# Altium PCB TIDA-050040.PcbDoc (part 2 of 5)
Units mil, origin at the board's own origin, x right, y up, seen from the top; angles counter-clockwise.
Board outline 4045.79 x 2180 mil, 6 copper layers (Top Layer, Signal Layer 1, Signal Layer 2, Signal Layer 3, Signal Layer 4, Bottom Layer), stack 61.485 mil thick; 343 components, 188 nets, 986 pads, 710 vias.

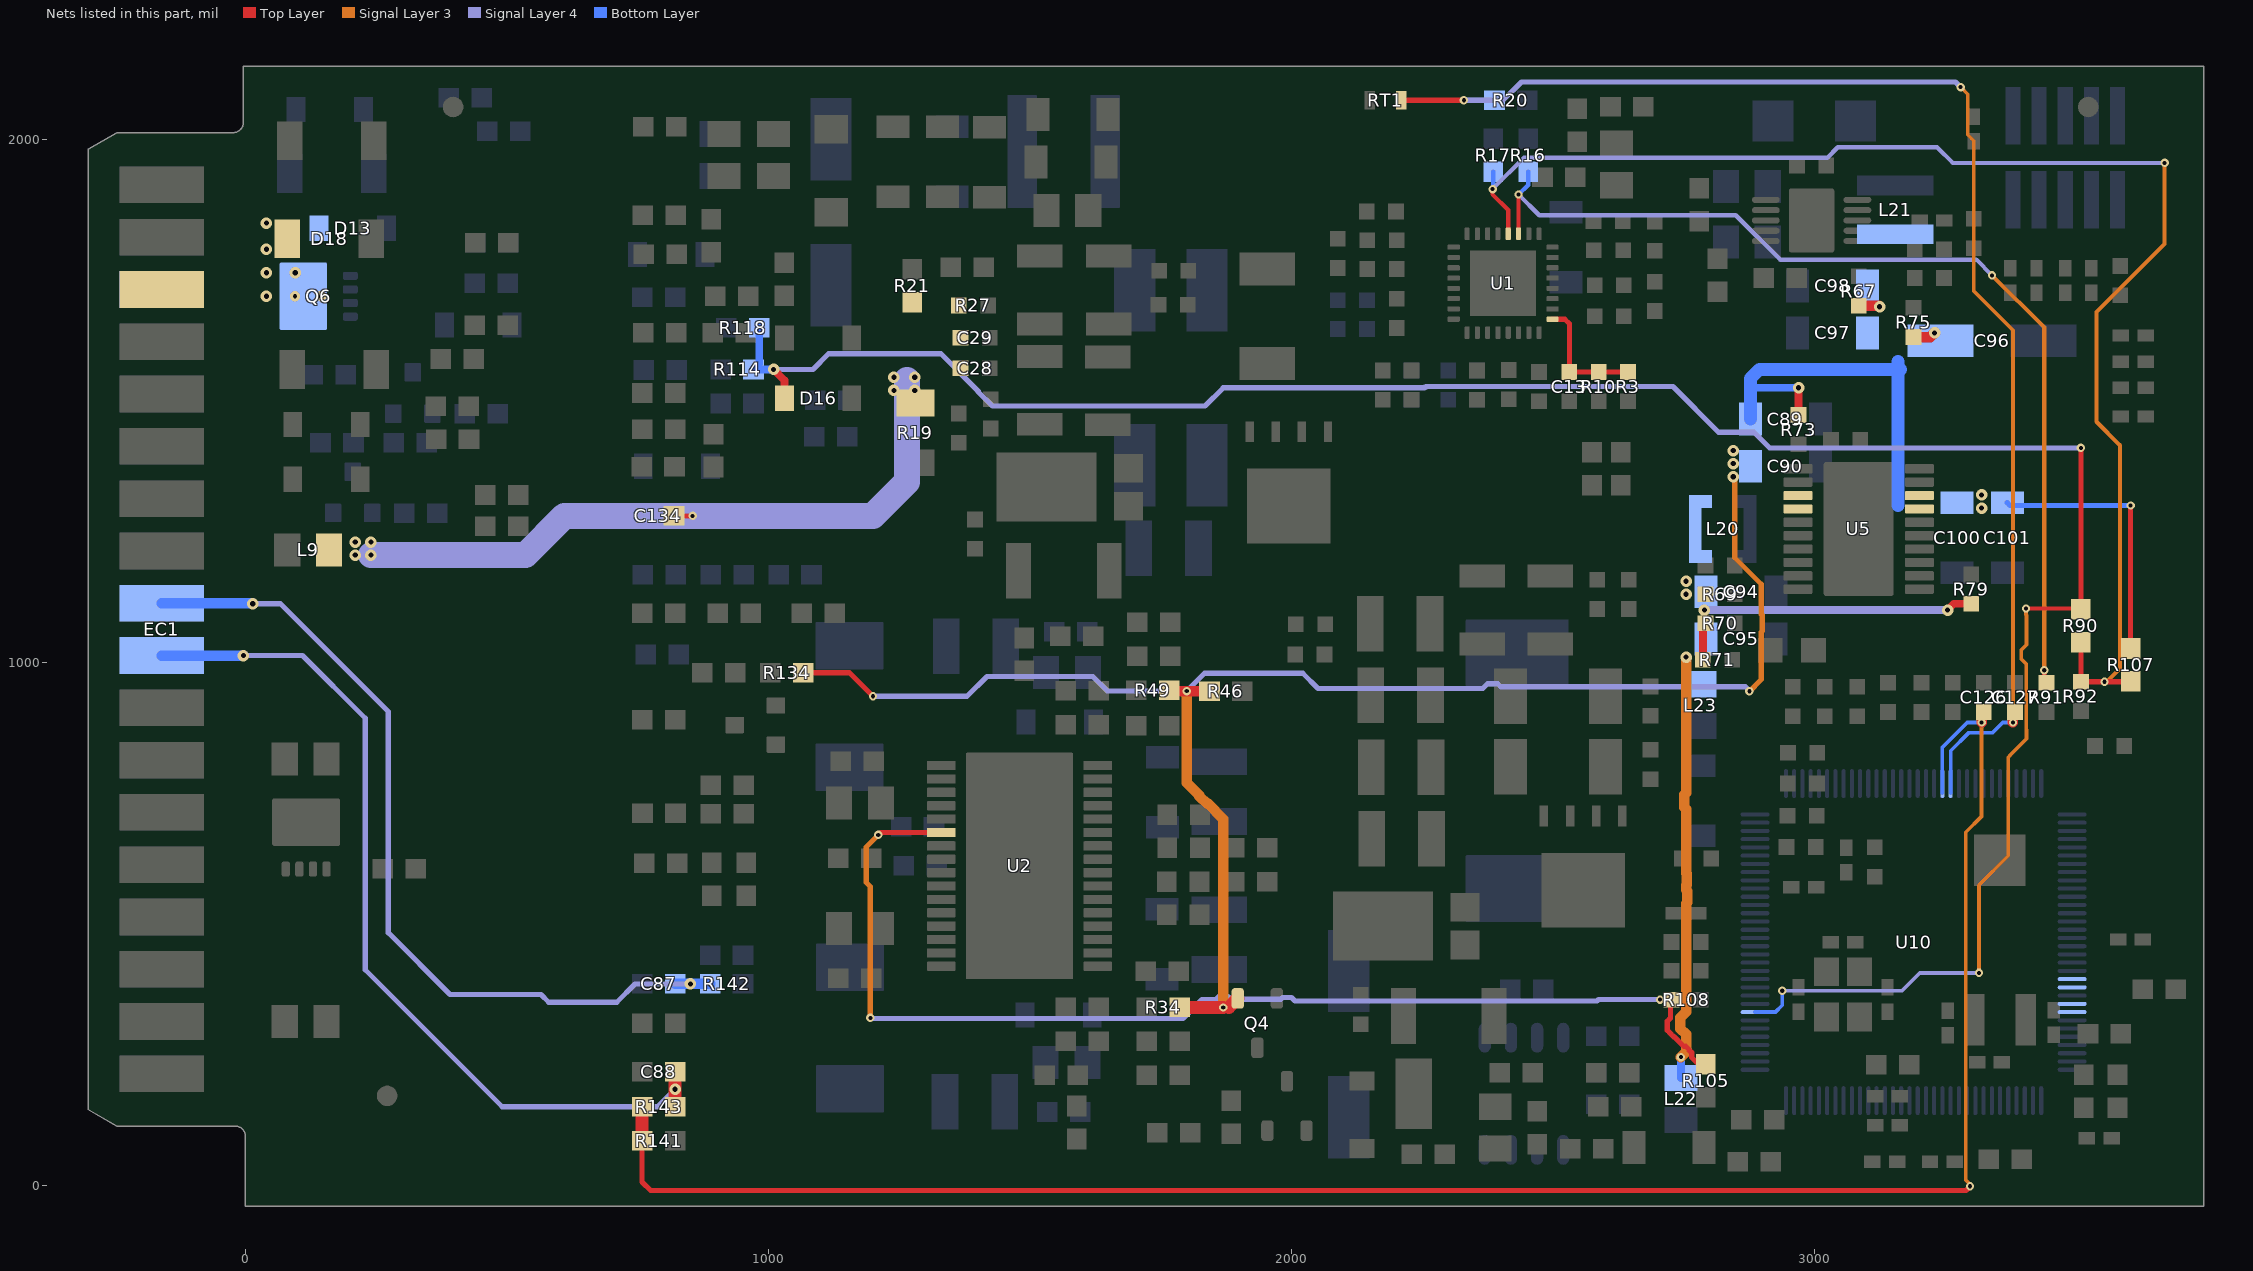
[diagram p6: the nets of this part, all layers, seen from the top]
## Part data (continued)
C5 C6 C7 C8 C30: library part CMP-0009134-2, "CAP, CERM, 4.7 uF, 100 V, +/- 10%, X7S, 1210", Cap_Case=1210_220, Manufacturer=TDK, PartNumber=C3225X7S2A475K200AB, Supplier Part Number 1=445-6042-1-ND, TempCo=X7S, Tolerance_%=10%, Value1="0.004236 ohm", ValueDisplayed=4.7uF
C11: library part CMP-0011198-2, "CAP, AL, 33 uF, 80 V, +/- 20%, 1.3 ohm, AEC-Q200 Grade 2, SMD", Cap_Case=F, Manufacturer=Panasonic, Supplier Part Number 1=PCE3829CT-ND, Tolerance_%=20%, Value1="1.3 ohm", Value2=80V, ValueDisplayed=33uF
C12 C13 C34 C37: library part CMP-0006844-4, "CAP, CERM, 1000 pF, 50 V, +/- 5%, X7R, AEC-Q200 Grade 1, 0603", Cap_Case=0603, Manufacturer=MuRata, PartNumber=GRM188R71H102KA01D, Supplier Part Number 1=490-1494-1-ND, TempCo=X7R, Tolerance_%=10%, Value1=Unknown, Value2=50V, ValueDisplayed=1000pF
C14: library part CMP-0085252-1, "CAP, CERM, 0.047 µF, 50 V,+/- 5%, X7R, 0603", Cap_Case=0603, Manufacturer=MuRata, Supplier Part Number 1=490-1522-1-ND, TempCo=X7R, Tolerance_%=10%, Value1=Unknown, Value2=25V, ValueDisplayed=0.047uF
C15 C40: library part CMP-0006822-4, "CAP, CERM, 100 pF, 50 V, +/- 5%, C0G/NP0, 0603", Cap_Case=0603, Manufacturer="Wurth Elektronik", TempCo=C0G/NP0, Tolerance_%=5%, Value1=Unknown, Value2=50V, ValueDisplayed=100pF
C16: library part CMP-0008801-2, "CAP, CERM, 1 uF, 100 V, +/- 10%, X7R, 1206", Cap_Case=1206, Manufacturer=Samsung, PartNumber=CL31B105KCHNNNE, Supplier Part Number 1=1276-1838-1-ND, TempCo=X7R, Tolerance_%=10%, Value1=Unknown, ValueDisplayed=1uF
C17 C24 C31 C32 C42 C45 C49 C57 C65 C66 C74 C85 C87 C88: library part CMP-0007148-4, "CAP, CERM, 3300 pF, 100 V, +/- 10%, X7R, AEC-Q200 Grade 1, 0603", Cap_Case=0603, Manufacturer=MuRata, Supplier Part Number 1=GCM188R72A332KA37D-ND, TempCo=X7R, Tolerance_%=10%, Value1=Unknown, Value2=100V, ValueDisplayed=3300pF
C38 C39: library part CMP-0007499-4, "CAP, CERM, 2.2 uF, 16 V, +/- 10%, X7R, 0603", Cap_Case=0603, Manufacturer=MuRata, PartNumber=GRM188Z71C225KE43, Supplier Part Number 1=81-GRM188Z71C225KE3D, TempCo=X7R, Tolerance_%=10%, Value1=Unknown, Value2=16V, ValueDisplayed=2.2uF
C41: library part CMP-0007099-4, "CAP, CERM, 0.1 uF, 100 V, +/- 10%, X7S, AEC-Q200 Grade 1, 0603", Cap_Case=0603, Manufacturer=TDK, Supplier Part Number 1=445-6938-1-ND, TempCo=X7S, Tolerance_%=10%, Value1="0.04959 ohm", ValueDisplayed=0.1uF
C43 C47: library part CMP-0008791-2, "CAP, CERM, 2.2 uF, 100 V, +/- 20%, X7S, AEC-Q200 Grade 1, 1206_190", Alternate Manufacturer="Taiyo Yuden", Alternate PartNumber=HMJ316BC7225MLHTE, Cap_Case=1206, Manufacturer=TDK, Supplier Part Number 1=445-12947-1-ND, TempCo=X7S, Tolerance_%=20%, Value1=Unknown, Value2=100V, ValueDisplayed=2.2uF
C44 C64: library part CMP-0007981-2, "CAP, CERM, 0.22 uF, 100 V, +/- 10%, X7S, AEC-Q200 Grade 1, 0805", Alternate Manufacturer="Taiyo Yuden", Alternate PartNumber=HMJ212BB7224KGHT, Cap_Case=0805, Manufacturer=TDK, Supplier Part Number 1=445-7959-1-ND, TempCo=X7S, Tolerance_%=10%, Value1="0.019477 ohm", Value2=100V, ValueDisplayed=0.22uF
C46 C63: library part CMP-0007099-4, "CAP, CERM, 0.1 uF, 100 V, +/- 10%, X7S, AEC-Q200 Grade 1, 0603", Cap_Case=0603, Manufacturer=TDK, Supplier Part Number 1=445-6938-1-ND, TempCo=X7S, Tolerance_%=10%, Value1="0.04959 ohm", Value2=100V, ValueDisplayed=0.1uF
C48 C62: library part CMP-0007085-4, "CAP, CERM, 2200 pF, 100 V, +/- 10%, X7R, AEC-Q200 Grade 1, 0603", Cap_Case=0603, Manufacturer=MuRata, Supplier Part Number 1=GRM188R71C222KA01D-ND, TempCo=X7R, Tolerance_%=10%, Value1=Unknown, Value2=16V, ValueDisplayed=2200pF
C50 C60: library part CMP-0007077-5, "CAP, CERM, 0.1 uF, 25 V, +/- 10%, X7R, AEC-Q200 Grade 1, 0603", Cap_Case=0603, Manufacturer=TDK, Supplier Part Number 1=445-5667-1-ND, TempCo=X7R, Tolerance_%=10%, Value1=Unknown, Value2=25V, ValueDisplayed=0.1uF
C51 C61: library part CMP-0007467-4, "CAP, CERM, 1000 pF, 100 V, +/- 10%, X7R, 0603", Cap_Case=0603, Manufacturer=MuRata, Supplier Part Number 1=490-1472-1-ND, TempCo=X7R, Tolerance_%=10%, Value1=Unknown, Value2=100V, ValueDisplayed=1000pF
C52 C59: library part CMP-0009148-2, "CAP, CERM, 1.5 uF, 100 V, +/- 10%, X7R, AEC-Q200 Grade 1, 1210", Cap_Case=1210_220, Manufacturer=TDK, Supplier Part Number 1=445-13014-1-ND, TempCo=X7R, Tolerance_%=10%, Value1="0.003867 ohm", Value2=100V, ValueDisplayed=1.5uF
C53 C55: library part CMP-0007136-5, "CAP, CERM, 1 uF, 16 V, +/- 10%, X7R, AEC-Q200 Grade 1, 0603", Cap_Case=0603, Manufacturer=MuRata, Supplier Part Number 1=490-5241-6-ND, TempCo=X7R, Tolerance_%=10%, Value1=Unknown, Value2=16V, ValueDisplayed=1uF
C54 C56 C58: library part CMP-0085536-1, "CAP, CERM, 0.1 µF, 16 V,+/- 10%, X7R, 0603", Cap_Case=0603, Manufacturer="Samsung Electro-Mechanics", TempCo=X7R, Tolerance_%=10%, Value2=16V, ValueDisplayed=0.1µF
C67 C71 C72 C75 C80: library part CMP-0007725-2, "CAP, CERM, 0.1 uF, 50 V, +/- 10%, X7R, AEC-Q200 Grade 0, 0805", Cap_Case=0805, Manufacturer=Kemet, Supplier Part Number 1=399-6928-1-ND, TempCo=X7R, Tolerance_%=10%, Value1=Unknown, Value2=50V, ValueDisplayed=0.1uF
C68: library part CMP-0007143-4, "CAP, CERM, 0.01 uF, 50 V, +/- 10%, X7R, AEC-Q200 Grade 1, 0603", Cap_Case=0603, Manufacturer=MuRata, Supplier Part Number 1=490-4778-1-ND, TempCo=X7R, Tolerance_%=10%, Value1=Unknown, Value2=50V, ValueDisplayed=0.01uF
C69 C70 C76 C77 C78 C79: library part CMP-0008702-2, "CAP, CERM, 4.7 uF, 50 V, +/- 10%, X7R, 1206", Cap_Case=1206_180, Manufacturer=TDK, Supplier Part Number 1=445-8032-1-ND, TempCo=X7R, Tolerance_%=10%, Value1="0.003158 ohm", Value2=50V, ValueDisplayed=4.7uF
C73: library part CMP-0011177-2, "CAP, AL, 100 uF, 50 V, +/- 20%, 0.34 ohm, AEC-Q200 Grade 2, SMD", Cap_Case=F, Manufacturer=Panasonic, Supplier Part Number 1=PCE3809CT-ND, Tolerance_%=20%, Value1="0.34 ohm", Value2=50V, ValueDisplayed=100uF
C81: library part CMP-0860912-1, "CAP, CERM, 220 pF, 100 V,+/- 5%, C0G/NP0, AEC-Q200 Grade 1, 0603", Cap_Case=0603, Manufacturer=MuRata, TempCo=C0G/NP0, Tolerance_%=5%, Value2=100V, ValueDisplayed=220pF
C82 C83: library part CMP-0080704-2, "CAP, CERM, 15 pF, 100 V,+/- 5%, C0G/NP0, AEC-Q200 Grade 1, 0603", Cap_Case=0603, Manufacturer=MuRata, Supplier Part Number 1=490-4941-1-ND, TempCo=C0G/NP0, Tolerance_%=5%, Value2=100V, ValueDisplayed=15pF
C86 C133 C134: library part CMP-0007468-5, "CAP, CERM, 0.01 uF, 100 V, +/- 10%, X7R, 0603", Cap_Case=0603, Manufacturer=MuRata, Supplier Part Number 1=GRM188R72A103KA01D-ND, TempCo=X7R, Tolerance_%=10%, Value1=Unknown, Value2=100V, ValueDisplayed=0.01uF
C89 C90 C94 C95 C97 C98 C100 C101 C110: library part CMP-0008965-2, "CAP, CERM, 10 uF, 25 V, +/- 10%, X7R, 1206", Cap_Case=2220, Manufacturer=MuRata, PartNumber=GRM31CR71E106KA12L, Supplier Part Number 1=81-GRM31CR71E106KA12, TempCo=X7R, Tolerance_%=10%, Value1=Unknown, Value2=25V, ValueDisplayed=10uF
C91: library part CMP-0007469-4, "CAP, CERM, 0.1 uF, 100 V, +/- 10%, X7R, 0603", Cap_Case=0603, Manufacturer=MuRata, PartNumber=GRM188R71C104KA01D, Supplier Part Number 1=490-1532-1-ND, TempCo=X7R, Tolerance_%=10%, Value1=Unknown, Value2=16V, ValueDisplayed=0.1uF
C92: library part CMP-0007980-2, "CAP, CERM, 1 uF, 100 V, +/- 10%, X7S, AEC-Q200 Grade 1, 0805", Cap_Case=0805, Manufacturer=TDK, Supplier Part Number 1=445-6974-1-ND, TempCo=X7S, Tolerance_%=10%, Value1="0.008255 ohm", Value2=100V, ValueDisplayed=1uF
C93: library part CMP-0007969-2, "CAP, CERM, 0.1 uF, 100 V, +/- 10%, X7R, AEC-Q200 Grade 1, 0805", Cap_Case=0805, Manufacturer=TDK, Supplier Part Number 1=445-5827-1-ND, TempCo=X7R, Tolerance_%=10%, Value1="0.020726 ohm", Value2=100V, ValueDisplayed=0.1uF
C96: library part CMP-0010733-1, "CAP, AL, 100 uF, 16 V, +/- 20%, 0.26 ohm, AEC-Q200 Grade 2, SMD", Cap_Case=D, Manufacturer=Panasonic, Supplier Part Number 1=PCE4533CT-ND, Tolerance_%=20%, Value1="0.26 ohm", Value2=16V, ValueDisplayed=100uF
C99: library part CMP-0080104-1, "CAP, CERM, 1 µF, 16 V,+/- 10%, X7R, AEC-Q200 Grade 1, 0603", Cap_Case=0603, Manufacturer=MuRata, PartNumber=GRM188R71E105KA12D, Supplier Part Number 1=490-5307-1-ND, TempCo=X7R, Tolerance_%=10%, Value1=Unknown, Value2=25V, ValueDisplayed=1uF
C102: library part CMP-0006503-2, "CAP, CERM, 5 pF, 100 V, +/- 5%, C0G/NP0, 0402", Cap_Case=0402, Manufacturer=MuRata, Supplier Part Number 1=490-7291-1-ND, TempCo=C0G/NP0, Tolerance_%=5%, Value1=Unknown, Value2=100V, ValueDisplayed=5pF
C103: library part CMP-0007086-4, "CAP, CERM, 0.022 uF, 100 V, +/- 10%, X7R, AEC-Q200 Grade 1, 0603", Cap_Case=0603, Manufacturer=TDK, Supplier Part Number 1=445-5814-1-ND, TempCo=X7R, Tolerance_%=10%, Value1="0.083542 ohm", Value2=100V, ValueDisplayed=0.022uF
C104: library part CMP-0860984-1, "CAP, CERM, 3900 pF, 100 V,+/- 5%, X7R, 0603", Cap_Case=0603, Manufacturer=MuRata, PartNumber=GRM188R71H392KA01D, Supplier Part Number 1=490-1504-1-ND, TempCo=X7R, Tolerance_%=10%, Value1=Unknown, Value2=50V, ValueDisplayed=3900pF
C105 C106 C107 C108 C109 C113 C115 C119: library part CMP-0006641-2, "CAP, CERM, 0.1 uF, 16 V, +/- 10%, X7R, 0402", Cap_Case=0402, Manufacturer=MuRata, Supplier Part Number 1=490-3261-1-ND, TempCo=X7R, Tolerance_%=10%, Value1=Unknown, Value2=16V, ValueDisplayed=0.1uF
C111: library part CMP-0007356-5, "CAP, CERM, 2.2 uF, 35 V, +/- 10%, X5R, 0603", Cap_Case=0603, Manufacturer=MuRata, Supplier Part Number 1=490-3296-1-ND, TempCo=X5R, Tolerance_%=10%, Value1=Unknown, Value2=16V, ValueDisplayed=2.2uF
C112: library part CMP-0086061-1, "CAP, CERM, 1 µF, 25 V,+/- 10%, X5R, 0402", Cap_Case=0402, Manufacturer=MuRata, Supplier Part Number 1=490-3890-1-ND, TempCo=X5R, Tolerance_%=10%, Value1=Unknown, Value2=10V, ValueDisplayed=1uF
C114: library part CMP-0008814-2, "CAP, CERM, 2.2 uF, 50 V, +/- 10%, X7R, AEC-Q200 Grade 1, 1206", Cap_Case=1206, Manufacturer=MuRata, PartNumber=GRM31CR71H225KA88L, Supplier Part Number 1=490-3367-1-ND, TempCo=X7R, Tolerance_%=10%, Value1=Unknown, Value2=50V, ValueDisplayed=2.2uF
C116 C117 C118 C124 C125 C126 C127 C128 C129 C130 C131 C132: library part CMP-0006921-4, "CAP, CERM, 330 pF, 50 V, +/- 10%, X7R, 0603", Cap_Case=0603, Manufacturer=Kemet, Supplier Part Number 1=399-1073-1-ND, TempCo=X7R, Tolerance_%=10%, Value1=Unknown, Value2=50V, ValueDisplayed=330pF
C120 C121 C122 C123: library part CMP-0006415-2, "CAP, CERM, 12 pF, 50 V, +/- 5%, C0G/NP0, 0402", Cap_Case=0402, Manufacturer=MuRata, Supplier Part Number 1=14T3292, TempCo=C0G/NP0, Tolerance_%=5%, Value1=Unknown, Value2=50V, ValueDisplayed=12pF
D1 D2: library part CMP-0028754-2, "Diode, Schottky, 100 V, 3 A, AEC-Q101, PowerDI5", Manufacturer="Diodes Inc.", Value1=3A, Value2=0.76V
D3 D4: library part CMP-0080761-2, "Diode, Switching, 100 V, 0.25 A, AEC-Q101, SOD-123", Manufacturer=Vishay-Semiconductor, Value1=0.25A, Value2=1.25V
D5: library part CMP-0085086-1, "Diode, TVS, Bi, 28 V, 45.4 Vc, 400 W, 8.8 A, AEC-Q101, SMA (non-polarized)", Manufacturer=Littelfuse, Value1=45.4V
D6 D7 D13 D14: library part CMP-0750148-1, "Diode, Switching, 100 V, 0.3 A, AEC-Q101, SOD-123", Manufacturer="Diodes Inc.", Value1=0.3A, Value2=1.25V
D8 D9 D15 D16: library part CMP-0077593-3, "Diode, Zener, 3 V, 500 mW, SOD-123", Manufacturer=Vishay-Semiconductor, Power_W=500mW, Value1=0.5W
D10: library part CMP-0002980-3, "LED, Green, SMD", Color=Green, Manufacturer=OSRAM, PartNumber="LG R971-KN-1", Value1=W, Value2=2.2V
D11: library part CMP-0028837-2, "Diode, Schottky, 60 V, 2 A, AEC-Q101, SMA", Manufacturer=Vishay-Semiconductor, PartNumber=SS26SHE3_A/H, Value1=2A, Value2=0.75V
D12 D18 D19 D20: library part CMP-0028823-2, "Diode, Schottky, 30 V, 5 A, AEC-Q101, SMAF", Manufacturer="Fairchild Semiconductor", Value1=5A, Value2=0.54V
D17: library part CMP-0077570-3, "Diode, Zener, 10 V, 500 mW, AEC-Q101, SOD-123", Manufacturer=Vishay-Semiconductor, Power_W=500mW, Value1=0.5W
D21: library part CMP-0029032-2, "Diode, Switching, 100 V, 0.2 A, SOD-123", Manufacturer="ON Semiconductor", Value1=0.2A, Value2=1V
EC1: library part CMP-0077097-2, "Card Edge Footprint, 2.54mm, 18x2", Manufacturer="Sullins Connector Solutions"
FID1 FID2 FID3: library part CMP-0077181-1, "Fiducial mark.  There is nothing to buy or mount.", Manufacturer=N/A
J3: library part CMP-0075629-2, "Header, 1.27mm, 5x2, Gold, Black, SMT", Color=Black, Current_A=3.3A, Manufacturer=Samtec, PartNumber=FTSH-105-01-F-DV, Supplier Part Number 1=SAM8795-ND
L1: library part CMP-0084138-1, "Inductor, Shielded, 22 µH, 6.9 A, 0.0341 ohm, AEC-Q200 Grade 0, SMD", Manufacturer=TDK, Value1="0.0341 ohm", Value2=6.9A, ValueDisplayed=22µH
L2 L5 L6 L8 L9: library part CMP-0003069-1, "Ferrite Bead, 33 ohm @ 100 MHz, 4 A, 0805", Manufacturer="Wurth Elektronik", Supplier Part Number 1=732-4636-1-ND, Value1="0.008 ohm", Value2=4A, ValueDisplayed="33 ohm"
L3: library part CMP-0012870-2, "Coupled inductor, 33 uH, 5.6 A, 0.15 ohm, TH", Manufacturer=Coilcraft, ValueDisplayed=33uH
L4 L7: library part CMP-0081480-2, "Inductor, Shielded, Metal Composite, 68 µH, 1.8 A, 0.316 ohm, SMD", Manufacturer=TDK, Value1="0.316 ohm", Value2=1.8A, ValueDisplayed=68µH
L10: library part CMP-0061017-2, "Inductor, Shielded, Composite, 3.3 µH, 8 A, 0.02081 ohm, AEC-Q200 Grade 1, SMD", Manufacturer=Coilcraft, Value1="0.02081 ohm", Value2=8A, ValueDisplayed=3.3µH
L20: library part CMP-0060436-1, "Inductor, Shielded Drum Core, Ferrite, 2.2 uH, 1.1 A, 0.22 ohm, SMD", Manufacturer=Coilcraft, Value1="0.22 ohm", Value2=1.1A, ValueDisplayed=2.2uH
L21: library part CMP-0061649-2, "Inductor, Shielded, Composite, 15 uH, 2.8 A, 0.109 ohm, SMD", Manufacturer=Coilcraft, PartNumber=XAL4040-153MEB, Supplier Part Number 1=994-XAL4040-153MEB, Value1="0.109 ohm", Value2=2.8A, ValueDisplayed=15uH
L22: library part CMP-0003363-1, "Ferrite Bead, 220 ohm @ 100 MHz, 2 A, 0805", Manufacturer=MuRata, PartNumber=BLM21PG221SN1D, Supplier Part Number 1=490-1054-1-ND, Value1="0.045 ohm", Value2=2A, ValueDisplayed="220 ohm"
L23: library part CMP-0003306-1, "Ferrite Bead, 60 ohm @ 100 MHz, 3 A, 0805", Manufacturer="Taiyo Yuden", PartNumber=BKP2125HS600-T, Supplier Part Number 1=587-1932-1-ND, Value1="0.025 ohm", Value2=3A, ValueDisplayed="60 ohm"
LOGO2: library part CMP-0074837-1, "IEC 61010-1 Hot Surface Warning"
Logo3: library part CMP-0074847-1, "FCC_disclaimer"
Logo4: library part CMP-0074769-1
Q1 Q3: library part CMP-0086155-1, "MOSFET, N-CH, 80 V, 60 A, AEC-Q101, PowerPAK_SO-8L", Alternate Manufacturer=None, Manufacturer=Vishay-Siliconix, Value1="? ohm", Value2="36 nC"
Q4: library part CMP-0077896-2, "MOSFET, P-CH, -20 V, -3.7 A, SOT-23", Alternate Manufacturer=None, Manufacturer=Vishay-Siliconix, Value1=0.03, Value2="12.5 nC"
Q5: library part CMP-0000419-2, "Transistor, NPN, 40 V, 0.2 A, SOT-23", Manufacturer="ON Semiconductor", Supplier Part Number 1=MMBT3904LT1GOSCT-ND, Value1="0.2 A", Value2=300
Q6: library part CMP-0000123-4, "MOSFET, P-CH, -30 V, -13.9 A, PowerPAK 1212", Alternate Manufacturer=None, Manufacturer=Vishay-Siliconix, Value1=0.022, Value2="20.5 nC"
Q7 Q8 Q10: library part CMP-0087176-1, "MOSFET N-CH 100V 170MA SOT23-3", Manufacturer="Diodes Incorporated"
Q9: library part CMP-0000752-2, "MOSFET, N-CH, 40 V, 12 A, AEC-Q101, PowerPAK 1212", Alternate Manufacturer=None, Manufacturer=Vishay-Siliconix, Supplier Part Number 1=SQS840EN-T1_GE3-ND, Value1=0, Value2="15 nC"
R1 R18: library part CMP-0016180-3, "RES, 7.5, 5%, 0.75 W, AEC-Q200 Grade 0, 2010", Manufacturer=Vishay-Dale, PartNumber=CRCW20107R50JNEF, Power_W=750mW, Supplier Part Number 1=541-7.5WCT-ND, TempCo="200 ppm/C", Tolerance_%=5%, Value2=0.75W, Value_Code=7R50, ValueDisplayed=7.5
R2 R14 R25: library part CMP-0025697-4, "RES, 0, 5%, 0.1 W, AEC-Q200 Grade 0, 0603", Manufacturer=Vishay-Dale, Power_W=100mW, Supplier Part Number 1=541-0.0GCT-ND, TempCo="200 ppm/C", Tolerance_%=5%, Value2=0.1W, Value_Code=0000, ValueDisplayed=0
R3 R58 R60 R116 R118 R121: library part CMP-0021990-4, "RES, 100 k, 1%, 0.1 W, AEC-Q200 Grade 0, 0603", Manufacturer=Vishay-Dale, Power_W=100mW, Supplier Part Number 1=541-100KHCT-ND, TempCo="100 ppm/C", Tolerance_%=1%, Value2=0.1W, Value_Code=100k
R4 R30: library part CMP-0021991-4, "RES, 100, 1%, 0.1 W, AEC-Q200 Grade 0, 0603", Manufacturer=Vishay-Dale, PartNumber=CRCW0603100RFKEA, Power_W=100mW, Supplier Part Number 1=541-100HCT-ND, TempCo="100 ppm/C", Tolerance_%=1%, Value2=0.1W, Value_Code=100R, ValueDisplayed=100
R5 R8 R21 R38 R40: library part CMP-0022200-4, "RES, 200 k, 1%, 0.1 W, AEC-Q200 Grade 0, 0603", Manufacturer=Vishay-Dale, Power_W=100mW, Supplier Part Number 1=541-200KHCT-ND, TempCo="100 ppm/C", Tolerance_%=1%, Value2=0.1W, Value_Code=200k
R6 R9 R32: library part CMP-0016519-2, "RES, 0.04, 1%, 1 W, 2010", Manufacturer="Stackpole Electronics Inc", Power_W=1W, Supplier Part Number 1=CSRN2010FK40L0CT-ND, TempCo="250 ppm/C", Tolerance_%=1%, Value_Code=R040, ValueDisplayed=0.04
R7 R13 R16 R17 R20 R46 R48 R50 R99 R102 R103 R105: library part CMP-0023341-3, "RES, 10.0 k, 1%, 0.1 W, AEC-Q200 Grade 0, 0603", Manufacturer="Stackpole Electronics Inc", Power_W=100mW, Supplier Part Number 1=RMCF0603FT10K0CT-ND, TempCo="100 ppm/C", Tolerance_%=1%, Value2=0.1W, Value_Code=10k0, ValueDisplayed=10.0k
R10: library part CMP-0022450-4, "RES, 4.12 k, 1%, 0.1 W, AEC-Q200 Grade 0, 0603", Manufacturer=Vishay-Dale, Power_W=100mW, Supplier Part Number 1=541-4.12KHCT-ND, TempCo="100 ppm/C", Tolerance_%=1%, Value2=0.1W, Value_Code=4k12, ValueDisplayed=4.12k
R11: library part CMP-0021009-3, "RES, 1.00, 1%, 0.125 W, AEC-Q200 Grade 0, 0805", Manufacturer=Vishay-Dale, PartNumber=CRCW08051R00FKEA, Power_W=125mW, Supplier Part Number 1=72M6849, TempCo="100 ppm/C", Tolerance_%=1%, Value2=0.125W, Value_Code=1R00, ValueDisplayed=1.00
R12: library part CMP-0022687-3, "RES, 14.7 k, 1%, 0.1 W, AEC-Q200 Grade 0, 0603", Manufacturer=Panasonic, Power_W=100mW, Supplier Part Number 1=P14.7KHCT-ND, TempCo="100 ppm/C", Tolerance_%=1%, Value2=0.1W, Value_Code=14k7, ValueDisplayed=14.7k
R15 R28 R90 R107: library part CMP-0022002-4, "RES, 10.0 M, 1%, 0.1 W, AEC-Q200 Grade 0, 0603", Manufacturer=Vishay-Dale, Power_W=100mW, Supplier Part Number 1=541-10.0MHCT-ND, TempCo="100 ppm/C", Tolerance_%=1%, Value2=0.1W, Value_Code=10M0, ValueDisplayed=10.0M
R19: library part CMP-0017835-2, "RES, 0.165, 1%, 0.25 W, 1206", Manufacturer="Yageo America", Power_W=250mW, Supplier Part Number 1=311-0.165ANCT-ND, TempCo="75 ppm/C", Tolerance_%=1%, Value2=0.25W, Value_Code=R165, ValueDisplayed=0.165
R22: library part CMP-0022408-4, "RES, 402 k, 1%, 0.1 W, AEC-Q200 Grade 0, 0603", Manufacturer=Vishay-Dale, Power_W=100mW, Supplier Part Number 1=541-402KHCT-ND, TempCo="100 ppm/C", Tolerance_%=1%, Value2=0.1W, Value_Code=402k
R23 R39 R41 R44 R54 R55 R56 R57 R59 R61 R62 R66 R111 R112 R113 R114 R115 R117 R120 R123 R124 R125 R126 R128 R129 R130 R131 R135 R136 R140 R141: library part CMP-0021998-4, "RES, 10.0 k, 1%, 0.1 W, AEC-Q200 Grade 0, 0603", Manufacturer=Vishay-Dale, Power_W=100mW, Supplier Part Number 1=541-10.0KHCT-ND, TempCo="100 ppm/C", Tolerance_%=1%, Value2=0.1W, Value_Code=10k0, ValueDisplayed=10.0k
R24: library part CMP-0021990-4, "RES, 100 k, 1%, 0.1 W, AEC-Q200 Grade 0, 0603", Manufacturer=Vishay-Dale, PartNumber=CRCW0603100KFKEA, Power_W=100mW, Supplier Part Number 1=541-100KHCT-ND, TempCo="100 ppm/C", Tolerance_%=1%, Value2=0.1W, Value_Code=100k
R26 R27: library part CMP-0022003-4, "RES, 10.0, 1%, 0.1 W, AEC-Q200 Grade 0, 0603", Manufacturer=Vishay-Dale, PartNumber=CRCW060310R0FKEA, Power_W=100mW, Supplier Part Number 1=541-10.0HCT-ND, TempCo="100 ppm/C", Tolerance_%=1%, Value2=0.1W, Value_Code=10R0, ValueDisplayed=10.0
R29: library part CMP-0022665-4, "RES, 9.09 k, 1%, 0.1 W, AEC-Q200 Grade 0, 0603", Manufacturer=Vishay-Dale, Power_W=100mW, Supplier Part Number 1=541-9.09KHCT-ND, TempCo="100 ppm/C", Tolerance_%=1%, Value2=0.1W, Value_Code=9k09, ValueDisplayed=9.09k
R31: library part CMP-0022036-4, "RES, 130 k, 1%, 0.1 W, AEC-Q200 Grade 0, 0603", Manufacturer=Vishay-Dale, Power_W=100mW, Supplier Part Number 1=541-130KHCT-ND, TempCo="100 ppm/C", Tolerance_%=1%, Value2=0.1W, Value_Code=130k
R33: library part CMP-0022440-4, "RES, 47.5, 1%, 0.1 W, AEC-Q200 Grade 0, 0603", Manufacturer=Vishay-Dale, Power_W=100mW, Supplier Part Number 1=541-47.5HCT-ND, TempCo="100 ppm/C", Tolerance_%=1%, Value2=0.1W, Value_Code=47R5, ValueDisplayed=47.5
R34 R49: library part CMP-0022068-4, "RES, 15.8 k, 1%, 0.1 W, AEC-Q200 Grade 0, 0603", Manufacturer=Vishay-Dale, Power_W=100mW, Supplier Part Number 1=541-15.8KHCT-ND, TempCo="100 ppm/C", Tolerance_%=1%, Value2=0.1W, Value_Code=15k8, ValueDisplayed=15.8k
R35 R52: library part CMP-0015068-3, "RES, 0.1, 1%, 0.33 W, AEC-Q200 Grade 1, 1210", Alternate Manufacturer=Yageo, Alternate PartNumber=RL1210FR-070R1L, Manufacturer=Panasonic, Power_W=330mW, Supplier Part Number 1=P100NACT-ND, TempCo="100 ppm/C", Tolerance_%=1%, Value2=0.33W, Value_Code=R100, ValueDisplayed=0.1
R36 R43 R51 R108 R109 R110 R122 R127 R132 R133 R134 R137 R138 R139 R142 R143: library part CMP-0022109-5, "RES, 1.00 k, 1%, 0.1 W, AEC-Q200 Grade 0, 0603", Manufacturer=Vishay-Dale, Power_W=100mW, Supplier Part Number 1=541-1.00KHCT-ND, TempCo="100 ppm/C", Tolerance_%=1%, Value2=0.1W, Value_Code=1k00, ValueDisplayed=1.00k
R37 R53: library part CMP-0022324-4, "RES, 30.1 k, 1%, 0.1 W, AEC-Q200 Grade 0, 0603", Manufacturer=Vishay-Dale, Power_W=100mW, Supplier Part Number 1=541-30.1KHCT-ND, TempCo="100 ppm/C", Tolerance_%=1%, Value2=0.1W, Value_Code=30k1, ValueDisplayed=30.1k
R42 R45: library part CMP-0025874-4, "RES, 0, 5%, 0.1 W, AEC-Q200 Grade 0, 0603", Manufacturer=Panasonic, Power_W=100mW, Supplier Part Number 1=P0.0GCT-ND, TempCo="600 ppm/C", Tolerance_%=5%, Value2=0.1W, Value_Code=0000, ValueDisplayed=0
R47: library part CMP-0022237-4, "RES, 24.9 k, 1%, 0.1 W, AEC-Q200 Grade 0, 0603", Manufacturer=Vishay-Dale, Power_W=100mW, Supplier Part Number 1=541-24.9KHCT-ND, TempCo="100 ppm/C", Tolerance_%=1%, Value2=0.1W, Value_Code=24k9, ValueDisplayed=24.9k
R63 R64 R65 R100 R144: library part CMP-0022003-4, "RES, 10.0, 1%, 0.1 W, AEC-Q200 Grade 0, 0603", Manufacturer=Vishay-Dale, Power_W=100mW, Supplier Part Number 1=541-10.0HCT-ND, TempCo="100 ppm/C", Tolerance_%=1%, Value2=0.1W, Value_Code=10R0, ValueDisplayed=10.0
R67 R70 R79: library part CMP-0023133-5, "RES, 47.0 k, 1%, 0.1 W, 0603", Manufacturer=Yageo, PartNumber=RC0603FR-0747KL, Power_W=100mW, Supplier Part Number 1=311-47.0KHRCT-ND, TempCo="100 ppm/C", Tolerance_%=1%, Value2=0.1W, Value_Code=47k0, ValueDisplayed=47.0k
R68: library part CMP-0022701-2, "RES, 402 k, 1%, 0.1 W, AEC-Q200 Grade 0, 0603", Manufacturer=Panasonic, Power_W=100mW, Supplier Part Number 1=P402KHCT-ND, TempCo="100 ppm/C", Tolerance_%=1%, Value2=0.1W, Value_Code=402k
R69: library part CMP-0023026-5, "RES, 31.6 k, 1%, 0.1 W, 0603", Manufacturer=Yageo, PartNumber=RC0603FR-0731K6L, Power_W=100mW, Supplier Part Number 1=311-31.6KHRCT-ND, TempCo="100 ppm/C", Tolerance_%=1%, Value2=0.1W, Value_Code=31k6, ValueDisplayed=31.6k
R71: library part CMP-0023235-5, "RES, 680, 1%, 0.1 W, 0603", Manufacturer=Yageo, PartNumber=RC0603FR-07680RL, Power_W=100mW, Supplier Part Number 1=311-680HRCT-ND, TempCo="100 ppm/C", Tolerance_%=1%, Value2=0.1W, Value_Code=680R, ValueDisplayed=680
R72 R77: library part CMP-0021998-4, "RES, 10.0 k, 1%, 0.1 W, AEC-Q200 Grade 0, 0603", Manufacturer=Vishay-Dale, PartNumber=CRCW060310K0FKEA, Power_W=100mW, Supplier Part Number 1=541-10.0KHCT-ND, TempCo="100 ppm/C", Tolerance_%=1%, Value2=0.1W, Value_Code=10k0, ValueDisplayed=10.0k
R73: library part CMP-0025821-4, "RES, 4.7, 5%, 0.1 W, AEC-Q200 Grade 0, 0603", Manufacturer=Vishay-Dale, PartNumber=CRCW06034R70JNEA, Power_W=100mW, Supplier Part Number 1=541-4.7GCT-ND, TempCo="200 ppm/C", Tolerance_%=5%, Value2=0.1W, Value_Code=4R70, ValueDisplayed=4.7
R74: library part CMP-0022038-4, "RES, 133 k, 1%, 0.1 W, AEC-Q200 Grade 0, 0603", Manufacturer=Vishay-Dale, PartNumber=CRCW0603133KFKEA, Power_W=100mW, Supplier Part Number 1=541-133KHCT-ND, TempCo="100 ppm/C", Tolerance_%=1%, Value2=0.1W, Value_Code=133k
R75: library part CMP-0022486-4, "RES, 52.3 k, 1%, 0.1 W, AEC-Q200 Grade 0, 0603", Manufacturer=Vishay-Dale, PartNumber=CRCW060352K3FKEA, Power_W=100mW, Supplier Part Number 1=541-52.3KHCT-ND, TempCo="100 ppm/C", Tolerance_%=1%, Value2=0.1W, Value_Code=52k3, ValueDisplayed=52.3k
R76: library part CMP-0022659-4, "RES, 95.3 k, 1%, 0.1 W, AEC-Q200 Grade 0, 0603", Manufacturer=Vishay-Dale, PartNumber=CRCW060395K3FKEA, Power_W=100mW, Supplier Part Number 1=541-95.3KHCT-ND, TempCo="100 ppm/C", Tolerance_%=1%, Value2=0.1W, Value_Code=95k3, ValueDisplayed=95.3k
R78: library part CMP-0022581-4, "RES, 71.5 k, 1%, 0.1 W, AEC-Q200 Grade 0, 0603", Manufacturer=Vishay-Dale, Power_W=100mW, Supplier Part Number 1=541-71.5KHCT-ND, TempCo="100 ppm/C", Tolerance_%=1%, Value2=0.1W, Value_Code=71k5, ValueDisplayed=71.5k
R80: library part CMP-0026763-1, "RES, 100, 1%, 0.063 W, AEC-Q200 Grade 0, 0402", Manufacturer="Stackpole Electronics Inc", Power_W=63mW, Supplier Part Number 1=RMCF0402JT100RCT-ND, TempCo="100 ppm/C", Tolerance_%=1%, Value2=0.063W, Value_Code=100R, ValueDisplayed=100
R81 R82 R83 R84: library part CMP-0026754-1, "RES, 10.0 k, 1%, 0.063 W, AEC-Q200 Grade 0, 0402", Manufacturer="Stackpole Electronics Inc", Power_W=63mW, Supplier Part Number 1=RMCF0402FT10K0CT-ND, TempCo="100 ppm/C", Tolerance_%=1%, Value2=0.063W, Value_Code=10k0, ValueDisplayed=10.0k
R85 R86 R87 R88: library part CMP-0026759-1, "RES, 33.0, 1%, 0.063 W, AEC-Q200 Grade 0, 0402", Manufacturer="Stackpole Electronics Inc", Power_W=63mW, Supplier Part Number 1=RMCF0402FT33R0CT-ND, TempCo="100 ppm/C", Tolerance_%=1%, Value2=0.063W, Value_Code=33R0, ValueDisplayed=33.0
R89 R91 R92 R94 R96: library part CMP-0025697-4, "RES, 0, 5%, 0.1 W, AEC-Q200 Grade 0, 0603", Manufacturer=Vishay-Dale, PartNumber=CRCW06030000Z0EA, Power_W=100mW, Supplier Part Number 1=541-0.0GCT-ND, TempCo="200 ppm/C", Tolerance_%=5%, Value2=0.1W, Value_Code=0000, ValueDisplayed=0
R93: library part CMP-0022986-5, "RES, 2.20 k, 1%, 0.1 W, 0603", Manufacturer=Yageo, PartNumber=RC0603FR-072K2L, Power_W=100mW, Supplier Part Number 1=311-2.20KHRCT-ND, TempCo="100 ppm/C", Tolerance_%=1%, Value2=0.1W, Value_Code=2k20, ValueDisplayed=2.20k
R95: library part CMP-0023169-5, "RES, 51.0, 1%, 0.1 W, 0603", Manufacturer=Yageo, Power_W=100mW, Supplier Part Number 1=311-51.0HRCT-ND, TempCo="100 ppm/C", Tolerance_%=1%, Value2=0.1W, Value_Code=51R0, ValueDisplayed=51.0
R97: library part CMP-0022138-4, "RES, 1.00 M, 1%, 0.1 W, AEC-Q200 Grade 0, 0603", Manufacturer=Vishay-Dale, Power_W=100mW, Supplier Part Number 1=541-1.00MHCT-ND, TempCo="100 ppm/C", Tolerance_%=1%, Value2=0.1W, Value_Code=1M00, ValueDisplayed=1.00M
R98 R119: library part CMP-0022747-4, "RES, 10.0 M, 1%, 0.1 W, 0603", Manufacturer=Yageo, Power_W=100mW, Supplier Part Number 1=311-10.0MHRCT-ND, TempCo="100 ppm/C", Tolerance_%=1%, Value2=0.1W, Value_Code=10M0, ValueDisplayed=10.0M
R101: library part CMP-0022457-4, "RES, 4.87 k, 1%, 0.1 W, AEC-Q200 Grade 0, 0603", Manufacturer=Vishay-Dale, Power_W=100mW, Supplier Part Number 1=541-4.87KHCT-ND, TempCo="100 ppm/C", Tolerance_%=1%, Value2=0.1W, Value_Code=4k87, ValueDisplayed=4.87k
R104: library part CMP-0027004-2, "RES, 0, 5%, 0.063 W, 0402", Manufacturer="Yageo America", Power_W=63mW, Supplier Part Number 1=311-0.0JRCT-ND, TempCo="200 ppm/C", Tolerance_%=5%, Value2=0.063W, Value_Code=0000, ValueDisplayed=0
R106: library part CMP-0026889-5, "RES, 2.0 k, 5%, 0.063 W, AEC-Q200 Grade 0, 0402", Manufacturer=Vishay-Dale, Power_W=63mW, Supplier Part Number 1=541-2.0KJCT-ND, TempCo="200 ppm/C", Tolerance_%=5%, Value2=0.063W, Value_Code=2k00, ValueDisplayed=2.0k
RT1: library part CMP-0002534-3, "Thermistor NTC, 100k ohm, 5%, 0603", Manufacturer=MuRata, Power_W=100mW, Supplier Part Number 1=490-2430-1-ND, Tolerance_%=5%
TP1: library part CMP-0055152-1, "Test Point, Miniature, SMT", Manufacturer=Keystone, Supplier Part Number 1=36-5015TR-ND
U1: library part CMP-0084188-3, "Dual Channel Constant Voltage and Constant Current Controller with SPI Interface, RHM0032C (VQFNP-32)", Alternate Manufacturer="Texas Instruments", Operating Temperature Range="-40 to 125 C", Rating=Automotive
U2: library part CMP-0085387-1, "4.5 to 65-V Input Dual 1.6-A Synchronous Buck LED Driver with SPI Control, DAP0032A (HTSSOP-32)", Alternate Manufacturer="Texas Instruments", Alternate PartNumber=TPS92520QDAPQ1
U3: library part CMP-0079113-2, "Local Interconnect Network (LIN) Transceiver with Dominant State Timeout, D0008A (SOIC-8)", Alternate Manufacturer="Texas Instruments", Alternate PartNumber=TLIN1029DQ1
U4: library part CMP-0074018-2, "Automotive 3.5V to 60V, 1.5A Step Down SWIFT(TM) Converter with Eco-Mode(TM), DGQ0010D (VSSOP-10)", Alternate Manufacturer="Texas Instruments", PartNumber=TPS57160QDGQRQ1
U5: library part CMP-0066062-3, "Dual 2.0A, High Frequency Synchronous Step-Down DC-DC  Regulator, PWP0020A (HTSSOP-20)", Alternate Manufacturer="Texas Instruments", Alternate PartNumber=LM26420Q0XMH/NOPB, Operating Temperature Range="-40 to 125 C", PartNumber=LM26420Q0XMHX/NOPB, Rating=Automotive
U10: library part CMP-0077953-1, "MSP432E401YTPDT, PDT0128A (TQFP-128)", Alternate Manufacturer="Texas Instruments", Alternate PartNumber=MSP432E401YTPDTR
Y1: library part CMP-0004653-5, "Crystal, 32.768 kHz,  SMD", Frequency_Fixed=32.768kHz, Frequency Stability=+/-20ppm, Manufacturer="Citizen FineDevice", Supplier Part Number 1=695-CMR200T32.7KY-U
Y2: library part CMP-0004652-3, "Crystal, 25 MHz, 8pF, SMD", Frequency_Fixed=25MHz, Frequency Stability=+/-30ppm, Manufacturer=NDK, Supplier Part Number 1=644-1259-1-ND
ZZ1: library part CMP-0003616-3
ZZ2: library part CMP-0077236-1
ZZ3: library part CMP-0077237-1
ZZ4: library part CMP-0077238-1

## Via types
v1: diameter 16, hole 8, Top Layer to Bottom Layer, tented both sides, 318 vias
v2: diameter 22, hole 10, Top Layer to Bottom Layer, tented both sides, 299 vias
v3: diameter 19.68, hole 7.87, Top Layer to Bottom Layer, 47 vias
v4: diameter 19.68, hole 7.87, Top Layer to Bottom Layer, tented both sides, 28 vias
v5: diameter 50, hole 28, Top Layer to Bottom Layer, 18 vias

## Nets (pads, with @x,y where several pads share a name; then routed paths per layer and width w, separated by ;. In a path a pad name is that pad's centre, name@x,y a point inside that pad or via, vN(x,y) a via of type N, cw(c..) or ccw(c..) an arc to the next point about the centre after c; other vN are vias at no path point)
3V3: C94.1 C95.1 L20.2 L22.1 L23.1 R69.1 R70.2 R71.2 R79.2 | length 1389.1
  Top Layer w15: 2787,1020 R70.2@2787,1070 ; v2(3255,1100) 3267,1112 R79.2@3300,1112
  Signal Layer 3 w20: v1(2745,245) 2755,255 2755,288.41 2744.13,299.28 2744.13,320.72 2755,331.59 2755,538.41 2757.49,540.9 2757.49,562.33 2755,564.82 2755,573.41 2755.87,574.28 2755.87,595.72 2755,596.59 2755,719.17 2751.13,723.04 2751.13,746.96 2755,750.83 v2(2755,1010)
  Signal Layer 4 w15: v2(2790,1100) v2(3255,1100)
  Bottom Layer w15: L22.1@2745,205 v1(2745,245)
  other v2: 2755,1130 2755,1155
5V: C89.1 C90.1 C96.1 C97.1 C98.1 C100.1 C101.1 L21.2 Q4.2 R34.2 R46.2 R49.2 R67.2 R73.1 R75.2 R107.1 R134.2 U5.3 U5.4 U5.17 U5.18 | length 4539.3
  Top Layer w10: R134.2@1066.5,980 1155,980 v1(1200,935) ; R49.2@1766.5,945.99 1777.21,945.99 R49.2@1778.2,945 ; R107.1@3605,1026.5 v1(3605,1300)
  Top Layer w15: R73.1@2970,1473 v2(2970,1525)
  Top Layer w20: R49.2@1778.2,945 v1(1800,945) R46.2@1843.5,945 ; R67.2@3085,1682 v2@3123,1682 ; R75.2@3190,1622 3222,1622 v2(3230,1630)
  Top Layer w25: R34.2@1786.5,340 v1(1870,340) ; 1880.35,340 Q4.2@1897.6,357.24
  Signal Layer 3 w10: v2@2848,1355 2848,1200 2898.75,1149.25 2898.75,1091.81 2900.75,1089.81 2900.75,1060.19 2898.75,1058.19 2898.75,967.25 v1(2876,944.5)
  Signal Layer 3 w20: v1(1800,945) 1800,770 1824.13,745.87 1824.13,744.28 1839.28,729.13 1840.87,729.13 1870,700 v1(1870,340)
  Signal Layer 4 w10: v1(1200,935) 1380,935 1417.87,972.87 1620.33,972.87 1648.2,945 v1(1800,945) 1834,979 2022,979 2051,950 2366.24,950 2375.11,958.87 2394.89,958.87 2400.52,953.24 2868.76,953.24 2876,946 v1(2876,944.5)
  Bottom Layer w10: C101.1@3369.21,1305.25 3374.46,1300 v1(3605,1300)
  Bottom Layer w15: 2878.07,1523.07 2880,1525 v2(2970,1525)
  Bottom Layer w25: C89.1@2878.07,1465 2878.07,1523.07 2878.07,1543.07 2895,1560 3165,1560 ; 3160,1300 3160,1575
  other v2: 3320,1295 3320,1320 2845,1355 2845,1380 2845,1405 3125,1680
A_NTC1: C127.1 R20.1 RT1.2 U10.21 | length 2646
  Top Layer w10: RT1.2@2210,2075 v1(2330,2075)
  Top Layer w20: v1(3380,885) C127.1@3380,905
  Signal Layer 3 w7: v1(3280,2100) 3293.7,2086.3 3293.7,2008.7 3299.37,2003.03 3299.37,2002.87 3305,1997.24 3305,1710 3380,1635 v1(3380,885)
  Signal Layer 4 w10: v1(2330,2075) 2405,2075 2440,2110 3270,2110 v1(3280,2100)
  Bottom Layer w7: U10.21@3260.87,750 3260.87,830.87 3295,865 3340.54,865 3360.54,885 v1(3380,885)
  Bottom Layer w10: v1(2330,2075) R20.1@2388.5,2075
BPWM1: R16.1 R91.2 U1.3 | length 1916.6
  Top Layer w8: U1.3@2434.53,1819.49 v1(2434.53,1894.53) ; R91.2@3440,961 v1(3440,985)
  Signal Layer 3 w8: v1(3340,1740) 3440,1640 v1(3440,985)
  Signal Layer 4 w8: v1(2434.53,1894.53) 2474.06,1855 2850,1855 2935,1770 3310,1770 v1(3340,1740)
  Bottom Layer w8: v1(2434.53,1894.53) 2453,1913 R16.1@2453,1938.5
BUCK_nFLT_1-2: R105.1 R108.2 U2.22 | length 2224
  Top Layer w10: v1(1210,670) 1214.57,674.57 U2.22@1330.59,674.57 ; v1(2705,355) R108.2@2727,355 2725,353 2725,319.52 2719.13,313.65 2719.13,296.35 2725,290.48 2725,290 2730,285 2730.48,285 2731.35,284.13 2731.75,284.13 2750,265.87 2753.65,265.87 2764.52,255 2765,255 2765,254.52 2765.87,253.65 2765.87,244.13 2780,230 2803.5,230 R105.1@2805,231.5
  Signal Layer 3 w10: v1(1195,320) 1194.74,320.26 1194.74,570.74 1194.13,571.35 1194.13,571.87 1187,579 1187,647 v1(1210,670)
  Signal Layer 4 w10: v1@1195,319 1793,319 1829,355 1855.48,355 1861.35,360.87 1878.65,360.87 1883.77,355.75 1979.98,355.75 1983.05,358.82 2000.34,358.82 2007.04,352.13 2584.48,352.13 2587.35,355 v1(2705,355)
DRL_NTC: C126.1 R141.1 R143.2 U10.20 | length 3798.1
  Top Layer w10: R141.1@758.5,85 758.5,6.5 775,-10 3290,-10 v1(3298,-2)
  Top Layer w20: v1(3320,885) C126.1@3320,905
  Top Layer w25: R141.1@758.5,85 R143.2@758.5,150
  Signal Layer 3 w7: v1(3298,-2) 3298,2 3290,10 3290,675 3320,705 v1(3320,885)
  Bottom Layer w7: U10.20@3245.12,750 3245.12,837.72 3292.4,885 v1(3320,885)
DRLPOS: D13.2 D18.2 EC1.5 EC1.6 Q6.5 Q6.6 Q6.7 Q6.8 Q6.9@110.67,1700
  other v2: 40,1700 40,1745 95,1745 40,1790 40,1840
  other v3: 94.72,1700 144.92,1700
DRLPOS+: C28.1 C29.1 C134.1 L9.1 R19.2 R21.2 R27.2 | length 3136.5
  Top Layer w10: C134.1@816.5,1280 v1(855,1280)
  Signal Layer 4 w50: v2(240,1205) 535,1205 ; v2(240,1205) 535,1205 ; v2(240,1205) 535,1205 ; v2(240,1205) 535,1205 ; 535,1205 610,1280 1200,1280 1265,1345 ; 1265,1345 1265,1520 1265,1345 ; 1265,1345 1265,1540 ; 1265,1345 1265,1540 ; 1265,1345 1265,1540 ; 1265,1345 1265,1540
  other v2: 210,1205 210,1230 240,1230 1240,1520 1280,1520 1240,1545 1280,1545
DRLPOS_MICRO: D16.1 R90.1 R114.2 R118.2 U10.104 | length 4438.8
  Top Layer w7: v1(3405,1103) 3508.5,1103 R90.1@3510,1101.5
  Top Layer w10: R90.1@3510,1101.5 v1(3510,1410)
  Top Layer w15: v2(1010,1560) 1030.53,1539.47 D16.1@1030.53,1505
  Signal Layer 3 w7: v1(3315,406) 3315,574 3371.1,630.1 3371.1,818.7 3374.37,821.98 3374.37,822.37 3406,854 3406,870.57 3405.75,870.81 3405.75,878.21 3405.13,878.84 3405.13,997.47 3395.63,1006.98 3395.63,1023.02 3406,1033.4 3406,1090 3405,1091 v1(3405,1103)
  Signal Layer 4 w7: v1(2939,372) 3168,372 3202,406 v1(3315,406)
  Signal Layer 4 w10: v2(1010,1560) 1085,1560 1115,1590 1330,1590 1401.13,1518.87 1401.13,1517.28 1428.4,1490 1835,1490 1870,1525 2254.24,1525 2255.11,1525.87 2256.76,1525.87 2258.21,1527.33 2729.67,1527.33 2817,1440 2885,1440 2915,1410 v1(3510,1410)
  Bottom Layer w7: U10.104@2886.85,331.14 2926.14,331.14 2939,344 v1(2939,372)
  Bottom Layer w15: R118.2@982.5,1640 982.5,1571 R114.2@971.5,1560 v2(1010,1560)
DRLPOS_NTC: C88.1 EC1.20 R143.1 | length 1701.7
  Top Layer w25: R143.1@821.5,150 v2(821.5,183.43) C88.1@821.5,216.85
  Signal Layer 4 w10: v2(-3.99,1012.99) 109.01,1012.99 229,893 229,412 491,150 788.07,150 v2(821.5,183.43)
  Bottom Layer w20: EC1.20@-160.24,1012.99 v2(-3.99,1012.99)
DRLPOS_RBIN: C87.1 EC1.18 R142.1 | length 1656.6
  Signal Layer 4 w10: v2(14,1112) 67,1112 273,906 273,483 391,365 565,365 580,350 710,350 745,385 v2(851.02,385)
  Bottom Layer w20: EC1.18@-160.24,1112.99 13.01,1112.99 v2(14,1112) ; C87.1@821.5,385 v2(851.02,385) R142.1@888.5,385
DRLPOSPWM: R17.1 R90.2 R92.2 R107.2 U1.4 | length 2711.2
  Top Layer w8: v1(2385,1905) 2385,1895 2414.84,1865.16 U1.4@2414.84,1819.49
  Top Layer w10: R90.2@3510,1038.5 R92.2@3510,963 3604.5,963 R107.2@3605,963.5
  Signal Layer 3 w8: v1(3555,963) 3559.5,963 3585,988.5 3585,1415 3540,1460 3540,1670 3670,1800 v1(3670,1955)
  Signal Layer 4 w8: v1(2385,1905) 2445,1965 3025,1965 3045,1985 3235,1985 3265,1955 v1(3670,1955)
  Bottom Layer w8: v1@2386,1906 R17.1@2386,1938.5
EN0RXI_N: U10.53
EN0RXI_P: U10.54
EN0TXO_N: U10.56
EN0TXO_P: U10.57
FB1: C13.2 R3.1 R10.2 U1.25 | length 240
  Top Layer w10: U1.25@2499.49,1656.1 2522.99,1656.1 2531.76,1647.34 C13.2@2531.76,1555.24 R10.2@2587.76,1555.24 R3.1@2643.76,1555.24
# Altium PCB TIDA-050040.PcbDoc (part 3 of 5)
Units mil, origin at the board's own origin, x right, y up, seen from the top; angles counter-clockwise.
Board outline 4045.79 x 2180 mil, 6 copper layers (Top Layer, Signal Layer 1, Signal Layer 2, Signal Layer 3, Signal Layer 4, Bottom Layer), stack 61.485 mil thick; 343 components, 188 nets, 986 pads, 710 vias.

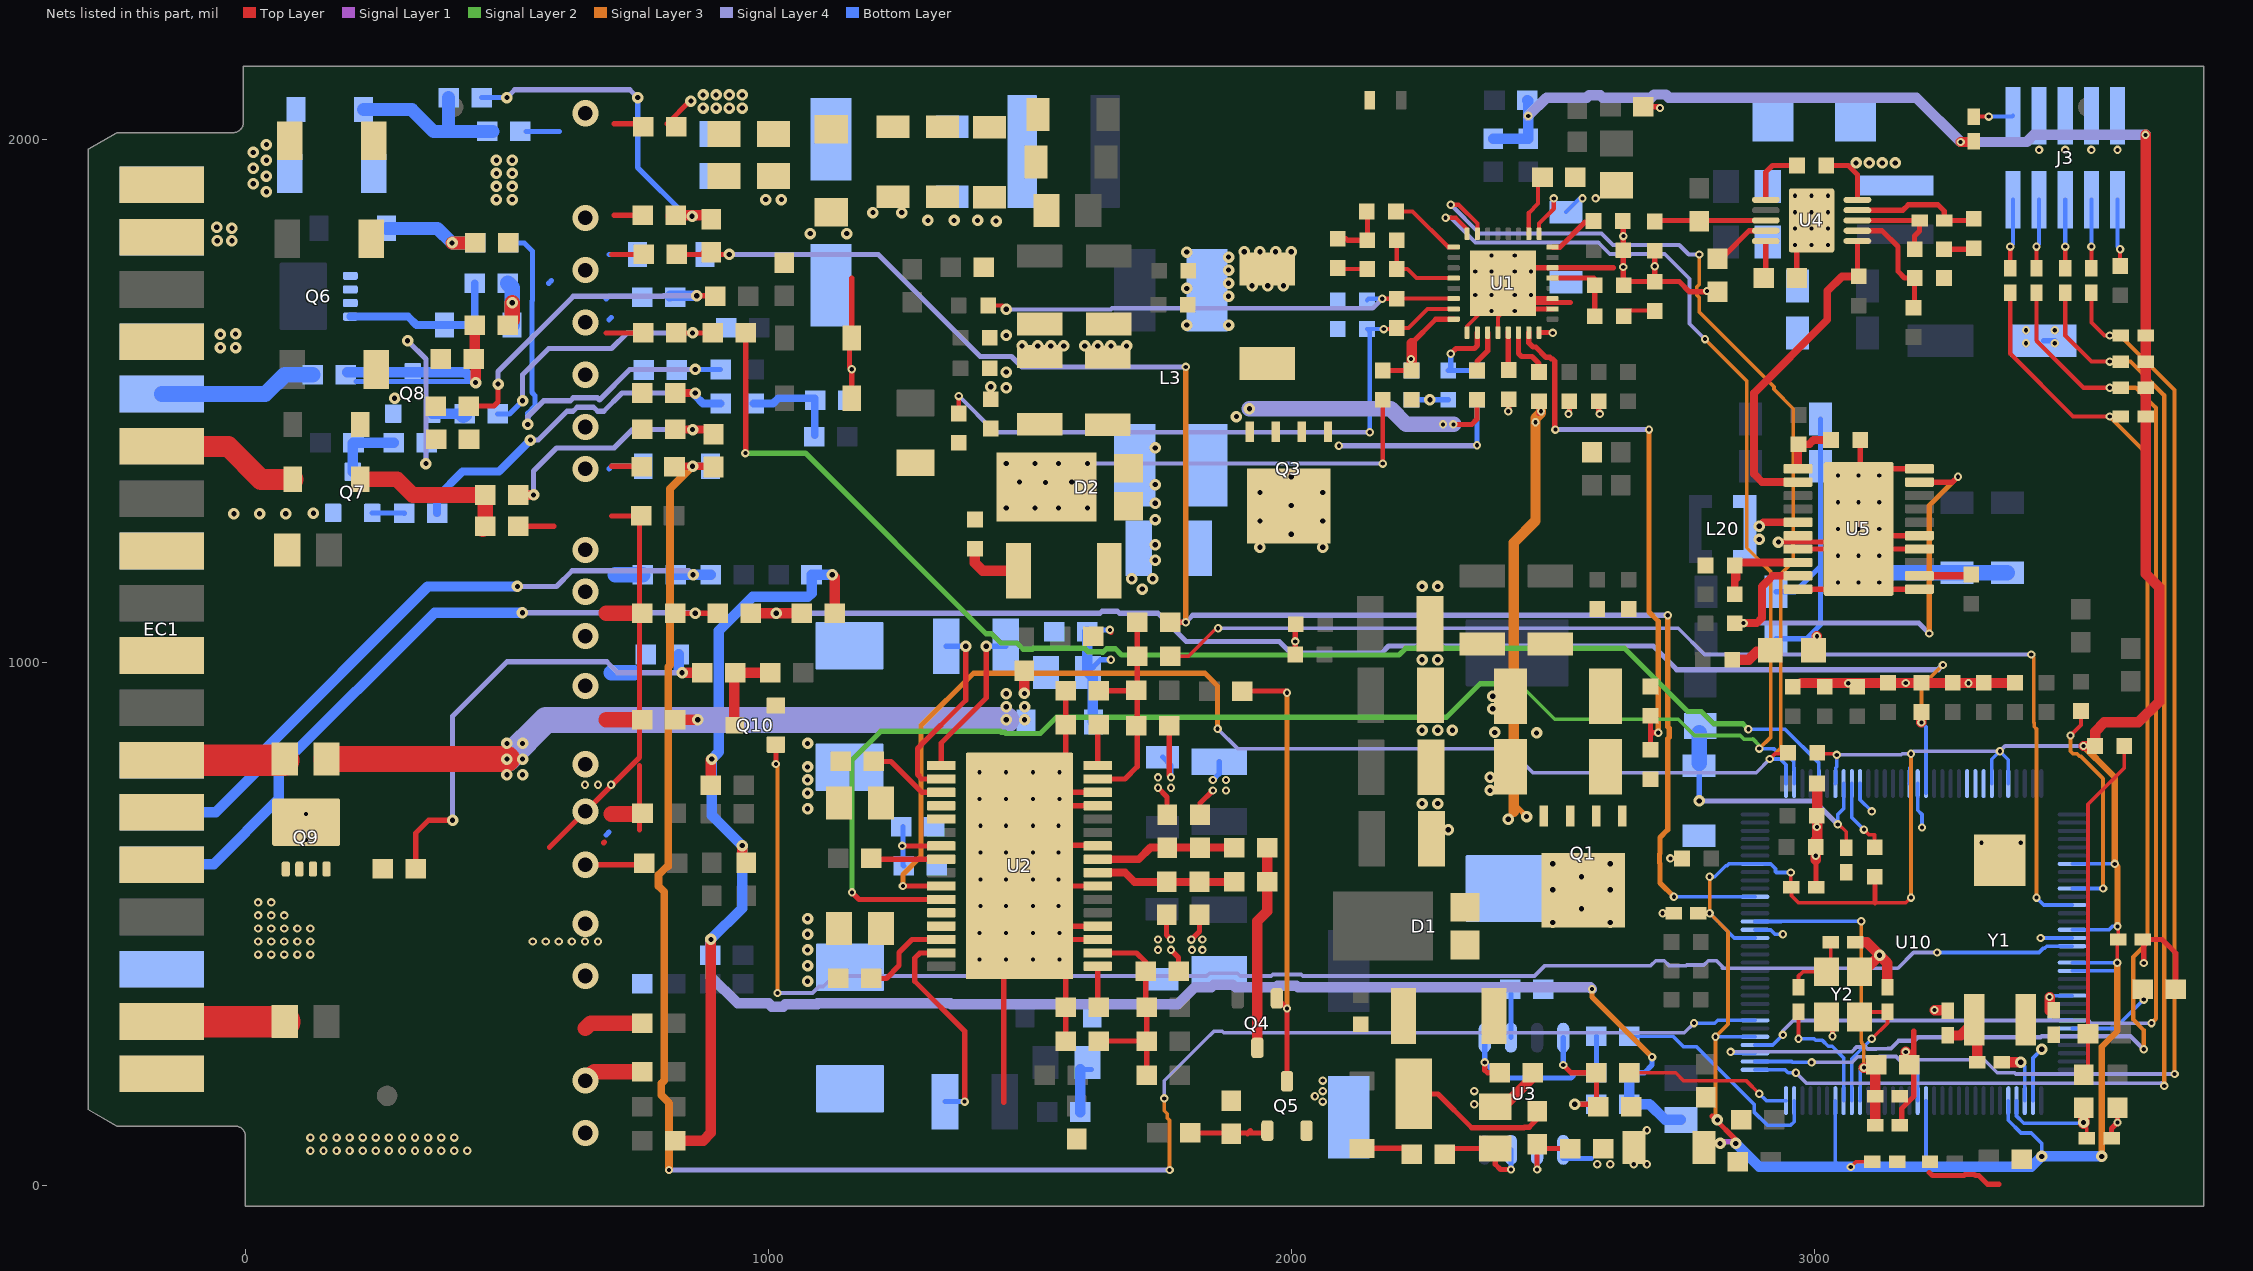
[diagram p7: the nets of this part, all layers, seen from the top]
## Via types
v1: diameter 16, hole 8, Top Layer to Bottom Layer, tented both sides, 318 vias
v2: diameter 22, hole 10, Top Layer to Bottom Layer, tented both sides, 299 vias
v3: diameter 19.68, hole 7.87, Top Layer to Bottom Layer, 47 vias
v4: diameter 19.68, hole 7.87, Top Layer to Bottom Layer, tented both sides, 28 vias
v5: diameter 50, hole 28, Top Layer to Bottom Layer, 18 vias

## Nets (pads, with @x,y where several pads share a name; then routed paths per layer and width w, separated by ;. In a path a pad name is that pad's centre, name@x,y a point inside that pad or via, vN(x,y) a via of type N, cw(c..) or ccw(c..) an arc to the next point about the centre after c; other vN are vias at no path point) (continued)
GND: C2.1 C3.1 C4.2 C5.2 C6.2 C7.2 C8.2 C9.2 C10.1 C11.2 C12.1 C13.1 C14.2 C15.1 C16.2 C17.2 C19.1 C20.2 C21.2 C22.2 C23.2 C24.2 C25.2 C26.2 C27.2 C28.2 C29.2 C31.2 C32.2 C34.1 C35.2 C36.2 C37.1 C38.1 C39.1 C40.2 C41.2 C42.2 C43.1 C44.2 C45.2 C46.2 C47.2 C48.2 C49.2 C51.2 C52.1 C53.1 C54.1 C55.2 C56.2 C57.2 C58.2 C59.2 C61.1 C62.2 C63.1 C64.2 C65.2 C66.2 C67.1 C68.2 C69.2 C70.2 C71.2 C72.2 C73.2 C74.2 C75.2 C76.2 C77.2 C78.2 C79.2 C80.2 C81.1 C82.2 C83.2 C85.2 C86.2 C87.2 C88.2 C89.2 C90.2 C92.2 C93.2 C94.2 C95.2 C96.2 C97.2 C98.2 C99.2 C100.2 C101.2 C102.2 C103.2 C104.2 C105.2 C106.2 C107.2 C108.2 C109.2 C110.2 C111.2 C112.2 C113.2 C114.2 C115.2 C116.2 C117.2 C118.2 C119.2 C120.2 C121.2 C122.2 C123.2 C124.2 C125.2 C126.2 C127.2 C128.2 C129.2 C130.2 C131.2 C132.2 C133.2 C134.2 D3.2 D4.2 D5.1 D8.2 D9.2 D10.2 D11.2 D15.2 D16.2 EC1.3 EC1.4 EC1.7 EC1.8 EC1.16 EC1.19 EC1.24 EC1.27 EC1.32 EC1.35 J3.3 J3.5 J3.7 J3.9 L3.2 Q5.2 Q7.2 Q8.2 Q9.1 Q9.2 Q9.3 Q10.2 R6.1 R7.1 R9.1 R10.1 R13.1 R23.1 R24.1 R29.1 R31.1 R32.1 R37.1 R39.1 R41.1 R47.1 R50.1 R53.1 R57.1 R58.1 R59.1 R60.1 R72.1 R76.1 R77.1 R78.1 R98.2 R101.2 R115.1 R116.1 R117.1 R118.1 RT1.1 U1.17 U1.20 U1.24 U1.26 U1.27 U1.30 U1.33 U2.3 U2.4 U2.7 U2.10 U2.13 U2.14 U2.33@1480.2,610.59 U3.5 U4.9 U4.11@2995,1845 U5.6 U5.7 U5.10 U5.11 U5.14 U5.15 U5.20 U5.21@3085,1255 U10.10 U10.17 U10.48 U10.55 U10.58 U10.80 U10.114 Y1.3 Y2.2 Y2.4 | length 11348.9
  Top Layer w7: U1.17@2336.1,1630.51 2336.1,1642.49 U1.33@2405,1711.39 ; U1.20@2395.16,1630.51 2395.16,1660.16 2405,1670 U1.33@2405,1711.39 ; U1.33@2405,1725 U1.33@2405,1711.39
  Top Layer w10: EC1.19@-160.79,998.99 EC1.19@-160.79,1012.99 ; R59.1@521.5,1260 590,1260 ; 581.5,646.28 753.5,818.28 753.5,1280 700,1280 ; v5(650,612.99) C65.2@753.5,612.99 ; 685,655 686.61,656.61 ; 690,1630 C49.2@753.5,1630 ; 700,1375 R60.1@753.5,1375 ; 700,1780 R58.1@748.5,1780 ; 705,2030 C68.2@743.5,2030 ; 705.34,1855 C17.2@748.5,1855 ; 753.5,679.58 753.5,801.99 ; D16.2@1159.47,1505 v1(1159.47,1560.53) 1155,1565 1155,1615.53 D15.2@1159.47,1620 1159.47,1734.47 1160,1735 ; 1450.21,157.99 U2.33@1450.21,591.36 ; v3(1505.79,585) 1568.7,522.09 U2.33@1568.7,501.3 ; U2.33@1505.98,534.02 1480.2,559.8 U2.33@1480.2,589.8 ; U2.33@1509.07,684.07 U2.33@1560.26,735.26 ; U2.33@1557.16,482.83 U2.33@1568.7,471.3 ; U2.33@1560,590 U2.33@1539.41,610.59 ; C51.2@1568.7,275.59 C48.2@1568.7,340.59 U2.33@1568.7,471.3 ; U2.33@1568.7,482.64 U2.33@1568.7,501.3 ; C61.1@1568.7,945.59 C62.2@1568.7,880.59 U2.33@1568.7,743.7 ; U2.3@1629.8,469.84 1570.16,469.84 U2.33@1568.7,471.3 ; U2.4@1629.8,495.43 1574.57,495.43 U2.33@1568.7,501.3 ; U2.7@1629.8,572.2 1577.79,572.2 U2.33@1539.41,610.59 ; U2.10@1629.8,648.98 1628.78,650 U2.33@1519.61,650 ; U2.13@1629.8,725.75 1580.75,725.75 U2.33@1568.7,713.7 ; U2.14@1629.8,751.34 1576.34,751.34 U2.33@1568.7,743.7 ; v1(1653,1062) 1653,1058.99 v1@1654.99,1057 ; v1(1745,760) 1762.37,742.63 C55.2@1762.37,708.27 ; C53.1@1761.56,517.09 1761.56,478.44 v1(1770,470) ; R53.1@1766.5,878.77 1766.5,783.5 v1(1770,780) ; v1(1770,450) 1784.5,435.5 R37.1@1784.5,409.61 ; v1(1808.87,469.77) 1824.37,485.27 C54.1@1824.37,517.28 ; C56.2@1825.37,708.27 1825.37,730.37 v1(1850,755) ; C9.2@2007.61,1014.91 2007.61,1071.91 C10.1@2008.61,1072.91 ; C41.2@2088.5,1810.24 2104.2,1810.24 2107.2,1807.24 C40.2@2145.5,1807.24 2145.5,1860.82 R24.1@2144.08,1862.24 ; U1.33@2394.9,1715.99 2405,1715.99 U1.33@2427.36,1715.79 ; v1@2416,1481 C39.1@2416,1503 ; v3(2427.24,1702.76) 2442.01,1687.99 2533.21,1687.99 ; v3(2427.24,1747.24) 2434.53,1754.53 U1.30@2499.49,1754.53 ; U1.33@2434.53,1695.47 U1.27@2499.49,1695.47 ; U1.33@2454.21,1675.79 U1.26@2499.49,1675.79 ; U1.24@2473.9,1630.51 2499.49,1630.51 v1(2500,1630) ; 2480,1754.53 U1.30@2499.49,1754.53 ; v1(2530,1475) 2531.76,1476.76 C13.1@2531.76,1499.24 ; v1@2587.76,1477.24 R10.1@2587.76,1499.24 ; 2615.47,1754.53 U1.30@2499.49,1754.53 ; R31.1@2634.85,1842.24 2634.85,1734.29 2636.2,1732.94 2641.14,1728 C14.2@2695,1728 ; R7.1@2673.35,2062.24 v1@2702.76,2062.24 ; R76.1@2695,1787 C14.2@2695,1728 ; v1(2710,520) C105.2@2731.38,520 ; v1(2725,625) C132.2@2747,625 ; C103.2@2815,1708.5 2761.5,1708.5 2742,1728 C14.2@2695,1728 ; v2(2931.46,1230) U5.21@3060,1230 ; R78.1@2966.5,1735 2966.5,1816.5 U4.11@2995,1845 ; U5.10@2968.86,1139.84 3039.84,1139.84 3085,1185 U5.21@3085,1192.01 ; U5.7@2968.86,1216.61 3046.61,1216.61 U5.21@3060,1230 ; 3003,622 3003.62,621.38 C106.2@3003.62,570 ; Y2.2@3023.5,321.69 3035,310.2 v1(3035,285) ; U4.9@3082.6,1864.69 3169.68,1864.69 3180,1875 3236.65,1875 3248.62,1863.03 C102.2@3248.62,1845 3302,1845 C104.2@3305,1848 ; U5.21@3088,1306.18 3088,1258 v3(3085,1255) ; C99.2@3088,1425 3088,1313 3145.16,1370.16 U5.20@3201.14,1370.16 ; C113.2@3167.21,115 3167.21,146.99 3190.21,169.99 3190.21,295.21 ; U5.11@3201.14,1139.84 3137.17,1139.84 v4(3124.37,1152.64) U5.21@3085,1192.01 ; U5.14@3201.14,1216.61 3123.39,1216.61 U5.21@3097.8,1242.2 ; U5.15@3201.14,1242.2 U5.21@3097.8,1242.2 ; 3220,24.5 3226.08,18.42 3286.17,18.42 3288.06,20.32 3289.7,20.32 ; 3289.73,20.34 3306.57,20.34 3308.49,18.43 3314.74,18.43 3331.16,2 3353,2 ; v1(3320,655) Y1.3@3355,655 ; C115.2@3568.62,90 3568.62,108.62 v1(3580,120) R98.2@3580,148.5 ; C107.2@3628.62,470 3665,470 3691.5,443.5 R101.2@3691.5,375 ; v1(3630,425) C107.2@3630,468.62 ; U2.33@1480.2,589.8 U2.33@1480.2,610.59 ; U2.33@1480.2,589.8 U2.33@1568.7,501.3 ; U2.33@1480.2,610.59 U2.33@1539.41,610.59 ; U2.33@1480.2,610.59 U2.33@1519.61,650 ; U2.33@1519.61,650 1568.7,699.09 U2.33@1568.7,713.7 ; U2.33@1568.7,713.7 U2.33@1568.7,743.7 ; U5.21@3060,1230 v3(3085,1255) ; U5.21@3085,1192.01 v3(3085,1203.82) v3(3085,1255) ; v3(3085,1255) U5.21@3097.8,1242.2
  Top Layer w20: C67.1@2390,150 2405,150 2461.5,206.5 C83.2@2461.5,215 ; 2975,960.45 3035,960.45 ; 3003,622 v1(3003,630) C130.2@3003,660 ; D10.2@3005,1023.66 v1(3005,1050) ; 3005.4,662.4 C128.2@3005.4,768.15 ; C122.2@3078.62,465 3100,465 v2(3125,440) ; Y2.4@3086.5,408.31 3093.31,408.31 v2(3125,440) ; C123.2@3140,378.62 3140,425 v2(3125,440) ; v1(3175,255) 3175,236.5 C111.2@3180,231.5 ; v1(3175,960.45) 3035,960.45 ; v1(3230,335) C120.2@3253.62,335 ; C127.2@3379.45,960.45 3035,960.45 ; C121.2@3450,333.62 v1(3450,360)
  Top Layer w30: v5(650,200) 666.85,216.85 C88.2@758.5,216.85 ; 650,300 660,310 C133.2@758.5,310 ; 690,890 C86.2@758.5,890 ; 690.46,1093.7 C85.2@758.5,1093.7 ; 700,710 C57.2@755,710
  Bottom Layer w7: U10.114@2886.85,488.62 2887.29,488.19 2916.81,488.19 2925,480 v1(2940,480) ; U10.10@3087.64,768.15 3087.64,737.36 v1(3110,715) ; v1(3175,255) 3185,255 3197.87,242.13 U10.80@3197.87,161.85 ; U10.17@3197.87,768.15 3197.87,717.13 3206,709 v1(3206,684) ; v1(3432.87,472.87) U10.48@3493.15,472.87 ; U10.58@3493.15,315.39 3454.61,315.39 3450,320 v1(3450,360) 3452.64,362.64 U10.55@3493.15,362.64
  Bottom Layer w10: R57.1@536.5,2015 600,2015 ; 580,1725 585,1730 ; 690,670 695.31,675.31 ; 690,1695 695,1700 C31.2@748.5,1700 ; 695,1370 700,1375 D9.2@760.53,1375 ; 695,1655 699.43,1659.43 ; 695,1780 D8.2@749.96,1780 ; C44.2@1596.5,221.5 C44.2@1617.49,221.5 ; C64.2@1611,980.77 1635.23,1005 v1(1655,1005) ; C63.1@1613.27,1055 1620.27,1062 v1(1653,1062) ; C43.1@1754,818.7 1770,802.7 v1(1770,780) ; v1(1850,775) 1862,787 C59.2@1862,809.86 ; C34.1@2230,1502 C37.1@2300,1502 ; U3.5@2520,50.99 2574.01,50.99 ; C95.2@2926.93,1045 2985,1045 ; C94.2@2926.93,1135 2963.13,1135 3011.93,1183.8 ; v1(3005,1050) 3000,1045 2985,1045 ; C89.2@3011.93,1465 C90.2@3011.93,1375 3011.93,1183.8 ; C96.2@3438.42,1615 3460,1615 v1(3460,1610) ; 2985,1045 3011.93,1071.93 3011.93,1183.8
  Bottom Layer w20: C46.2@1596.5,140 C44.2@1596.5,221.5 ; C63.1@1609.5,1058.77 1609.5,982.28 C64.2@1611,980.77 1620,971.77 1620,887.24 D4.2@1621.47,885.77
  Bottom Layer w30: 700,980 743.5,980 ; 707.27,1167.27 C74.2@759.5,1167.27 ; v4(3124.37,1152.64) 3143.13,1171.39 C100.2@3273.21,1171.39 C101.2@3369.21,1171.39
  other v1: 2585,40 2610,40 2655,40 2680,40 124.21,65.99 149.21,65.99 174.21,65.99 199.21,65.99 224.21,65.99 249.21,65.99 274.21,65.99 299.21,65.99 324.21,65.99 349.21,65.99 374.21,65.99 399.21,65.99 424.21,65.99 124.21,90.99 149.21,90.99 174.21,90.99 199.21,90.99 224.21,90.99 249.21,90.99 274.21,90.99 299.21,90.99 324.21,90.99 349.21,90.99 374.21,90.99 399.21,90.99 2680,105 2350,155 2060,160 2045,170 2060,180 2350,180 2060,200 24.21,440.99 49.21,440.99 74.21,440.99 99.21,440.99 124.21,440.99 1745,450 1810,450 1830,450 24.21,465.99 49.21,465.99 74.21,465.99 99.21,465.99 124.21,465.99 549.21,465.99 574.21,465.99 599.21,465.99 624.21,465.99 649.21,465.99 674.21,465.99 1745,470 1830,470 24.21,490.99 49.21,490.99 74.21,490.99 99.21,490.99 124.21,490.99 24.21,515.99 49.21,515.99 74.21,515.99 24.21,540.99 49.21,540.99 3395,655 3005,685 1875,755 1770,760 649.21,765.99 674.21,765.99 699.21,765.99 1875,775 1745,780 3065,960 3295,960 2007.61,1040 2590,1475 2415,1480 3405,1610 3405,1635 3460,1635 2795,1710 2634.85,1756 2695,1757.5 2635,1815 3430,1980 3480,1980 3530,1980 3580,1980 2705,2060
  other v2: 2300,680 2250,730 2280,730 2380,755 2380,780 2469,865 2389,866 2250,870 2280,870 2308,870 2385,911 2385,935 2250,1005 2280,1005 2250,1145 2280,1145 -22,1284 27,1284 77,1284 130,1285 2265,1502 285,1505 1455,1525 1425,1527.17 1455,1555 -48,1602 -19,1602 1485,1605 1515,1605 1540,1605 1565,1605 1605,1605 1630,1605 1655,1605 1685,1605 1455,1625 -48,1627 -19,1628 1800,1645 1880,1645 1880,1700 1800,1715 1925,1720 1955,1720 1985,1720 1880,1725 1880,1750 1880,1775 1800,1784.53 1910,1785 1940,1785 1970,1785 2000,1785 -54,1806 -26,1806 1080,1820 1150,1820 -26,1830 -55,1832 1435.46,1843.92 1305,1845 1355,1845 1400,1845 1200,1860 1255,1860 995,1885 1025,1885
  other v3: 1405.39,533.82 1454.61,533.82 1505.79,533.82 1555,533.82 1405.39,585 1454.61,585 1555,585 1405.39,636.18 1454.61,636.18 1505.79,636.18 1555,636.18 1405.39,687.36 1454.61,687.36 1505.79,687.36 1555,687.36 3045.63,1203.82 3124.37,1203.82 3045.63,1255 3124.37,1255 3045.63,1306.18 3085,1306.18 3124.37,1306.18 2382.76,1671.85 2427.24,1671.85 2351.85,1702.76 2382.76,1702.76 2458.15,1702.76 2351.85,1747.24 2382.76,1747.24 2458.15,1747.24 2382.76,1778.15 2427.24,1778.15 2963.5,1829.25 2995,1829.25 3026.5,1829.25 2963.5,1860.75 2995,1860.75 3026.5,1860.75
  other v4: 1403.42,431.46 1454.61,431.46 1505.79,431.46 1556.97,431.46 1403.42,482.64 1454.61,482.64 1505.79,482.64 1556.97,482.64 1403.42,738.54 1454.61,738.54 1505.79,738.54 1556.97,738.54 1403.42,789.72 1454.61,789.72 1505.79,789.72 1556.97,789.72 3045.63,1152.64 3085,1152.64 3045.63,1357.36 3085,1357.36 3124.37,1357.36 2963.5,1797.76 2995,1797.76 3026.5,1797.76 2963.5,1892.24 2995,1892.24 3026.5,1892.24
  other v5: 650,100 650,400 650,500 650,715 650,805 650,955 650,1050 650,1135 650,1215 650,1370 650,1450 650,1550 650,1650 650,1750 650,1850 650,2050
HB: D7.2 EC1.11 | length 276.9
  Top Layer w40: EC1.11@-160.24,1412.99 -32.99,1412.99 30,1350 D7.2@90.53,1350
HB_DRIVE_MICRO: Q10.1 U10.49 | length 3018
  Top Layer w10: Q10.1@1014.37,842.6 v1(1014.37,805.63) v1@1015,805
  Signal Layer 3 w7: v1(1014.37,805.63) 1017.37,802.63 v1(1017.37,367.63)
  Signal Layer 4 w7: v1(1017.37,367.63) 1084.27,367.63 1096.64,380 1105,380 1125,400 1806.77,400 1837.9,400 1843.03,405.12 1856.66,405.12 1896.97,405.12 1901.21,400.88 1902.1,400 1961.66,400 1964.72,403.07 2018.67,403.07 2021.74,400 2465,400 2485,420 2687.6,420 2696.98,429.37 2713.03,429.37 2722.4,420 2755,420 2756.2,421.2 2789.04,421.2 2797.09,429.26 2813.14,429.26 2824.49,417.91 2824.49,415 3160,415 3190,445 v1(3235,445)
  Bottom Layer w7: v1(3235,445) 3430,445 3438.5,453.5 3440.9,453.5 3444.53,457.13 U10.49@3493.15,457.13
HB_LED: EC1.25 Q9.5 Q9.6 Q9.7 Q9.8 Q9.9@116,694.33
  other v3: 116,660.08 116,710.28
HB_MICRO: D9.1 R56.2 R60.2 U10.103 | length 3813.5
  Top Layer w15: R60.2@816.5,1375 v2(855,1375) 893.5,1375 R56.2@895,1373.5
  Signal Layer 3 w7: v1(1757,166) 1757,142.41 1762.88,136.53 1762.88,128.5 1767.19,124.19 v1(1767.19,29.19)
  Signal Layer 3 w15: v1(809.81,29.19) 809.81,157.81 795.12,172.5 795.12,194.35 800.98,200.2 800.98,560.98 790.12,571.83 790.12,593.68 805.57,609.13 808.63,609.13 808.63,990.92 812,994.3 812,1332 v2(855,1375)
  Signal Layer 4 w7: v1(1757,166) 1757,199.78 1844.22,287 1844.6,287 1851.97,294.37 1868.02,294.37 1871.02,291.37 2751.37,291.37 v1(2770,310)
  Signal Layer 4 w10: v1(809.81,29.19) v1(1767.19,29.19)
  Bottom Layer w7: v1(2770,310) 2810,310 2815.39,315.39 U10.103@2886.85,315.39
  Bottom Layer w15: v2(855,1375) D9.1@889.47,1375
JTAG_TCK: R82.1 R86.2 U10.100 | length 2358.4
  Top Layer w8: R86.2@3425,1706.38 3425,1615 3515,1525 R82.1@3586.38,1525
  Signal Layer 3 w8: v1(3565,1525) 3615,1525 3653.34,1486.66 3653.34,318.34 v1(3645,310)
  Signal Layer 4 w7: v1(2940,287.5) 2940,295 2960,315 3525,315 3530,310 v1(3645,310)
  Bottom Layer w7: U10.100@2886.85,268.15 2920.65,268.15 v1(2940,287.5)
JTAG_TDI: R84.1 R88.2 U10.98 | length 2421.5
  Top Layer w8: R88.2@3530,1706.38 3530,1650 3555,1625 R84.1@3586.38,1625
  Signal Layer 3 w8: v1(3565,1625) 3585,1625 3689.21,1520.79 v1@3689.21,215
  Signal Layer 4 w7: v1(2995,235) 3072.6,235 3083.35,245.75 3124.19,245.75 3124.63,246.2 3156.4,246.2 3166.98,235.63 3183.02,235.63 3187.4,240 3325,240 3350,215 3383.36,215 3385.73,212.63 v1(3689.21,212.63)
  Bottom Layer w7: U10.98@2886.85,236.65 2956.65,236.65 2958.31,235 v1(2995,235)
JTAG_TDO: R83.1 R87.2 U10.97 | length 2455.2
  Top Layer w8: R87.2@3480,1706.38 3480,1625 3530,1575 R83.1@3586.38,1575
  Signal Layer 3 w8: v1(3565,1575) 3605,1575 3669.21,1510.79 v1(3669.21,190)
  Signal Layer 4 w7: v1(2965,215) 2985,195 3640,195 v1@3664.21,195
  Signal Layer 4 w8: v1@3664.21,195 v1(3669.21,190)
  Bottom Layer w7: U10.97@2886.85,220.91 2944.09,220.91 2950,215 v1(2965,215)
JTAG_TMS: R81.1 R85.2 U10.99 | length 2500.6
  Top Layer w8: R85.2@3375,1706.38 3375,1590 3495,1470 R81.1@3586.38,1470
  Signal Layer 3 w8: v1(3565,1470) 3637.46,1397.54 3637.46,463.84 3610,436.38 3610,316.89 3630,296.89 v1(3630,260)
  Signal Layer 4 w7: v1(2840,255) 3071.57,255 3080.81,264.25 3098.35,264.25 3101.98,260.63 3118.03,260.63 3118.47,261.07 3141.16,261.07
  Signal Layer 4 w8: 3141.16,261.57 3146.57,261.57 3161.2,276.2 3191.2,276.2 3197.88,282.87 3432.87,282.87 3435,285 3605,285 v1(3630,260)
  Bottom Layer w7: v1(2840,255) 2842.6,252.4 U10.99@2886.85,252.4
LB1/LB2: D6.2 D19.2 D20.2 EC1.1 EC1.2
  other v2: 40,1900 15,1915 40,1930 15,1945 40,1960 15,1975 40,1990
LB_FAULT: EC1.10 R127.1 | length 304.1
  Bottom Layer w30: EC1.10@-160.24,1512.99 37.99,1512.99 75,1550 R127.1@128.5,1550
LB_FAULT_MICRO: R129.2 U10.5 | length 2591.3
  Top Layer w10: v1(956,1400) 956.5,1400.5 R129.2@956.5,1630
  Signal Layer 2 w10: v1(956,1400) 1071,1400 1416.35,1054.65 1426.57,1054.65 1444.22,1037 1475.48,1037 1487.35,1025.13 1504.65,1025.13 1506.26,1026.74 1605.1,1026.74 1611.42,1020.42 1637.01,1020.42 1638.19,1019.25 1639.73,1019.25 1646.35,1025.87 1663.65,1025.87 1675.52,1014 2206,1014 2219,1027 2238.24,1027 2240.11,1028.87 2259.89,1028.87 2261.76,1027 2268.24,1027 2270.11,1028.87 2289.89,1028.87 2291.76,1027 2637,1027 2758,906 2783.84,906 2807.22,882.63 2863.37,882.63 v1(2874,872) v1@2876,870
  Bottom Layer w7: v1(2874,872) 2944.24,872 3008.9,807.34 U10.5@3008.9,768.15
LB_MICRO: D8.1 R28.1 R54.2 R58.2 U10.118 | length 3278.9
  Top Layer w10: R58.2@811.5,1780 871.5,1780 ; R54.2@875,1783.5 878.5,1780 v2(925,1780) ; R28.1@1768.5,1076.77 v1(1798.23,1076.77)
  Signal Layer 3 w10: v1(1798.23,1076.77) v1(1798.23,1565) ; v1(2720,1090) 2720,876.52 2722.69,873.83 2722.69,856.54 2720,853.85 2720,680 2705,665 2705,634.52 2704.13,633.65 2704.13,616.35 2705,615.48 2705,578.23 v1(2731.61,551.61)
  Signal Layer 4 w10: v2(925,1780) 1210,1780 1405,1585 1465,1585 1485,1565 v1(1798.23,1565) ; v1(1798.23,1076.77) 1811.46,1090 v1(2720,1090)
  Bottom Layer w7: v1(2731.61,551.61) U10.118@2886.85,551.61
  Bottom Layer w10: D8.1@878.9,1780 v2(925,1780)
LB_NTC: C124.1 R136.1 R139.2 U10.18 | length 2673.1
  Top Layer w20: R139.2@966.5,1093.7 v2(1015,1093.7) R136.1@1060.57,1093.7 ; v1(3205,885) C124.1@3205,905
  Signal Layer 3 w7: v1(3205,885) 3205,954 v1(3246,995)
  Signal Layer 4 w10: v2(1015,1093.7) 1548.54,1093.7 1634.14,1093.7 1638.19,1097.75 1667.81,1097.75 1671.86,1093.7 1738.46,1093.7 1745.3,1093.7 1799,1040 1977,1040 1999,1018 2173,1018 2186,1031 2692,1031 2737.01,985.99 3236.99,985.99 v1(3246,995)
  Bottom Layer w7: v1(3205,885) 3213.62,876.38 U10.18@3213.62,750
LBHB+: C63.2 C64.1 C86.1 D4.1 L2.1 R40.2 R52.1 U2.17 | length 4651.2
  Top Layer w10: U2.17@1330.59,802.52 1330.59,845.59 1416.68,931.68 v2(1416.68,1030.77)
  Top Layer w20: C86.1@821.5,890 v2(865,890) ; v2(1489.52,940.48) R40.2@1489.52,983.5
  Top Layer w50: L2.1@155,815 v2(500,815) ; L2.1@155,815 v2(500,815) ; L2.1@155,815 v2(500,815) ; L2.1@155,815 v2(500,815)
  Signal Layer 4 w50: v2(500,815) v2(530,845) ; v2(500,815) v2(530,845) ; v2(500,815) v2(530,845) ; v2(500,815) 575,890 v2(1455,890) ; v2(865,890) v2(1455,890) ; v2(865,890) v2(1455,890) ; v2(865,890) v2(1455,890)
  Bottom Layer w10: v2(1416.68,1030.77) R52.1@1454.09,1030.77
  other v2: 500,785 530,785 530,815 500,845 1490,890 1455,915 1490,915 1455,940
LBHB_NTC: C85.1 EC1.28 R139.1 | length 1327.4
  Top Layer w10: C85.1@821.5,1093.7 v2(860,1093.7) R139.1@903.5,1093.7
  Signal Layer 4 w10: v2(529.58,1094.58) 859.12,1094.58 v2(860,1093.7)
  Bottom Layer w20: EC1.28@-152,614 -61,614 64,739 64,797 361.58,1094.58 v2(529.58,1094.58)
LBHB_RBIN: C74.1 EC1.26 R138.1 | length 1293
  Signal Layer 4 w10: v2(520,1145) 595,1145 625,1175 848.27,1175 v2(856,1167.27)
  Bottom Layer w20: EC1.26@-160.24,712.99 -57.01,712.99 17,787 17,813 349,1145 v2(520,1145) ; C74.1@822.5,1167.27 v2(856,1167.27) R138.1@889.5,1167.27
LBHBPWM: R51.1 U10.44 | length 2232.4
  Top Layer w7: R51.1@1768.5,1011.77 1803.23,1011.77 1856.46,1065 v1(1860,1065)
  Signal Layer 3 w7: v1(3415,1015) 3420,1010 3420,885 3420.63,884.37 3420.63,876.98 3425,872.6 v1(3425,550)
  Signal Layer 4 w7: v1(1860,1065) 2740,1065 2790,1015 v1(3415,1015)
  Bottom Layer w7: v1(3425,550) 3439.13,535.87 U10.44@3493.15,535.87
LHI_1-2: C58.1 R47.2 U2.23 | length 370.7
  Top Layer w10: v1(1256.02,648.98) U2.23@1330.59,648.98
  Bottom Layer w10: C58.1@1258.7,610.59 C58.1@1257.2,612.09 ; C58.1@1257.2,612.09 R47.2@1257.2,685.59 ; C58.1@1257.2,612.09 R47.2@1257.2,685.59 ; C58.1@1257.2,612.09 R47.2@1257.2,685.59 ; C58.1@1257.2,612.09 R47.2@1257.2,685.59
LIN_RXD: R64.1 U10.95 | length 437.3
  Bottom Layer w7: R64.1@2646.5,285 2730,285 2750,265 2775,265 2885,155 2885,140 2910,115 2955,115 2961.65,121.65 U10.95@2961.65,161.85
LIN_TXD: R100.1 U10.96 | length 321.4
  Top Layer w7: R100.1@2646.5,215 2735,215 2750.45,199.55 2870.45,199.55 v1(2895,175)
  Bottom Layer w7: v1(2895,175) 2908.15,161.85 U10.96@2945.9,161.85
MCU_3V3A: C109.1 C114.1 L23.2 U10.8 | length 548.6
  Top Layer w7: v1(3045,690) 3047.08,690 3061,676.08 C109.1@3061,645.62
  Signal Layer 4 w10: v2(2780,735) 3000,735 v1(3045,690)
  Bottom Layer w7: v1(3045,690) 3045,708.92 3056.14,720.06 U10.8@3056.14,768.15
  Bottom Layer w10: v2(2780,735) C114.1@2780,806.93
  Bottom Layer w30: C114.1@2780,806.93 L23.2@2780,865
MCU_3V3D: C105.1 C106.1 C107.1 C108.1 C110.1 L22.2 R16.2 R17.2 R20.2 R61.2 R62.2 R66.1 R80.2 R81.2 R82.2 R83.2 R84.2 R93.2 R94.1 R96.1 R99.1 R102.2 R103.2 R105.2 R130.2 R131.2 R135.2 R136.2 R140.2 R141.2 U10.7 U10.16 U10.26 U10.28 U10.39 U10.47 U10.51 U10.52 U10.69 U10.79 U10.90 U10.101 U10.113 U10.122 | length 11262.1
  Top Layer w7: v1(2955,598) 2955,571.38 C106.1@2956.38,570 2956.38,553.62 2970,540 3095,540 3175,540 v1(3185,550) ; R93.2@3003,825 v1@3045,825 ; v1@3043,818 v1(3043,823) ; v1(3070,35) 3080,45 C108.1@3111.38,45 ; v1(3579.37,425.63) 3579.37,467.99 C107.1@3581.38,470 3581.38,493.62 v1(3580,495)
  Top Layer w10: 2805,131.98 v2@2853.98,82.99 ; 3116.02,540.02 R94.1@3116.02,590.18
  Top Layer w20: R141.2@821.5,85 875,85 890.16,100.16 v2(890.16,470) ; R130.2@890,765 v2@890,813.5 ; R131.2@950,615.94 v2(950,649.45) ; v2(1122.27,1167.27) 1126.5,1163.04 R136.2@1126.5,1093.7 ; v1(3280,1995) R80.2@3303.62,1995 ; v1(3515,840) R96.1@3537,840 3537,867 3555,885 3620,885 3660,925 3660,1143.34 3633.62,1169.72 R81.2@3633.62,1470 R82.2@3633.62,1525 R83.2@3633.62,1575 R84.2@3633.62,1625 v1(3633.62,2008.62)
  Signal Layer 1 w10: v2@2822.44,82.99 v2@2853.98,82.99
  Signal Layer 3 w7: v1(2800,590) v1(2800,520) 2835,485 2835,307.8 v1(2811.1,283.9) 2811.1,128.9 v2(2815,125) ; v1(3185,550) v1(3185,825)
  Signal Layer 3 w10: v1(2575,375) 2575,360 v1(2690,245)
  Signal Layer 3 w12: v1(3515,840) 3565,790 3565,789.57 3574.61,779.96 v1(3574.61,614.61) 3580,609.21 v1(3580,495) ; v2(3550,55) 3550,265 3579.37,294.37 v1(3579.37,425.63)
  Signal Layer 4 w7: v1(3043,823) 3166.21,823 3168.21,825 v1(3185,825) 3190,830 v1(3355,830) 3365,840 v1(3515,840)
  Signal Layer 4 w20: v2(890.16,470) 890.16,398.84 941.13,347.87 1000.53,347.87 1006.66,341.75 1028.09,341.75 1032.59,346.25 1093.12,346.25 1094.74,347.87 1347.76,347.87 1349.63,346 1783,346 1815.63,378.63 1846.76,378.63 1851.88,383.75 1888.12,383.75 1893.24,378.63 1970.51,378.63 1973.58,381.69 2009.82,381.69 2012.89,378.63 2571.37,378.63 v1(2575,375) ; v1(2453,2045) 2488,2080 2564.67,2080 2569.28,2084.61 2590.72,2084.61 2595.33,2080 2688.41,2080 2694.28,2085.87 2715.72,2085.87 2721.59,2080 3195,2080 v1(3280,1995) 3406,1995 3419.62,2008.62 v1(3633.62,2008.62)
  Bottom Layer w7: v1(2800,520) 2847.13,472.87 U10.113@2886.85,472.87 ; v1(2800,590) 2810,590 2830.98,610.98 2833.38,610.98 2837,614.61 U10.122@2886.85,614.61 2904.39,614.61 2904.83,614.17 2916.81,614.17 2925.78,605.2 2925.78,600 2927.78,598 v1(2955,598) ; v1(2811.1,283.9) U10.101@2886.85,283.9 ; U10.90@3040.39,161.85 3040.39,45.39 3050.79,35 ; U10.7@3040.39,768.15 3040.83,768.59 3040.83,798.11 ; 3042,799.28 3043,800.28 v1(3043,823) ; U10.16@3182.13,768.15 3182.56,768.59 3182.56,798.11 3185,800.55 v1(3185,825) ; 3213.62,35 U10.79@3213.62,161.85 ; U10.26@3339.61,768.15 3339.61,814.61 v1(3355,830) 3371.1,813.9 U10.28@3371.1,768.15 ; U10.69@3371.1,161.85 3371.1,124.1 3395.2,100 3415,100 3435,80 v2(3435,55) ; U10.52@3493.15,409.88 3579.88,409.88 3579.88,425.12 v1(3579.37,425.63) U10.51@3493.15,425.63 ; U10.47@3493.15,488.62 3563.62,488.62 3570,495 v1(3580,495) ; U10.39@3493.15,614.61 v1(3574.61,614.61)
  Bottom Layer w10: R66.1@2481.5,375 v1(2575,375) ; R62.2@2646.49,215 2675,215 2690,230 v1(2690,245)
  Bottom Layer w20: R140.2@888.5,440 v2@888.5,468.35 ; v2(890.16,470) 950,529.84 v2(950,649.45) 891.5,707.95 v2(891.5,815) 905,828.5 905,1060 970,1125 1075,1125 1082.5,1132.5 R135.2@1082.5,1167.27 v2(1122.27,1167.27) ; R17.2@2386,2001.5 R16.2@2453,2001.5 v1(2453,2045) 2453,2073.5 R20.2@2451.5,2075 ; R62.2@2646.49,215 R61.2@2646.49,155 2685,155 2715,125 L22.2@2745,125 ; v2(2850,80) 2895,35 3050.79,35 v1(3070,35) 3213.62,35 3415,35 v2(3435,55) v2(3550,55)
  other v2: 2820,80
MISOM: R93.1 U1.7 U2.26 U10.1 | length 3967.9
  Top Layer w7: v1(2915,815) 2925,825 R93.1@2947,825
  Top Layer w8: v1(2305,1875) 2320,1875 2355.79,1839.21 U1.7@2355.79,1819.49
  Top Layer w10: v1(1257.2,572.2) U2.26@1330.59,572.2
  Signal Layer 3 w7: v1(2780,1780) 2780,1722.4 2775.63,1718.03 2775.63,1701.98 2780,1697.6 2780,1670 2923,1527 2923,1522 2960,1485 2960,1193 2936,1169 2936,836 v1(2915,815)
  Signal Layer 3 w10: v1(1257.2,572.2) 1257.2,594.2 1292,629 1292,879 1392,979 1835,979 1859,955 v1(1859,873)
  Signal Layer 4 w7: v1(1859,873) 1897,835 2416,835 2462,789 2889,789 v1(2915,815)
  Signal Layer 4 w8: v1(2305,1875) 2360,1820 2593,1820 2615,1798 2623.74,1798 2626.62,1795.13 2626.77,1795.13 2643.23,1795.13 2646.11,1798 2741.89,1798 2753.77,1786.13 2753.87,1786.13 2760,1780 v1(2780,1780)
  Bottom Layer w7: v1(2915,815) 2935,815 2945.9,804.1 U10.1@2945.9,768.15
MOSIM: U1.8 U2.27 U10.2 | length 3947.5
  Top Layer w8: v1(2295,1850) 2315,1850 2336.1,1828.9 U1.8@2336.1,1819.49
  Top Layer w10: v1(1160,560) 1173.39,546.61 U2.27@1330.59,546.61
  Signal Layer 2 w7: 2436.13,958.87 2504,891 2740,891 2771,860 2858.6,860 2865.98,852.63 2882.02,852.63 2882.7,853.3 2895,841 v1(2895,835)
  Signal Layer 2 w10: v1(1160,560) 1160,813 1215,868 1443.24,868 1445.11,866.13 1451.87,866.13 1454,864 1520,864 1551,895 2297,895 2360.87,958.87 2436.13,958.87
  Signal Layer 3 w7: v1@2792,1617 2871,1538 2871,1219 2917.12,1172.88 2917.12,857.12 v1(2895,835)
  Signal Layer 4 w7: 2587,1803 2609,1781 2619,1781 2620.25,1779.75 2620.4,1779.75 2649.6,1779.75 2650.85,1781 2714,1781 2761.5,1733.5 2761.5,1647.5 v1(2791,1618)
  Signal Layer 4 w8: v1(2295,1850) 2305,1850 2352,1803 2587,1803
  Bottom Layer w7: v1(2895,835) 2920.76,835 2921.38,834.37 2923.02,834.37 2927.52,829.87 2941.16,829.87 2960.78,810.26 2960.78,798.55 2961.22,798.11 2961.22,794.54 2961.65,794.1 U10.2@2961.65,768.15
NetC1_1: C1.1 R1.1
NetC12_2: C12.2 R4.1 U1.23 | length 1061.3
  Top Layer w10: U1.23@2454.21,1630.51 2454.21,1610.79 2462.13,1602.87 2467.4,1602.87 2487.07,1583.2 2494.06,1583.2 2497.27,1580 2500,1580 2503.88,1576.12 2503.88,1446.12 v1(2505,1445) ; R4.1@2687,832.68 2687,865.18 ; C12.2@2687,897.68 2687,865.18 ; v1(2701.82,865.18) 2687,865.18
  Signal Layer 3 w10: v1(2684,1445) 2684,1096.48 2701.82,1078.66 v1(2701.82,865.18)
  Signal Layer 4 w10: v1(2505,1445) v1(2684,1445)
NetC14_1: C14.1 R12.2 | length 59.2
  Top Layer w8: R12.2@2636.2,1672.94 2694.05,1672.94 C14.1@2695,1672
NetC15_2: C15.2 R12.1 U1.29 | length 141.5
  Top Layer w10: U1.29@2499.49,1734.84 2578.3,1734.84 2580.2,1732.94 R12.1@2580.2,1672.94
NetC16_1: C16.1 R11.2 R14.2 U1.1 | length 122.1
  Top Layer w8: U1.1@2473.9,1819.49 2473.9,1839.29 2501.85,1867.24 v1(2501.85,1887.24)
  Bottom Layer w8: C16.1@2525,1860.93 2551.32,1887.24 v1(2556.85,1887.24)
  other v1: 2581.85,1887.24
NetC17_1: C17.1 R44.2 R54.1 | length 667.5
  Top Layer w20: C17.1@813.5,1853 C17.1@822.5,1853 ; C17.1@822.5,1855 882.41,1855 R54.1@890.47,1846.93
  Signal Layer 4 w10: v2(500,2080) 515,2095 735,2095 v2(750,2080)
  Bottom Layer w10: R44.2@451.5,2080 v2(500,2080) ; v2(750,2080) 750,1946.46 843.46,1853 v2(854,1853)
NetC18_1: C18.1 R18.1 | length 116.6
  Top Layer w20: C18.1@1395,1217 1395,1190 1410,1175 R18.1@1478.39,1175
NetC18_2: C18.2 C25.1 C26.1 C27.1 D2.3 R19.1 R22.2 R26.2 | length 687
  Top Layer w8: v1(2175,1380) R22.2@2175,1502
  Signal Layer 4 w8: v2(1610,1380) v1(2175,1380)
  other v2: 1455,1295 1510,1295 1555,1295 1610,1295 1529.76,1343.76 1480,1345 1580,1345 1455,1380 1510,1380 1555,1380
NetC24_1: C24.1 R55.2 R56.1 | length 494.3
  Top Layer w15: C24.1@816.5,1445 v2(855,1445) 886.5,1445 R56.1@895,1436.5
  Top Layer w20: R55.2@521.5,1320 v2(551.02,1320)
  Signal Layer 4 w10: v2(551.02,1320) 551.02,1366.02 595,1410 705,1410 740,1445 v2(855,1445)
NetC30_1: C30.1 L3.3 Q3.5
  other v2: 1940,1220 2060,1220 2000,1245 1940,1270 2060,1270 2000,1300 1940,1325 2060,1325 2000,1355
NetC30_2: C30.2 D2.1 D2.2 L3.4 R18.2
  other v2: 1715,1140 1695,1160 1735,1160 1740,1195 1740,1225 1740,1273 1740,1304.22 1740,1340 1740,1410
NetC31_1: C31.1 R111.2 R112.1 | length 645.1
  Top Layer w10: R111.2@427.09,1489.99 474.94,1489.99 483,1498.06 v2(483,1532) ; v2(863,1701) 897.5,1701 R112.1@898.5,1700
  Signal Layer 4 w10: v2(483,1532) 483,1556 627,1700 798.98,1700 799.98,1701 v2(863,1701)
  Bottom Layer w20: C31.1@811.5,1700 812.5,1701 v2(863,1701)
NetC32_1: C32.1 R113.2 R114.1 | length 860.2
  Signal Layer 4 w10: v2(540,1455) 540,1470 570,1500 621.16,1500 626.91,1505.75 673.09,1505.75 676.92,1501.92 735,1560 v2(860,1560)
  Bottom Layer w10: R113.2@502.5,1802 533,1802 549,1786 549,1692 548,1691 548,1515.76 553.87,1509.89 553.87,1490.11 540,1476.24 v2(540,1455) ; C32.1@816.5,1560 v2(860,1560) R114.1@908.5,1560
NetC33_1: C33.1 C35.1 R26.1 U1.15 | length 1228.9
  Top Layer w8: R26.1@1364.15,1475.76 v1(1364.15,1509.15) ; v1(2176.85,1637.24) 2199.85,1637.24 C33.1@2201.85,1639.24 2223.85,1639.24 2260.39,1675.79 U1.15@2310.51,1675.79
  Signal Layer 4 w8: v1(1364.15,1509.15) 1433.3,1440 v1(2150,1440)
  Bottom Layer w8: v1(2150,1440) 2150,1632.09 C35.1@2144.85,1637.24 v1(2176.85,1637.24)
NetC33_2: C33.2 C36.1 R27.1 U1.14 | length 932.1
  Top Layer w8: R27.1@1420.2,1682.44 1447.56,1682.44 v2(1455,1675) ; v1(2173.85,1695.24) C33.2@2201.85,1695.24 2202.08,1695.47 U1.14@2310.51,1695.47
  Signal Layer 4 w8: v2(1455,1675) 1655,1675 1657.13,1677.13 2155.73,1677.13 v1(2173.85,1695.24)
  Bottom Layer w8: C36.1@2144.85,1692.24 2147.85,1695.24 v1(2173.85,1695.24)
NetC34_2: C34.2 R22.1 R29.2 U1.16 | length 229
  Top Layer w10: R22.1@2175,1558 R29.2@2230,1558 ; 2230,1610 2276.1,1656.1 U1.16@2310.51,1656.1
  Top Layer w20: R29.2@2230,1558 2230,1610
  Bottom Layer w10: v1(2229,1580) 2229,1559 C34.2@2230,1558
NetC37_2: C37.2 R30.1 U1.18 | length 171.1
  Top Layer w10: v1(2305,1590) 2315,1600 2350,1600 2355.79,1605.79 U1.18@2355.79,1630.51
  Bottom Layer w10: v1(2305,1590) 2305,1563 C37.2@2300,1558 R30.1@2355,1558
NetC39_2: C39.2 U1.21 | length 72
  Top Layer w10: U1.21@2414.84,1630.51 2414.84,1560.16 C39.2@2416,1559
NetC40_1: C40.1 R33.2 U1.12 | length 171.2
  Top Layer w8: C40.1@2201.5,1807.24 R33.2@2201.5,1752.24 2221.85,1752.24 2239.25,1734.84 U1.12@2310.51,1734.84
NetC41_1: C41.1 R33.1 | length 57.8
  Top Layer w8: C41.1@2088.5,1754.24 2090.5,1752.24 R33.1@2145.5,1752.24
NetC42_1: C42.1 R123.2 R124.1 | length 717
  Top Layer w15: C42.1@816.5,1515 v2(860,1515)
  Signal Layer 4 w10: v2(545,1425) 560,1425 615,1480 626.44,1480 634.31,1487.87 665.69,1487.87 673.56,1480 685,1480 720,1515 v2(860,1515)
  Bottom Layer w15: R123.2@366.5,1285 366.5,1316.5 415,1365 485,1365 v2(545,1425) ; v2(860,1515) 860,1510 875,1495 R124.1@908.5,1495
NetC45_1: C45.1 R124.2 R125.1 | length 191.2
  Bottom Layer w15: R124.2@971.5,1495 1008.95,1495 1018.95,1505 1088.5,1505 R125.1@1088.5,1435
NetC48_1: C48.1 U2.1 | length 78.9
  Top Layer w10: U2.1@1629.8,418.66 1629.8,342.48 C48.1@1631.69,340.59
NetC49_1: C49.1 R128.2 R129.1 | length 543.4
  Top Layer w10: C49.1@816.5,1630 v2(855,1630) R129.1@893.5,1630
  Signal Layer 4 w10: v2(530,1500) 530,1550 580,1600 700,1600 730,1630 v2(855,1630)
  Bottom Layer w10: R128.2@482.07,1475 505,1475 v2(530,1500)
NetC50_1: C50.1 L4.1 L5.2
  other v2: 1075,390 1075,420 1075,450 1075,480 1075,510
NetC50_2: C50.2 U2.30 | length 179.3
  Top Layer w10: C50.2@1196.69,395.59 1225.59,395.59 1250,420 1250,445 1274.84,469.84 U2.30@1330.59,469.84
NetC51_1: C51.1 R15.2 R34.1 R36.2 R37.2 U2.2 | length 408.5
  Top Layer w10: U2.2@1629.8,444.25 1703.9,444.25 1721.5,426.65 R37.2@1721.5,409.61 1721.5,342 R34.1@1723.5,340 R36.2@1723.5,275 ; C51.1@1631.69,275.59 1722.91,275.59 R36.2@1723.5,275 ; R15.2@1723.5,210 R36.2@1723.5,275
NetC53_2: C53.2 C54.2 R42.2 U2.8 | length 654.6
  Top Layer w15: U2.8@1629.8,597.8 1682.2,597.8 1699.91,580.09 C53.2@1761.56,580.09 ; R42.2@1890.87,580.77 R42.2@1890.18,580.09 ; C53.2@1761.56,580.09 R42.2@1890.18,580.09 ; C53.2@1761.56,580.09 R42.2@1890.18,580.09 ; C53.2@1761.56,580.09 R42.2@1890.18,580.09 ; C53.2@1761.56,580.09 R42.2@1890.18,580.09
NetC55_1: C55.1 C56.1 R45.2 U2.9 | length 944.8
  Top Layer w15: U2.9@1629.8,623.39 1708.39,623.39 1730.77,645.77 ; 1730.77,645.77 R45.2@1890.87,645.77 ; 1730.77,645.77 1762.37,645.77 1730.77,645.77 ; 1730.77,645.77 R45.2@1890.87,645.77 ; 1730.77,645.77 R45.2@1890.87,645.77 ; 1730.77,645.77 R45.2@1890.87,645.77 ; R45.2@1890.87,645.77 1825.37,645.77 R45.2@1890.87,645.77
NetC60_1: C60.1 L7.1 L8.2
  other v2: 1075,720 1075,750 1075,775 1075,800 1075,845
NetC60_2: C60.2 U2.19 | length 153.4
  Top Layer w10: C60.2@1201.69,810.59 1234.41,810.59 1293.66,751.34 U2.19@1330.59,751.34
NetC61_2: C61.2 R28.2 R49.1 R51.2 R53.2 U2.15 | length 1490.4
  Top Layer w10: U2.15@1629.8,776.93 1681.93,776.93 1705.5,800.5 ; C61.2@1631.69,945.59 1702.32,945.59 R49.1@1703.5,946.77 ; R28.2@1705.5,1076.77 R51.2@1705.5,1011.77 ; 1705.5,800.5 R49.1@1705.5,946.77 ; 1705.5,800.5 R51.2@1705.5,1011.77 ; 1705.5,800.5 R51.2@1705.5,1011.77 ; 1705.5,800.5 R49.1@1705.5,946.77 ; 1705.5,800.5 R51.2@1705.5,1011.77 ; 1705.5,800.5 R51.2@1705.5,1011.77 ; R49.1@1705.5,946.77 R51.2@1705.5,1011.77 ; R49.1@1705.5,946.77 R51.2@1705.5,1011.77
NetC62_1: C62.1 U2.16 | length 78.9
  Top Layer w10: U2.16@1629.8,802.52 1629.8,878.7 C62.1@1631.69,880.59
NetC66_1: C66.1 R137.1 R144.2 | length 915.1
  Top Layer w10: R144.2@325.5,605 325.5,673.5 350,698 v2(396,698)
  Top Layer w20: v2(835,980) R137.1@873.5,980
  Signal Layer 4 w10: v2(396,698) 396,897 500,1001 691,1001 712,980 v2(835,980)
  Bottom Layer w20: C66.1@828.5,1015 828.5,986.5 v2(835,980)
NetC67_2: C67.2 R63.2 U3.7 | length 200.4
  Top Layer w10: R63.2@2291.5,70 C67.2@2390,70 2390,40 2400,30 v1(2420,30)
  Bottom Layer w10: v1(2420,30) U3.7@2420,67.72
NetC68_1: C68.1 C69.1 C70.1 C71.1 C72.1 C73.1 C75.1 C76.1 C77.1 D5.2 D12.1 D18.1 D19.1 D20.1 L10.1 Q6.1 Q6.2 Q6.3 R119.2 R120.2 | length 353.3
  Top Layer w10: C68.1@806.5,2030 849.71,2073.21 v2(851.74,2073.21)
  Signal Layer 4 w10: v2(310,1615) 345,1580 v2(345,1380)
  Bottom Layer w10: v2(345,1380) 345,1418.5 R120.2@346.5,1420
  other v2: 480,1885 510,1885 480,1910 510,1910 480,1935 510,1935 480,1960 510,1960 875,2060 900,2060 925,2060 950,2060 875,2085 900,2085 925,2085 950,2085
NetC81_2: C81.2 R65.1 U3.6 | length 153.2
  Top Layer w10: v1(2470,30) R65.1@2470,78.5 2478.5,70 C81.2@2533.5,70
  Bottom Layer w10: v1(2470,30) U3.6@2470,67.72
NetC82_1: C82.1 R61.1 R100.2 U3.4 | length 265
  Top Layer w10: v1(2520,230) 2535,215 R100.2@2583.5,215 2583.5,155 v2(2542,155)
  Bottom Layer w10: v1(2520,230) U3.4@2520,282.28 ; v2(2542,155) R61.1@2583.5,155
NetC83_1: C83.1 R62.1 R64.2 U3.1 | length 392.9
  Top Layer w10: v1(2370,235) 2370,220 2375,215 C83.1@2398.5,215
  Bottom Layer w10: U3.1@2370,282.28 v1(2370,235) 2400,205 2535,205 2545,215 R62.1@2583.5,215 R64.2@2583.5,285
NetC91_1: C91.1 U4.1 | length 117.8
  Top Layer w10: U4.1@2907.4,1884.37 2907.4,1937.4 2920,1950 C91.1@2967,1950
NetC91_2: C91.2 D11.1 L21.1 U4.10 | length 189.6
  Top Layer w10: C91.2@3023,1950 3065,1950 ; U4.10@3082.6,1884.37 3082.6,1932.4 ; 3065,1950 3082.6,1932.4 ; 3065,1950 3082.6,1932.4 ; 3065,1950 3082.6,1932.4 ; 3065,1950 3082.6,1932.4
  other v2: 3080,1955 3105,1955 3130,1955 3155,1955
NetC99_1: C99.1 R73.2 U5.1 | length 112.6
  Top Layer w15: U5.1@2968.86,1370.16 2968.86,1415.86 R73.2@2970,1417 2990.62,1417 2998.62,1425 C99.1@3032,1425
NetC102_1: C102.1 R74.2 U4.8 | length 177.7
  Top Layer w10: U4.8@3082.6,1845 C102.1@3201.38,1845 3201.38,1824.72 3192,1815.35 R74.2@3192,1790
NetC103_1: C103.1 U4.4 | length 228.7
  Top Layer w10: C103.1@2806.5,1771.5 C103.1@2806.5,1780 ; U4.4@2907.4,1825.31 2875.31,1825.31 C103.1@2830,1780 ; C103.1@2806.5,1780 C103.1@2830,1780 ; C103.1@2806.5,1780 C103.1@2830,1780 ; C103.1@2806.5,1780 C103.1@2830,1780 ; C103.1@2806.5,1780 C103.1@2830,1780 ; C103.1@2830,1780 2815,1780 C103.1@2830,1780
NetC104_1: C104.1 R74.1 | length 55
  Top Layer w10: R74.1@3248,1790 C104.1@3303,1790
NetC111_1: C111.1 C112.1 C113.1 U10.87 U10.115 | length 696.1
  Top Layer w20: v1(3095,225) 3113.5,225 C111.1@3118.5,230 3116.38,227.87 C112.1@3116.38,170 C113.1@3116.38,115
  Signal Layer 3 w7: v1(3090,505) 3090,275 3090.63,274.37 3090.63,271.98 3095,267.6 v1(3095,225)
  Bottom Layer w7: U10.115@2886.85,504.37 2936.97,504.37 2937.6,505 v1(3090,505) ; U10.87@3087.64,161.85 3088.07,162.29 3088.07,223.07 3090,225 v1(3095,225)
NetC115_1: C115.1 R95.2 U10.68 | length 224.5
  Top Layer w7: v2@3515,118.54 3515,115 3521.38,108.62 C115.1@3521.38,90
  Top Layer w22: v2@3515,118.54 R95.2@3515,148.5
  Bottom Layer w7: U10.68@3386.85,161.85 3386.85,132.32 3400.63,118.54 v2@3515,118.54
  other v2: 3515,120
NetC120_1: C120.1 R104.2 Y1.2 | length 140.9
  Top Layer w20: C120.1@3255,286.38 3280.04,286.38 3305.79,312.13 3311.38,306.54 R104.2@3311.38,235
NetC121_1: C121.1 U10.66 Y1.1 | length 105
  Bottom Layer w7: U10.66@3418.35,161.85 3418.35,243.35 v2(3435,260)
NetC122_1: C122.1 R106.2 Y2.1 | length 138.3
  Top Layer w7: R106.2@2970,378.62 2970,400 2978.31,408.31 Y2.1@3023.5,408.31 3031.38,416.18 C122.1@3031.38,465
NetC123_1: C123.1 U10.88 Y2.3 | length 255.3
  Top Layer w7: Y2.3@3086.5,321.69 3096.18,331.38 C123.1@3140,331.38 3140,310 v1(3110,280)
  Bottom Layer w7: U10.88@3071.89,161.85 3071.89,241.89 v1(3110,280)
NetD1_1: D1.1 D1.2 L1.2 Q1.5 R1.2
  other v2: 2500,502.62 2610,502.62 2555,528.91 2500,565 2610,565 2555,590 2500,615 2610,615
NetD6_1: D6.1 R44.1 R57.2 | length 331.9
  Bottom Layer w25: D6.1@225.47,2057 318,2057 360,2015 385,2015 ; R44.1@388.5,2080 388.5,2018.5 385,2015 ; R57.2@473.5,2015 385,2015
NetD7_1: D7.1 R55.1 R59.2 | length 318.5
  Top Layer w30: D7.1@219.47,1350 290,1350 320,1320 R55.1@458.5,1320 R59.2@458.5,1260 R59.2@453.5,1255
NetD10_1: D10.1 R71.1 | length 81.9
  Top Layer w20: R71.1@2843,1005 2875,1005 2890,1020 D10.1@2918.66,1020
NetD13_1: D13.1 R113.1 R117.2 | length 223.2
  Top Layer w25: v2(395,1802) R117.2@439.5,1802
  Bottom Layer w25: D13.1@269.47,1830 367,1830 v2(395,1802) R113.1@436.57,1802
NetD14_1: D14.1 R111.1 R115.2
NetD17_1: D17.1 Q6.4 R121.2 | length 323
  Bottom Layer w15: Q6.4@200.43,1661 311,1661 327,1645 D17.1@380.53,1645 435.57,1645 438.5,1647.93 R121.2@438.5,1725
NetD17_2: D17.2 R121.1 R126.2 | length 124.4
  Top Layer w10: R126.2@501.5,1655 R126.2@509.47,1655
  Top Layer w30: R126.2@509.47,1655 510,1655.53 v2(510,1687.5)
  Bottom Layer w30: R121.1@501.5,1725 510,1716.5 v2(510,1687.5) 510,1645.53 D17.2@509.47,1645
NetD21_1: D21.1 R63.1 | length 93.7
  Top Layer w10: D21.1@2135,70.53 2227.97,70.53 R63.1@2228.5,70
NetEC1_15: EC1.15 L9.2
NetEC1_23: EC1.23 L2.2 | length 233.2
  Top Layer w60: EC1.23@-160.24,812.99 L2.2@72.99,812.99
NetEC1_33: EC1.33 L6.2 | length 235.2
  Top Layer w60: EC1.33@-160.24,312.99 L6.2@75,312.99
NetJ3_1: J3.1 R80.1 | length 75.6
  Top Layer w8: R80.1@3305,2043.62 v1(3333.62,2043.62)
  Bottom Layer w8: v1(3333.62,2043.62) 3378.5,2043.62 J3.1@3380,2045.12
NetJ3_2: J3.2 R85.1 | length 133.3
  Top Layer w8: R85.1@3375,1753.62 v1(3375,1795)
  Bottom Layer w8: v1(3375,1795) 3380,1800 J3.2@3380,1884.88
NetJ3_4: J3.4 R86.1 | length 133.3
  Top Layer w8: R86.1@3425,1753.62 v1(3425,1795)
  Bottom Layer w8: v1(3425,1795) 3430,1800 J3.4@3430,1884.88
NetJ3_6: J3.6 R87.1 | length 131.3
  Top Layer w8: R87.1@3480,1753.62 v1(3480,1795)
  Bottom Layer w8: v1(3480,1795) J3.6@3480,1884.88
NetJ3_8: J3.8 R88.1 | length 131.3
  Top Layer w8: R88.1@3530,1753.62 v1(3530,1795)
  Bottom Layer w8: v1(3530,1795) J3.8@3530,1884.88
NetJ3_10: J3.10 R89.1 | length 129
  Top Layer w8: R89.1@3585,1758 v1(3585,1790)
  Bottom Layer w8: J3.10@3580,1884.88 3580,1795 v1(3585,1790)
NetL4_2: L4.2 R35.1 U2.31 | length 406.1
  Top Layer w10: U2.31@1330.59,444.25 1289.64,444.25 1280,434.62 1280,390 1375.31,294.68 v1(1375.31,160)
  Bottom Layer w10: R35.1@1337.91,160 v1(1375.31,160)
NetL5_1: L5.1 U2.28 U2.29
NetL7_2: L7.2 R52.2 U2.18 | length 370.2
  Top Layer w10: U2.18@1330.59,776.93 1293.35,776.93 1285,785.28 1285,835 1377.31,927.31 v2(1377.31,1030.77)
  Bottom Layer w10: R52.2@1339.91,1030.77 v2(1377.31,1030.77)
NetL8_1: L8.1 U2.20 U2.21
NetL20_1: L20.1 U5.5 | length 66.1
  Top Layer w15: 2902.79,1267.8 U5.5@2968.86,1267.8
  other v2: 2895,1235 2895,1260
NetQ1_1: Q1.1 Q1.2 Q1.3 R4.2 R6.2 R9.2
NetQ1_4: Q1.4 R2.2 | length 842.9
  Top Layer w10: R2.2@2473.73,1499.33 2473.73,1476.27 v1(2477.46,1480)
  Signal Layer 3 w10: 2431,724 v2(2450,705)
  Signal Layer 3 w20: 2425,714 2425,1229 2467,1271 2467,1467 2477.46,1477.46 v1(2477.46,1480)
  other v1: 2467,1459
  other v2: 2415,700
NetQ3_1: Q3.1 Q3.2 Q3.3 R30.2 R32.2 | length 351.4
  Signal Layer 4 w10: v1(2091,1414) 2354,1414 v1(2355,1415)
  Bottom Layer w10: v1(2355,1415) R30.2@2355,1502
NetQ3_4: Q3.4 R25.2 | length 488.6
  Top Layer w10: v1(2310,1455) 2345,1455 2355,1465 R25.2@2355,1502
  Signal Layer 4 w30: v2(1920,1485) 2190,1485 2220,1455 v1(2310,1455)
  other v1: 2290,1455
  other v2: 1895,1470
NetQ4_1: Q4.1 Q5.3 R46.1 | length 856.6
  Top Layer w10: R46.1@1906.5,945 1988.4,945 v1(1991.7,941.7) ; Q4.1@1972.4,357.24 v1(1991.7,337.95) Q5.3@1991.7,198.94
  Signal Layer 3 w10: v1(1991.7,337.95) v1(1991.7,941.7)
NetQ4_3: Q4.3 R42.1 R45.1 | length 390.8
  Top Layer w20: Q4.3@1935,262.76 1935,505 1953.86,523.86 R42.1@1953.86,580.77 R45.1@1953.86,645.77
NetQ5_1: Q5.1 R48.1 R50.2 | length 588.1
  Top Layer w10: 1916.21,98.5 1922.16,104.45 ; Q5.1@1954.3,104.45 Q5.1@1949.84,100 ; R48.1@1806.5,100 Q5.1@1949.84,100 ; R48.1@1806.5,100 Q5.1@1949.84,100 ; R48.1@1806.5,100 Q5.1@1949.84,100 ; R48.1@1806.5,100 Q5.1@1949.84,100
NetQ7_1: Q7.1 R123.1 | length 61.4
  Bottom Layer w10: Q7.1@242.4,1285.63 302.87,1285.63 R123.1@303.5,1285
NetQ7_3: Q7.3 R120.1 R122.2 | length 131.1
  Bottom Layer w20: Q7.3@205,1364.37 R122.2@205,1418.5 ; R122.2@206.5,1420 R120.1@283.5,1420
NetQ8_1: Q8.1 R128.1 | length 64.7
  Bottom Layer w20: Q8.1@357.4,1475.63 R128.1@418.44,1475.63
  Bottom Layer w30: R128.1@416.48,1472.4 R128.1@419.07,1475
NetQ8_3: Q8.3 R119.1 R126.1 R127.2 | length 1034.7
  Top Layer w10: v2@438.21,1536.99 R119.1@438.21,1579.71
  Top Layer w20: R119.1@438.5,1580 R126.1@438.5,1645 ; R119.1@438.5,1580 R126.1@438.5,1645 ; R119.1@438.5,1580 R126.1@438.5,1645 ; R119.1@438.5,1580 R126.1@438.5,1645 ; R119.1@440,1576.5 v2(440,1535) R119.1@440,1576.5 ; R119.1@440,1576.5 R119.1@436.5,1580 R119.1@440,1576.5
  Bottom Layer w10: R127.2@194.45,1554.37 R127.2@198.82,1550 ; 211.83,1536.99 v2@438.21,1536.99
  Bottom Layer w20: Q8.3@320,1554.37 420.63,1554.37 ; Q8.3@320,1554.37 194.45,1554.37 Q8.3@320,1554.37 ; 420.63,1554.37 v2(440,1535) 420.63,1554.37
NetQ9_4: Q9.4 R144.1
NetQ10_3: Q10.3 R134.1 R137.2 | length 463.1
  Top Layer w20: R134.1@1003.5,980 R137.2@936.5,980 R137.2@935,978.5 ; Q10.3@935,880 R137.2@935,978.5 ; Q10.3@935,880 R137.2@935,978.5 ; Q10.3@935,880 R137.2@935,978.5 ; Q10.3@935,880 R137.2@935,978.5
NetR2_1: R2.1 U1.22 | length 103.1
  Top Layer w10: U1.22@2434.53,1630.51 2434.53,1590.47 2440,1585 2460,1585 2473.73,1571.27 R2.1@2473.73,1555.33
NetR14_1: R14.1 U1.2 | length 118.6
  Top Layer w8: U1.2@2454.21,1819.49 2454.21,1859.61 2471.85,1877.24 2471.85,1918.74 R14.1@2480.35,1927.24
NetR24_2: R24.2 U1.9 | length 138.7
  Top Layer w8: R24.2@2200.08,1862.24 2231.85,1862.24 2300.2,1793.9 U1.9@2310.51,1793.9
NetR25_1: R25.1 U1.19 | length 81
  Top Layer w10: R25.1@2355,1558 2355,1575 2375.47,1595.47 U1.19@2375.47,1630.51
NetR31_2: R31.2 U1.32 | length 99.4
  Top Layer w10: U1.32@2499.49,1793.9 2513.5,1793.9 2561.85,1842.24 R31.2@2578.85,1842.24
NetR43_1: R43.1 U2.24 | length 183.5
  Top Layer w10: R43.1@1196.5,625 1196.5,630 R43.1@1193.05,630 ; U2.24@1330.59,623.39 R43.1@1199.66,623.39 ; R43.1@1193.05,630 R43.1@1199.66,623.39 ; R43.1@1193.05,630 R43.1@1199.66,623.39 ; R43.1@1193.05,630 R43.1@1199.66,623.39 ; R43.1@1193.05,630 R43.1@1199.66,623.39 ; R43.1@1199.66,623.39 1197.27,625.78 R43.1@1199.66,623.39
NetR65_2: R65.2 TP1.1 | length 284.7
  Top Layer w10: TP1.1@2234.18,174.71 2280.29,174.71 2344.95,110.05 2444.95,110.05 2445.97,111.06 2455,111.06 2470,126.06 R65.2@2470,141.5
NetR66_2: R66.2 U3.2 | length 93.3
  Bottom Layer w10: R66.2@2418.5,375 2420,373.5 U3.2@2420,282.28
NetR67_1: R67.1 U4.6 U5.2 | length 638.5
  Top Layer w10: U4.6@3082.6,1805.63 3082.6,1740.4 R67.1@3085,1738
  Top Layer w15: U5.2@2968.86,1344.57 2900.43,1344.57 2885,1360 2885,1515 3025,1655 3025,1710 3053,1738 R67.1@3085,1738
NetR68_1: R68.1 R76.2 U4.3 | length 1104.4
  Top Layer w10: R76.2@2695,1845 U4.3@2907.4,1845 ; R76.2@2695,1845 U4.3@2907.4,1845 ; R76.2@2695,1845 U4.3@2907.4,1845 ; R76.2@2695,1845 U4.3@2907.4,1845 ; U4.3@2907.4,1845 2780,1845 U4.3@2907.4,1845
NetR69_2: R69.2 R72.2 U5.8 | length 212.1
  Top Layer w10: R69.2@2850,1128 R69.2@2856.21,1134.21 ; 2854.45,1159.98 R72.2@2854.45,1191.02
  Top Layer w15: R72.2@2848,1185 R69.2@2848,1130 R69.2@2850,1128 ; R72.2@2854.45,1191.02 U5.8@2968.86,1191.02
NetR70_1: R70.1 U5.9 U5.19 | length 957.7
  Top Layer w10: U5.19@3201.14,1344.57 3264.57,1344.57 v1(3275,1355)
  Top Layer w15: R70.1@2848,1075 2890,1075 2900,1085 2900,1145 2920.43,1165.43 U5.9@2968.86,1165.43
  Signal Layer 3 w10: v1(3220,1055) 3220,1300 v1(3275,1355)
  Signal Layer 4 w10: v1(2865,1075) 3200,1075 v1(3220,1055)
NetR75_1: R75.1 R77.2 U4.7 | length 232.3
  Top Layer w10: U4.7@3082.6,1825.31 3129.68,1825.31 3160,1795 3160,1747.83 3172.83,1735 R77.2@3192,1735 3192,1680 R75.1@3190,1678
NetR78_2: R78.2 U4.5 | length 70.6
  Top Layer w10: R78.2@2907.4,1735 2907.4,1738.9 U4.5@2907.4,1805.63
NetR79_1: R79.1 U5.12 | length 99.9
  Top Layer w15: U5.12@3201.14,1165.43 3297.43,1165.43 R79.1@3300,1168
NetR92_1: R92.1 U10.42 | length 438.8
  Top Layer w7: v1(3490,860) 3510,880 R92.1@3510,907
  Signal Layer 3 w7: v1(3490,860) 3490,830 3495,825 3502.6,825 3506.98,820.63 3509.37,820.63 3552.36,777.64 v1(3552.36,567.36)
  Bottom Layer w7: U10.42@3493.15,567.36 v1(3552.36,567.36)
NetR94_2: R94.2 U10.9 | length 146.4
  Top Layer w7: v1(3095,680) 3104.82,670.18 3115.34,670.18 3115.34,646.86 R94.2@3116.02,646.18
  Bottom Layer w7: U10.9@3071.89,768.15 3071.89,703.11 v1(3095,680)
NetR95_1: R95.1 R96.2 R97.2 | length 660.8
  Top Layer w7: R95.1@3515,211.5 3523.5,220 R97.2@3523.5,290 3523.5,728.5 3593,798 R96.2@3593,840
NetR101_1: R101.1 U10.59 | length 161.9
  Top Layer w7: v1@3628.5,353.5 v1(3630,355)
  Bottom Layer w7: U10.59@3493.15,299.65 3574.65,299.65 v1(3630,355)
NetR104_1: R104.1 U10.67 | length 112.7
  Top Layer w20: R104.1@3358.62,235 v2(3395,235)
  Bottom Layer w7: v2(3395,235) 3402.6,227.4 U10.67@3402.6,161.85
NetR106_1: R106.1 U10.89 | length 234.7
  Top Layer w7: v1(2970,280) R106.1@2970,331.38
  Bottom Layer w7: v1(2970,280) 3000,280 3002.63,277.37 3015.63,277.37 3015.63,276.98 3026.98,265.63 3034.37,265.63 3056.14,243.86 U10.89@3056.14,161.85
PC4: U10.25
PC5: U10.24
PC6: U10.23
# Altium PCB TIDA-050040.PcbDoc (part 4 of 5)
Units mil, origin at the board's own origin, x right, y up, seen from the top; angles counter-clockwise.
Board outline 4045.79 x 2180 mil, 6 copper layers (Top Layer, Signal Layer 1, Signal Layer 2, Signal Layer 3, Signal Layer 4, Bottom Layer), stack 61.485 mil thick; 343 components, 188 nets, 986 pads, 710 vias.

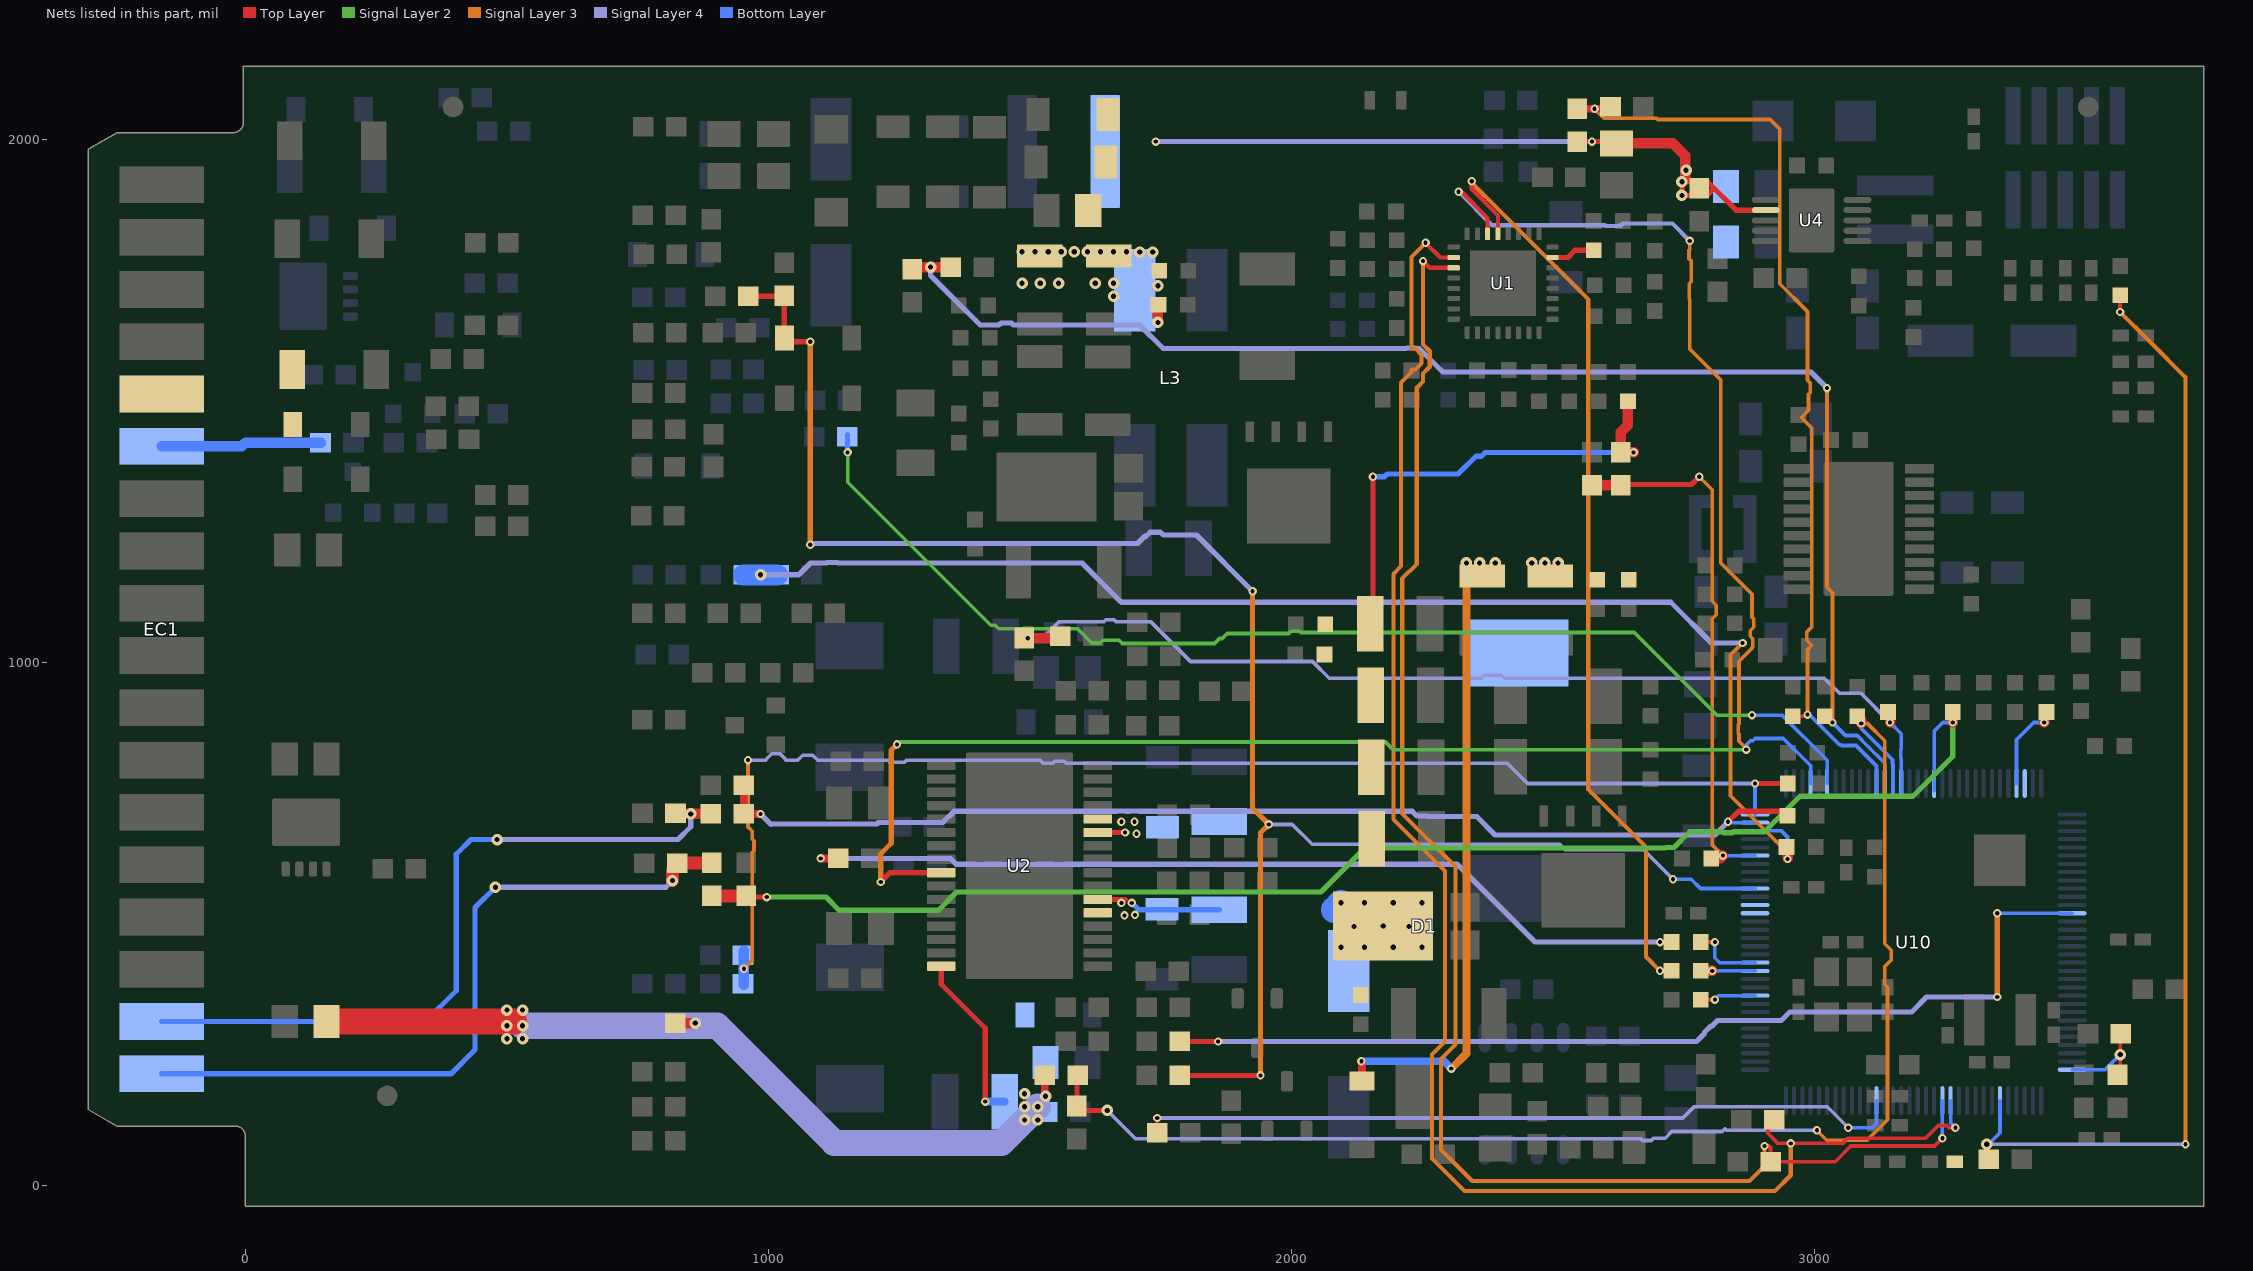
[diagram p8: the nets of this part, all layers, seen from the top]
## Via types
v1: diameter 16, hole 8, Top Layer to Bottom Layer, tented both sides, 318 vias
v2: diameter 22, hole 10, Top Layer to Bottom Layer, tented both sides, 299 vias
v3: diameter 19.68, hole 7.87, Top Layer to Bottom Layer, 47 vias
v4: diameter 19.68, hole 7.87, Top Layer to Bottom Layer, tented both sides, 28 vias
v5: diameter 50, hole 28, Top Layer to Bottom Layer, 18 vias

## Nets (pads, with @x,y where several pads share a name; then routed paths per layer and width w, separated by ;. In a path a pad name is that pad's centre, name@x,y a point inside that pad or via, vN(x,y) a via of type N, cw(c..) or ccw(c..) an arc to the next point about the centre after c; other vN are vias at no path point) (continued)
PD3: U1.6 U2.25 U10.4 | length 3865.7
  Top Layer w8: v1(2320,1900) 2325,1900 2375.47,1849.53 U1.6@2375.47,1819.49
  Top Layer w10: v1(1215,580) 1232.79,597.8 U2.25@1330.59,597.8
  Signal Layer 2 w7: v1(1246,843) 1250.63,847.63 2180,847.63 2192.63,835 2194.63,833 v1(2870,833)
  Signal Layer 3 w7: v1(2762,1806) 2762,1789.4 2760.63,1788.02 2760.63,1771.98 2765.13,1767.48 2765.13,1728.56 2760.75,1724.19 2760.75,1695.81 2762,1694.57 2762,1599 2821,1540 2821,1190 2881,1130 2881,1086.4 2884.37,1083.03 2884.37,1066.98 2877.58,1060.18 2877.58,1049.82 2882.37,1045.02 2882.37,1028.98 2881,1027.6 2881,1027 2856,1002 2856,881.4 2854.63,880.02 2854.63,863.98 2856,862.6 2856,849 2870,835 v1(2870,833)
  Signal Layer 3 w10: v1(1215,580) 1215,634 1235,654 1235,832 v1(1246,843)
  Signal Layer 4 w8: v1(2320,1900) 2384.13,1835.87 2599.58,1835.87 2600.82,1834.63 2626.37,1834.63 2626.62,1834.87 2630.13,1834.87 2634.38,1839.13 2728.87,1839.13 v1(2762,1806)
  Bottom Layer w7: v1(2870,833) 2870,841.81 2878.19,850 2882.6,850 2886.98,854.37 2940.83,854.37 2993.15,802.05 U10.4@2993.15,768.15
PD5: C130.1 R135.1 R138.2 U10.126 | length 2609.6
  Top Layer w7: v1(2949,624) v1@2949,626
  Top Layer w20: v1@2949,626 C130.1@2949,640
  Signal Layer 3 w7: v1(2863,1037) 2840,1014 2840,886.43 2839.75,886.19 2839.75,857.81 2840,857.57 2840,745 2949,636 v1(2949,624)
  Signal Layer 4 w10: v2(985,1167.27) 1057.8,1167.27 1080.53,1190 1111.24,1190 1112.38,1191.14 1132.15,1191.14 1133.29,1190 1600,1190 1674.38,1115.62 1675.21,1115.62 1675.83,1115 2725.64,1115 2803.64,1037 v1(2863,1037)
  Bottom Layer w7: U10.126@2886.85,677.6 2937.4,677.6 2949,666 v1(2949,624)
  Bottom Layer w40: R138.2@952.5,1167.27 v2(985,1167.27) R135.1@1017.5,1167.27
PD6: C129.1 R130.1 R132.2 U10.127 | length 2158.9
  Top Layer w10: v1(2835,695) 2855,715 C129.1@2947,715
  Top Layer w15: R130.1@952.99,765 R132.2@952.99,710 v1(985,710)
  Signal Layer 4 w10: v1(985,710) 1005,690 1005.59,690.59 1201.07,690.59 1201.35,690.87 1207.67,690.87 1210.24,693.45 1333.45,693.45 1355,715 1665.48,715 1666.35,715.87 1683.65,715.87 1684.52,715 1690.48,715 1691.35,715.87 1708.65,715.87 1709.52,715 2231.24,715 2240.11,706.13 2258.87,706.13 2260,705 2354.71,705 2389.71,670 2810,670 v1(2835,695)
  Bottom Layer w7: v1(2835,695) 2836.65,693.35 U10.127@2886.85,693.35
PD7: C128.1 R140.1 R142.2 U10.128 | length 2570.5
  Top Layer w10: v1(2886.85,768.15) C128.1@2949.4,768.15
  Signal Layer 3 w7: v1(953.15,414) 969.1,429.95 969.1,636.9 972.37,640.18 972.37,658.72 969,662.09 969,677 961,685 v1(961,813)
  Signal Layer 4 w7: v1(961,813) 995,813 995,813.65 1006.35,825 1022.4,825 1033.74,813.65 1033.74,813 1055.36,813 1055.86,812.5 1065.73,822.37 1084.27,822.37 1094.14,812.5 1094.64,813 1227.57,813 1231.81,808.75 1260.19,808.75 1264.43,813 1520,813 1526,807 1544.24,807 1548.18,810.94 1565.76,810.94 1569.7,807 2413,807 2451.85,768.15 v1(2886.85,768.15)
  Bottom Layer w7: U10.128@2886.85,709.09 v1(2886.85,768.15)
  Bottom Layer w10: R140.1@951.5,448.54 R140.1@953.15,448.54
  Bottom Layer w20: R142.2@953.15,383.54 R140.1@953.15,448.54
PE0: C116.1 R40.1 R41.2 U10.15 | length 1978.3
  Top Layer w20: v1(1496,1046) 1554.5,1046 R41.2@1558.5,1050 ; v1(3145,885) C116.1@3145,905
  Signal Layer 4 w7: v1(1496,1046) 1524,1046 1555.33,1077.33 1640.93,1077.33 1644.98,1081.37 1661.02,1081.37 1665.07,1077.33 1731.67,1077.33 1807.37,1001.63 2040.37,1001.63 2072.38,969.62 2362.7,969.62 2368.33,975.25 2401.67,975.25 2407.3,969.62 3019.38,969.62 3048.37,940.63 3089.37,940.63 v1(3145,885)
  Bottom Layer w7: v1(3145,885) 3166.38,863.62 3166.38,833.78 3165.63,833.02 3165.63,816.98 3166.38,816.22 U10.15@3166.38,750
PE1: C117.1 R38.1 R39.2 U10.14 | length 2647.2
  Top Layer w10: R38.1@1591.5,210 1590,208.5 1590,142.95 v2(1647.95,142.95)
  Top Layer w20: C117.1@3082,897 3090,889 v1(3090,883)
  Signal Layer 3 w7: v1(3005,105) 3024.01,85.99 3100.99,85.99 3140,125 3140,378.62 3134.88,383.74 3134.88,418.24 3147.37,430.73 3147.37,449.27 3134.88,461.76 3134.88,850.12 3102,883 v1(3090,883)
  Signal Layer 4 w7: v2(1647.95,142.95) 1702.1,88.8 2668.8,88.8 2671.98,85.63 2688.03,85.63 2692.4,90 2715,90 2727.63,102.63 2824.27,102.63 2829.36,107.72 2832.07,105 v1(3005,105)
  Bottom Layer w7: v1(3090,883) 3090,873.22 3149.76,813.46 3149.76,805.85 3150.63,804.97 U10.14@3150.63,750
PE2: C118.1 R21.1 R23.2 U10.13 | length 2736.4
  Top Layer w20: R21.1@1275,1751.5 1279.26,1755.76 v2(1310,1755.76) R23.2@1348.6,1755.76 ; C118.1@3020,897 C118.1@3020,900.63
  Signal Layer 3 w7: v1@3025,1525 v1(3024.41,1524.41) 3024.41,1143.85 3035,1133.26 v1(3035,885)
  Signal Layer 4 w10: v2(1310,1755.76) 1310,1740 1405,1645 1441.24,1645 1445.11,1648.87 1464.89,1648.87 1468.76,1645 1710,1645 1755,1600 2219.48,1600 2220.35,1600.87 2237.65,1600.87 2238.52,1600 2244.64,1600 2289.64,1555 2993.83,1555 v1(3024.41,1524.41)
  Bottom Layer w7: v1(3035,885) 3060,860 3082.19,860 3102.53,839.66 3134.88,807.3 U10.13@3134.88,750
PE3: C131.1 R5.1 R7.2 U10.12 | length 1859.6
  Top Layer w7: C131.1@2959,897 2984,897 v1(2987,900)
  Top Layer w15: R5.1@2546.85,2058.74 v1(2580,2058.74) 2606.85,2058.74 R7.2@2610.35,2062.24
  Signal Layer 3 w7: v1(2580,2058.74) 2598.11,2040.63 2698.37,2040.63 2701,2038 2916,2038 2934,2020 2934,1724 2987,1671 2987,1539.64 2992.37,1534.27 2992.37,1515.73 2989,1512.36 2989,1482 2975,1468 2995,1448 2995,1067.4 2985.63,1058.03 2985.63,1041.98 2995,1032.6 2987,1024.6 v1(2987,900)
  Bottom Layer w7: v1(2987,900) 2990.6,900 3048.23,842.37 3051.02,842.37 3052.4,841 3080,841 3119.13,801.87 U10.12@3119.13,750
PE4: C132.1 R8.1 R13.2 U10.123 | length 1167.4
  Top Layer w7: R13.2@2575,1338.5 R8.1@2630,1338.5
  Top Layer w10: R13.2@2570,1340 2765,1340 v1(2780,1355)
  Top Layer w15: C132.1@2803,625 v1@2820,625
  Top Layer w20: R13.2@2570,1340 2571.5,1338.5 R8.1@2630,1338.5 ; v1@2820,625 v1(2825.35,630.35)
  Signal Layer 3 w7: v1(2780,1355) 2805,1330 2805,1116.64 2812.37,1109.27 2812.37,1090.73 2805,1083.36 2805,650.71 v1(2825.35,630.35)
  Bottom Layer w7: v1(2825.35,630.35) U10.123@2886.85,630.35
PH0: R91.1 U10.29 | length 170.6
  Top Layer w20: v1(3440,885) R91.1@3440,905
  Bottom Layer w7: U10.29@3386.85,768.15 3386.85,851.85 3420,885 v1(3440,885)
PH1: U10.30
PJ0: U10.116
PJ1: U10.117
PL4: R48.2 U10.85 | length 1476.9
  Top Layer w7: R48.2@1743.5,100 v1(1743.5,128.5)
  Signal Layer 4 w7: v1(1743.5,128.5) 2748.5,128.5 2770,150 3025,150 v1(3065,110)
  Bottom Layer w7: v1(3065,110) 3111.38,110 3119.13,117.76 U10.85@3119.13,161.85
PM1: R102.1 U1.11 U10.77 | length 2997.1
  Top Layer w7: v1(2905,75) 2914,75 2916.5,72.5 R102.1@2916.5,45 3040,45 3070,75 3230,75 v1(3245,90)
  Top Layer w8: v1(2251.85,1767.24) 2264.57,1754.53 U1.11@2310.51,1754.53
  Signal Layer 3 w8: v1(2251.85,1767.24) 2251.85,1607.7 2264.75,1594.81 2264.75,1565.19 2251.85,1552.3 2251.85,1536.85 2240,1525 2240,1188 2212,1160 2212,711 2314,609 2314,269 2286.12,241.12 2286.12,67.88 2346,8 2876,8 2905,37 v1(2905,75)
  Bottom Layer w7: v1(3245,90) 3245,161.73 U10.77@3245.12,161.85
PM2: R103.1 U1.10 U10.76 | length 3156.5
  Top Layer w7: R103.1@2911.5,115 2911.5,99.18 2930.68,80 3053.96,80 3063.84,89.87 3212.59,89.87 3237.09,114.37 3253.14,114.37 3257.52,110 v1(3270,110)
  Top Layer w8: v1(2256.85,1802.24) 2284.88,1774.21 U1.10@2310.51,1774.21
  Signal Layer 3 w8: v1(2256.85,1802.24) 2230,1775.39 2230,1599.87 2237.23,1599.87 2248.87,1588.23 2248.87,1571.77 2237.23,1560.13 2230,1560.13 2230,1555 2210,1535 2210,1184 2195.21,1169.21 2195.21,699.79 2294,601 2294,275 2269,250 2269,51 2330.98,-10.98 2925.02,-10.98 2955,19 v1(2955,80)
  Bottom Layer w7: U10.76@3260.87,161.85 3260.87,119.13 v1(3270,110)
PN2: R109.2 U10.109 | length 103.7
  Top Layer w20: R109.2@2783,410 v1@2805,410
  Bottom Layer w7: v1(2805.12,409.88) U10.109@2886.85,409.88
PN3: R110.2 U10.110 | length 137.7
  Top Layer w7: R110.2@2783,465 v1(2810,465)
  Bottom Layer w7: v1(2810,465) 2810,435 2819.37,425.63 U10.110@2886.85,425.63
PP5: R108.1 U10.106 | length 107
  Top Layer w7: R108.1@2783,355 v1(2810,355)
  Bottom Layer w7: v1(2810,355) 2817.64,362.64 U10.106@2886.85,362.64
RST_N: C119.1 R89.2 R99.2 U10.70 | length 2150.1
  Top Layer w8: v1(3585,1670) R89.2@3585,1702
  Signal Layer 3 w8: v1(3585,1670) 3640,1615 3710,1545 v1(3710,78.54)
  Signal Layer 4 w7: v2(3330,78.54) v1(3710,78.54)
  Bottom Layer w7: v2@3331.77,76.77 3355.35,100.35 U10.70@3355.35,161.85
SSN_BOOST: R109.1 U1.5 | length 1802.5
  Top Layer w8: v1(2345,1920) 2345,1905 2395.16,1854.84 U1.5@2395.16,1819.49
  Top Layer w10: v1(2705,410) R109.1@2727,410
  Signal Layer 3 w8: v1(2345,1920) 2345,1917 2365.13,1896.87 2365.13,1896.77 2376.77,1885.13 2376.87,1885.13 2568,1694 2568,757 2678,647 2678,437 v1(2705,410)
SSN_BUCK_1-2: R43.2 R110.1 | length 1728.5
  Top Layer w10: v1(2705,465) R110.1@2727,465
  Top Layer w15: v1(1100,625) R43.2@1133.5,625
  Signal Layer 4 w10: v1(1100,625) 1348,625 1359,614 1395.45,614 1395.99,613.47 1414.8,613.47 1415.34,614 1444.66,614 1445.2,613.47 1464.02,613.47 1464.55,614 1495.84,614 1496.38,613.47 1515.2,613.47 1515.73,614 1545.06,614 1545.59,613.47 1564.41,613.47 1564.94,614 2317,614 2466,465 v1(2705,465)
TI: D12.2 D14.2 EC1.9
TI+: C44.1 C46.1 C133.1 D3.1 L6.1 R35.2 R38.2 U2.32 | length 2948.4
  Top Layer w10: U2.32@1330.59,418.66 1330.59,384.41 1414.68,300.31 v1(1414.68,160)
  Top Layer w15: R38.2@1528.5,210 1528.5,171.5 v2(1530,170)
  Top Layer w20: C133.1@821.5,310 v2(860,310)
  Top Layer w50: L6.1@155,312.99 512.99,312.99 ; L6.1@155,312.99 512.99,312.99 ; L6.1@155,312.99 512.99,312.99 ; L6.1@155,312.99 512.99,312.99
  Signal Layer 4 w50: v2(530,305) 902,305 1126,81 1446,81 v2(1515,150)
  Bottom Layer w15: v1(1414.68,160) R35.2@1452.09,160
  other v2: 1490,125 1515,125 1490,150 1490,175 500,280 530,280 500,305 500,335 530,335
TI_Fault: EC1.12 R122.1 | length 306.6
  Bottom Layer w20: EC1.12@-160.24,1412.99 -7.01,1412.99 0,1420 R122.1@143.5,1420
TI_FAULT_MICRO: R125.2 U10.6 | length 2253.5
  Signal Layer 2 w7: v1(1151.5,1401.5) 1151.5,1344.5 1424.98,1071.02 1433.36,1071.02 1440.38,1064 1486.6,1064 1487.98,1065.37 1504.02,1065.37 1505.4,1064 1591,1064 1618.2,1036.8 1634.12,1036.8 1639.57,1042.25 1670.43,1042.25 1676.68,1036 1853,1036 1862.63,1045.63 1868.02,1045.63 1877.4,1055 1995.22,1055 1999.59,1059.37 2015.64,1059.37 2018.01,1057 2656,1057 2814,899 v1(2881,899)
  Bottom Layer w7: v1(2881,899) 2938.27,899 3024.65,812.63 U10.6@3024.65,768.15
  Bottom Layer w10: v1(1151.5,1401.5) R125.2@1151.5,1435
TI_MICRO: D15.1 R15.1 R112.2 R116.2 U10.119 | length 3570.5
  Top Layer w10: R112.2@961.5,1700 1029.27,1700 1030.53,1698.74 D15.1@1030.53,1620 ; D15.1@1030.53,1613.99 1031.52,1613 v1(1080,1613) ; R15.1@1786.5,210 v1(1941,210)
  Signal Layer 3 w10: v1(1080,1225) v1(1080,1613) ; v1(1926,1136) 1926,721 v1(1957,690) 1941,674 v1(1941,210)
  Signal Layer 4 w7: v1(1957,690) 2002,690 2040,652 2513,652 2523,642 2673,642 v1(2730,585)
  Signal Layer 4 w10: v1(1080,1225) 1082,1227 1705.74,1227 1719.99,1241.25 1721.24,1240 1730.11,1248.87 1749.89,1248.87 1755.32,1243.44 1818.56,1243.44 v1(1926,1136)
  Bottom Layer w7: v1(2730,585) 2765,585 2782.64,567.36 U10.119@2886.85,567.36
TI_NTC: C65.1 EC1.36 R133.1 | length 1384
  Top Layer w25: v2(816.5,582.75) 816.5,604.05 828.51,616.06 884.88,616.06 R133.1@885,615.94
  Signal Layer 4 w10: v2(478,570) 803.74,570 v2(816.5,582.75)
  Bottom Layer w10: EC1.36@-160.24,212.99 392.99,212.99 439,259 439,531 v2(478,570)
TI_RBIN: C57.1 EC1.34 R132.1 | length 1416.5
  Top Layer w20: C57.1@817.99,710 v2(851.5,710) R132.1@890,710
  Signal Layer 4 w10: v2@480,661.01 v2(481,661) 827.05,660.99 851.5,685.43 v2(851.5,710)
  Bottom Layer w10: EC1.34@-160.24,312.99 343.99,312.99 403,372 403,633 431,661 v2(481,661)
TIND_NTC: C125.1 R131.1 R133.2 U10.19 | length 2748.7
  Top Layer w10: R131.1@950,552.95 951.95,551 v1(997,551)
  Top Layer w20: v1(3265,885) C125.1@3265,905
  Top Layer w25: R133.2@892,552.95 R131.1@950,552.95
  Signal Layer 2 w10: v1(997,551) 1110,551 1135,526 1325,526 1360,561 2057,561 2141,645 2715.48,645 2716.35,645.87 2731.87,645.87 2762,676 2824.48,676 2826.35,674.13 2843.65,674.13 2845.52,676 2905,676 2973,744 3189,744 3265,820 v1(3265,885)
  Bottom Layer w7: U10.19@3229.37,755 U10.19@3229.37,768.15 3229.37,868.83 3245.54,885 v1(3265,885)
TIPWM: R36.1 U10.45 | length 1903.3
  Top Layer w10: R36.1@1786.5,275 v1(1860,275)
  Signal Layer 3 w10: v1(3350,360) 3350,520 v1(3350.12,520.12)
  Signal Layer 4 w10: v1(1860,275) 2775,275 2790.23,290.23 2790.23,292.54 2802.46,304.77 2804.77,304.77 2815,315 2936.84,315 2953.22,331.37 3186.37,331.37 3215,360 v1(3350,360)
  Bottom Layer w7: v1(3350.12,520.12) U10.45@3493.15,520.12
VBST: C1.2 C5.1 C6.1 C7.1 C8.1 C9.1 C10.2 C11.1 C43.2 C47.1 C52.2 C59.1 D1.3 R3.2 R8.2 U2.5 U2.6 U2.11 U2.12 | length 1224.7
  Top Layer w10: U2.6@1629.8,546.61 1682.21,546.61 ; U2.11@1629.8,674.57 v1(1682.21,674.57) ; C6.1@2150.82,1073.68 2156,1078.86 v1(2156,1355)
  Top Layer w20: R3.2@2643.76,1499.24 2643.76,1453.76 2630,1440 R8.2@2630,1401.5 v1(2654.5,1401.5)
  Bottom Layer w10: v1@1695.35,540 1708.5,526.86 C52.2@1862,526.86 ; v1(2156,1355) 2178,1355 2182.13,1359.13 2183.65,1359.13 2184.52,1360 2319,1360 2353.13,1394.13 2363.64,1394.13 2371.01,1401.5 v1(2654.5,1401.5)
  Bottom Layer w50: 2081.86,526.86 v2(2095,540)
  other v1: 1681,516 1701,517 1675,540 1695,540 1704,672 1675,695 1700,695
  other v2: 2095,455 2140,455 2195,455 2250,455 2120,495 2225,495 2175.61,495.68 2140,540 2195,540 2250,540
VDD: C38.2 U1.31 | length 84.7
  Top Layer w10: U1.31@2499.49,1774.21 2528.82,1774.21 2542.55,1787.94 C38.2@2578.52,1787.94
Vin: C2.2 C3.2 C4.1 C19.2 C20.1 C21.1 C22.1 C23.1 C78.1 C79.1 C80.1 C92.1 C93.1 D21.2 L1.1 L3.1 L10.2 R5.2 R11.1 R68.2 U4.2 | length 2626
  Top Layer w10: R5.2@2546.85,1995.75 v1(2575,1995.75) 2618.35,1995.75 R11.1@2621.85,1992.24 ; 2753.5,1928.5 2747,1922 v2(2747,1919) ; U4.2@2907.4,1864.69 2850.31,1864.69 R68.2@2796,1919 ; v2(2747,1919) R68.2@2796,1919 ; v2(2747,1919) v2(2747,1892.78) 2794.78,1892.78 2808.5,1906.5 R68.2@2796,1919
  Top Layer w15: D21.2@2135,199.47 v1@2135,236
  Top Layer w20: v2(1745,1650) 1745,1682.61 C19.2@1746.15,1683.76 ; R11.1@2621.85,1992.24 2729.76,1992.24 2753.5,1968.5 2753.5,1928.5
  Signal Layer 3 w15: v1(2306,223) 2335,252 v2(2335,1190)
  Signal Layer 4 w10: v1(1740.75,1995.75) v1(2575,1995.75)
  Bottom Layer w15: v1(2134,237) 2292,237 v1(2306,223)
  other v2: 2360,1190 2390,1190 2460,1190 2485,1190 2510,1190 1660,1700 1745,1720 1485,1725 1520,1725 1555,1725 1625,1725 1660,1725 1485,1785 1510,1785 1535,1785 1560,1785 1585,1785 1610,1785 1635,1785 1660,1785 1685,1785 1710,1784.53 1735,1784.53 2755,1941
WAKE: R97.1 R98.1 U10.64 | length 185.1
  Top Layer w7: R98.1@3580,211.5 3585,216.5 v2(3585,250) 3585,288.5 R97.1@3586.5,290
  Bottom Layer w7: U10.64@3493.15,220.91 3555.9,220.91 v2(3585,250)
pads on no net: EC1.13 EC1.14 EC1.17 EC1.21 EC1.22 EC1.29 EC1.30 EC1.31 FID1.1 FID2.1 FID3.1 Q6.9@118.74,1700 Q6.9@124.65,1677.56 Q6.9@124.65,1722.44 Q6.9@147.68,1638.98 Q6.9@147.68,1700 Q6.9@147.68,1761.02 Q9.9@54.98,657.32 Q9.9@93.56,680.35 Q9.9@116,657.32 Q9.9@116,686.26 Q9.9@138.44,680.35 Q9.9@177.02,657.32 U1.13 U1.28 U2.33@1480.2,610.59 U3.3 U3.8 U4.11@2995,1845 U5.13 U5.16 U5.21@3085,1255 U10.3 U10.11 U10.22 U10.27 U10.31 U10.32 U10.33 U10.34 U10.35 U10.36 U10.37 U10.38 U10.40 U10.41 U10.43 U10.46 U10.50 U10.60 U10.61 U10.62 U10.63 U10.65 U10.71 U10.72 U10.73 U10.74 U10.75 U10.78 U10.81 U10.82 U10.83 U10.84 U10.86 U10.91 U10.92 U10.93 U10.94 U10.102 U10.105 U10.107 U10.108 U10.111 U10.112 U10.120 U10.121 U10.124 U10.125

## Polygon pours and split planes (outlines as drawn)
GND on Bottom Layer "BOTTOM_LAYER_GND_P296" (solid, remove dead copper, pour order 296): -48,2006 -48,-2 -2,-48 3743,-48 3743,2132 -5.94,2132 -5.94,2024.68 -25.62,2004.99
VBST on Bottom Layer "BOTTOM_LAYER_VBST_P254" (solid, remove dead copper, pour order 254): 1810,500 2050,500 2050,640 1970,720 1810,720
GND on Bottom Layer "BOTTOM_LAYER_GND_P252" (solid, remove dead copper, pour order 252): 2341,1788 2530,1788 2530,1663 2531,1662 2342,1662
Vin on Bottom Layer "BOTTOM_LAYER_VIN_P214" (solid, remove dead copper, pour order 214): 1575,2100.5 1575,1775 1765,1775 1770,1780 1770,2100.5
3V3 on Bottom Layer "BOTTOM_LAYER_3V3_P198" (solid, remove dead copper, pour order 198): 2740,920 2740,1330 2815,1330 2815,920
NetC68_1 on Bottom Layer "BOTTOM_LAYER_NETC68_1_P126" (solid, remove dead copper, pour order 126): 840,2100 840,1975 1350,1975 1455,1870 1515,1870 1515,2100
NetC68_1 on Bottom Layer "BOTTOM_LAYER_NETC68_1_P112" (solid, remove dead copper, pour order 112): 160,1624.51 160,2015 570,2015 570,1845 340,1845 315,1820 315,1625
DRLPOS on Bottom Layer "BOTTOM_LAYER_DRLPOS_P106" (solid, remove dead copper, pour order 106): -235,1750 -10,1750 21,1781 21,1864.71 159.71,1864.71 160,1865 160,1620 40,1620 -20,1680 -235,1680
LB1/LB2 on Bottom Layer "BOTTOM_LAYER_LB1/LB2_P100" (solid, remove dead copper, pour order 100): -245,1950 -55,1950 70,2075 115,2075 115,1880 -245,1880
NetC50_1 on Bottom Layer "BOTTOM_LAYER_NETC50_1_P038" (solid, remove dead copper, pour order 38): 1225.2,530.59 1225.2,370.59 1060.2,370.59 1060.2,530.59
NetC60_1 on Bottom Layer "BOTTOM_LAYER_NETC60_1_P028" (solid, remove dead copper, pour order 28): 1220.2,845.59 1220.2,690.59 1055.2,690.59 1055.2,845.59
Vin on Bottom Layer "BOTTOM_LAYER_VIN_P132" (solid, remove dead copper, pour order 132): 1770,1635 1770,1799.52 1460,1799.52 1460,1697.79 1463.03,1694.76 1645.24,1694.76 1660,1680 1660,1635
NetC16_1 on Bottom Layer "BOTTOM_LAYER_NETC16_1_P136" (solid, remove dead copper, pour order 136): 2596.85,1897.24 2468.31,1897.24 2466.85,1898.7 2466.85,1846.34 2475.94,1837.24 2596.85,1837.24
NetC30_1 on Bottom Layer "BOTTOM_LAYER_NETC30_1_P146" (solid, remove dead copper, pour order 146): 2115,1374.96 1885.04,1374.96 1884.99,1470 1780,1470 1780,1160 2115,1160
NetC18_2 on Bottom Layer "BOTTOM_LAYER_NETC18_2_P152" (solid, remove dead copper, pour order 152): 1420,1245 1640,1245 1640,1430 1420,1430
NetC30_2 on Bottom Layer "BOTTOM_LAYER_NETC30_2_P158" (solid, remove dead copper, pour order 158): 1650,1145 1650,1470 1780,1470 1780,1145
NetL7_2 on Bottom Layer "BOTTOM_LAYER_NETL7_2_P160" (solid, remove dead copper, pour order 160): 1365,1095 1025.55,1095 1025.55,950.55 1025,950 1365,950
LBHB+ on Bottom Layer "BOTTOM_LAYER_LBHB+_P162" (solid, remove dead copper, pour order 162): 1430,1100 1565,1100 1565,838.94 1430,838.94
NetL4_2 on Bottom Layer "BOTTOM_LAYER_NETL4_2_P164" (solid, remove dead copper, pour order 164): 1365,100 1050,100 1050,250 1365,250
TI+ on Bottom Layer "BOTTOM_LAYER_TI+_P166" (solid, remove dead copper, pour order 166): 1430,106.85 1430,370 1550,370 1550,105 1431.85,105
VBST on Bottom Layer "BOTTOM_LAYER_VBST_P170" (solid, remove dead copper, pour order 170): 2040,330 2040,640 2280,640 2280,330
NetD1_1 on Bottom Layer "BOTTOM_LAYER_NETD1_1_P176" (solid, remove dead copper, pour order 176): 2320.46,635 2685.94,635 2685.94,415.94 2685.91,415.96 2317.74,415.96 2317.74,632.28
Vin on Bottom Layer "BOTTOM_LAYER_VIN_P182" (solid, remove dead copper, pour order 182): 2530,1035 2530,1215 2310,1215 2310,1035
Vin on Bottom Layer "BOTTOM_LAYER_VIN_P184" (solid, remove dead copper, pour order 184): 2801,1925 2876,1925 2876,1754 2801,1754
NetC91_2 on Bottom Layer "BOTTOM_LAYER_NETC91_2_P186" (solid, remove dead copper, pour order 186): 3040,1890 3239.5,1890 3239.5,2094.5 3240,2095 3040,2095
5V on Bottom Layer "BOTTOM_LAYER_5V_P190" (solid, remove dead copper, pour order 190): 3066.22,1840.56 3066.22,1556.22 3065,1555 3065,1495 3305,1495 3305,1841.63 3067.3,1841.63
GND on Bottom Layer "BOTTOM_LAYER_GND_P220" (solid, remove dead copper, pour order 220): 1565,1100 1665,1100 1665,840 1566.06,840 1565,838.94
GND on Bottom Layer "BOTTOM_LAYER_GND_P222" (solid, remove dead copper, pour order 222): 1495,500 1495,195 1915,195 1915,500
GND on Bottom Layer "BOTTOM_LAYER_GND_P228" (solid, remove dead copper, pour order 228): 3150,1015 2905,1015 2905,1505 2910,1510 2930,1490 3150,1490 3150,1410
GND on Bottom Layer "BOTTOM_LAYER_GND_P244" (solid, remove dead copper, pour order 244): 1765,1485 1769.19,1480.81 1769.19,2121.81 1765,2125.99 720,2125.99 720,1490 715,1485
GND on Bottom Layer "BOTTOM_LAYER_GND_P246" (solid, remove dead copper, pour order 246): 1877,1633.03 1770,1635.34 1770,2125.99 2115,2125.99 2115,1620 1890.03,1620
GND on Bottom Layer "BOTTOM_LAYER_GND_P248" (solid, remove dead copper, pour order 248): 3070,2125.99 3066.22,2122.21 3066.22,1556.22 2823.78,1556.22 2820,1560 2820,2125.99
GND on Top Layer "TOP_LAYER_GND_P286" (solid, remove dead copper, pour order 286): -46,2014 -46,6 0,-40 3745,-40 3745,2140 -3.94,2140 -3.94,2032.68 -23.62,2012.99
NetD14_1 on Top Layer "TOP_LAYER_NETD14_1_P284" (solid, remove dead copper, pour order 284): 192,1507 192,1405.95 196.63,1401.32 391.68,1401.32 392,1401 392,1523 388,1527 191,1527
3V3 on Top Layer "TOP_LAYER_3V3_P250" (solid, remove dead copper, pour order 250): 2740,1165 2740,990 2815,990 2815,1165
Vin on Top Layer "TOP_LAYER_VIN_P212" (solid, remove dead copper, pour order 212): 1575,2125.99 1575,1810 1460,1810 1460,1706.72 1471.96,1694.76 1645.24,1694.76 1680,1660 1770,1660 1770,2125.99
MCU_3V3D on Top Layer "TOP_LAYER_MCU_3V3D_P210" (solid, remove dead copper, pour order 210): 2735,15 2875,15 2875,150 2735,150
RST_N on Top Layer "TOP_LAYER_RST_N_P206" (solid, remove dead copper, pour order 206): 3245,33.19 3329.49,33.19 3350,53.7 3350,85 3340,95 3285,95 3245,55
NetC120_1 on Top Layer "TOP_LAYER_NETC120_1_P204" (solid, remove dead copper, pour order 204): 3230,305 3330,305 3330,210 3230,210
NetC121_1 on Top Layer "TOP_LAYER_NETC121_1_P202" (solid, remove dead copper, pour order 202): 3473,305 3387,305 3387,245 3473,245
5V on Top Layer "TOP_LAYER_5V_P200" (solid, remove dead copper, pour order 200): 3300,1340 3300,1285 3340,1285 3340,1340
5V on Top Layer "TOP_LAYER_5V_P196" (solid, remove dead copper, pour order 196): 2995,1325 2930,1325 2865,1390 2865,1420 2820,1420 2820,1337.6 2820,1285 2867.52,1285 2910,1285 2995,1285
NetC68_1 on Top Layer "TOP_LAYER_NETC68_1_P124" (solid, remove dead copper, pour order 124): 775,2125 775,1975 1460,1975 1460,2125
NetC68_1 on Top Layer "TOP_LAYER_NETC68_1_P118" (solid, remove dead copper, pour order 118): 115,1525 390,1525 390,1850 565,1850 566.02,1851.02 566.02,1986.46 564.27,1988.21 390,1988.21 390,2125.99 115,2125.99
TI on Top Layer "TOP_LAYER_TI_P108" (solid, remove dead copper, pour order 108): -240,1550 -30,1550 30,1610 30.79,1609.21 160,1609.21 160,1412.5 37.5,1412.5 -30,1480 -235,1480
DRLPOS on Top Layer "TOP_LAYER_DRLPOS_P104" (solid, remove dead copper, pour order 104): -235,1750 -10,1750 21,1781 21,1870 115,1870 115,1680 -235,1680
LB1/LB2 on Top Layer "TOP_LAYER_LB1/LB2_P102" (solid, remove dead copper, pour order 102): -245,1950 -51.49,1950 73.95,2075.44 74.39,2075 115,2075 115,1880 -245,1880
NetC50_1 on Top Layer "TOP_LAYER_NETC50_1_P036" (solid, remove dead copper, pour order 36): 1165.2,375.59 1165.2,530.59 1060.2,530.59 1060.2,375.59
NetC60_1 on Top Layer "TOP_LAYER_NETC60_1_P030" (solid, remove dead copper, pour order 30): 1160.2,690.59 1160.2,845.59 1055.2,845.59 1055.2,690.59
NetC16_1 on Top Layer "TOP_LAYER_NETC16_1_P134" (solid, remove dead copper, pour order 134): 2666.85,1942.24 2586.42,1942.24 2572.87,1955.79 2511.85,1955.79 2511.85,1898.7 2486.85,1898.7 2486.85,1872.24 2666.85,1872.24
DRLPOS+ on Top Layer "TOP_LAYER_DRLPOS+_P140" (solid, remove dead copper, pour order 140): 1220,1460 1220,1720 1390,1720 1390,1530 1328.69,1530 1327.41,1531.28 1327.41,1450 1220,1450
NetQ3_1 on Top Layer "TOP_LAYER_NETQ3_1_P142" (solid, remove dead copper, pour order 142): 2100,1395 2100,1620 1885,1620 1885,1470 1935,1420 1935,1395
NetC30_1 on Top Layer "TOP_LAYER_NETC30_1_P144" (solid, remove dead copper, pour order 144): 2100,1395 2115,1395 2115,1155 1780,1155 1780,1470 2060.78,1470 2079.09,1451.69
NetC30_2 on Top Layer "TOP_LAYER_NETC30_2_P154" (solid, remove dead copper, pour order 154): 1645,1414.72 1645,1232.09 1610,1232.09 1610,1117.91 1757.91,1117.91 1760,1120 1760,1425 1651.31,1425 1646.31,1430
NetC18_2 on Top Layer "TOP_LAYER_NETC18_2_P156" (solid, remove dead copper, pour order 156): 1220,1245 1645,1245 1645,1410.14 1708.46,1410.14 1708.46,1498.46 1710,1500 1464.03,1500 1464.03,1475 1220,1475
VBST on Top Layer "TOP_LAYER_VBST_P168" (solid, remove dead copper, pour order 168): 2200,1150 2200,599.69 2280,599.69 2280,400 2175,400 2175,330 2040,330 2040,1150
NetC1_1 on Top Layer "TOP_LAYER_NETC1_1_P172" (solid, remove dead copper, pour order 172): 2090,330 2090,265 2278.4,265 2280,266.6 2280,400 2160,400
NetD1_1 on Top Layer "TOP_LAYER_NETD1_1_P174" (solid, remove dead copper, pour order 174): 2280,266.6 2280,594.54 2320.46,635 2685.94,635 2685.94,266.6 2448.4,266.6
NetQ1_1 on Top Layer "TOP_LAYER_NETQ1_1_P178" (solid, remove dead copper, pour order 178): 2523.94,680 2523.94,956.03 2560,992.09 2562.09,990 2650,990 2650,800 2710.62,800 2710,799.38 2710,680
Vin on Top Layer "TOP_LAYER_VIN_P180" (solid, remove dead copper, pour order 180): 2310,1215 2310,1135 2680,1135 2680,1215
NetC91_2 on Top Layer "TOP_LAYER_NETC91_2_P188" (solid, remove dead copper, pour order 188): 3066.22,1888.96 3025,1888.96 3025,1975 3170,1975 3170,1885 3070.18,1885
GND on Top Layer "TOP_LAYER_GND_P224" (solid, remove dead copper, pour order 224): 2335,140 2350,125 2370,125 2370,180 2355,195 2335,195
GND on Top Layer "TOP_LAYER_GND_P226" (solid, remove dead copper, pour order 226): 2625,175 2625,100 2575,100 2575,25 2695,25 2695,175
GND on Top Layer "TOP_LAYER_GND_P230" (solid, remove dead copper, pour order 230): 2200,1215 2200,599.69 2524.69,599.69 2555,630 2555,1215
GND on Top Layer "TOP_LAYER_GND_P232" (solid, remove dead copper, pour order 232): 2555,1119.71 2704.71,1119.71 2705,1120 2705,940 2500,940 2495,945
GND on Top Layer "TOP_LAYER_GND_P234" (solid, remove dead copper, pour order 234): 1705.5,800.5 1705.5,404.5 1715,395 1905,395 1905,800
GND on Top Layer "TOP_LAYER_GND_P236" (solid, remove dead copper, pour order 236): 710,2100 710.5,2100.5 1575,2100.5 1575,1695 1565,1705 710,1705
GND on Top Layer "TOP_LAYER_GND_P238" (solid, remove dead copper, pour order 238): 1327.41,1450 1327.41,2123.58 1325,2125.99 2160.99,2125.99 2165,2130 2165,1684.43 2055,1574.43 2055,1450
GND on Top Layer "TOP_LAYER_GND_P240" (solid, remove dead copper, pour order 240): 2950,945 2950,1380 3230,1380 3230,945
GND on Top Layer "TOP_LAYER_GND_P242" (solid, remove dead copper, pour order 242): 2395,1525 2605,1525 2605,1380 2395,1380
VBST on Top Layer "TOP_LAYER_VBST_P264" (solid, remove dead copper, pour order 264): 1715,664 1667.68,664 1667.2,664.47 1667.2,705 1713,705 1715,707
VBST on Top Layer "TOP_LAYER_VBST_P266" (solid, remove dead copper, pour order 266): 1665,550 1665,500 1706,500 1710,504 1710,551.44
HB_LED on Top Layer "TOP_LAYER_HB_LED_P268" (solid, remove dead copper, pour order 268): -240,749 231,749 250,749 250,651 -16,651 -44,679 -239,679 -240,678
GND on Signal Layer 4 "SIGNAL_LAYER_4_GND_P294" (solid, remove dead copper, pour order 294): -48,2006 -48,-2 -2,-48 3743,-48 3743,2132 -5.94,2132 -5.94,2024.68 -25.62,2004.99
NetC68_1 on Signal Layer 4 "SIGNAL_LAYER_4_NETC68_1_P122" (solid, remove dead copper, pour order 122): 850,2100 850,2040 964.56,2040 965,2039.56 965,2100
NetC68_1 on Signal Layer 4 "SIGNAL_LAYER_4_NETC68_1_P120" (solid, remove dead copper, pour order 120): 450,1850 450,2045 455,2050 965,2050 965,1850
GND on Signal Layer 2 "SIGNAL_LAYER_2_GND_P290" (solid, remove dead copper, pour order 290): -48,2006 -48,-2 -2,-48 3743,-48 3743,2132 -5.94,2132 -5.94,2024.68 -25.62,2004.99
Vin on Signal Layer 2 "SIGNAL_LAYER_2_VIN_P216" (solid, remove dead copper, pour order 216): 1460,1085 1460,1685 1460,1910 2205,1910 2545,1570 2545,1085
GND on Signal Layer 1 "SIGNAL_LAYER_1_GND_P288" (solid, remove dead copper, pour order 288): -48,2006 -48,-2 -2,-48 3743,-48 3743,2132 -5.94,2132 -5.94,2024.68 -25.62,2004.99
GND on Signal Layer 3 "SIGNAL_LAYER_3_GND_P292" (solid, remove dead copper, pour order 292): -48,2006 -48,-2 -2,-48 3743,-48 3743,2132 -5.94,2132 -5.94,2024.68 -25.62,2004.99

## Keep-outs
Keep-Out Layer:
  text ".Layer_Name" at 293.21,-858.5 h60

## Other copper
Top Layer:
  rectangle net GND: -240,180 10,247
  rectangle net GND: -242,579 -30,649
  rectangle net GND: -241,981 -31,1047
  rectangle net GND: -241,1581 -6,1647
  rectangle net GND: -237,1779 -7,1845
  rectangle net Vin: 2719,1876 2801,1952
  rectangle net NetQ1_4: 2456,1450 2488,1516
  rectangle net NetQ3_4: 2275,1440 2325,1470
  rectangle net NetC122_1: 2960,368.78 3050,476.81
  rectangle net NetC123_1: 3065,270 3155,345
  rectangle net MCU_3V3D: 3375,31.3 3445,70
  rectangle net 5V: 3180.69,1285 3340,1323.8
  rectangle net 5V: 2867.52,1285 2995,1323.8
  rectangle net NetL20_1: 2865,1220 2910,1275
  rectangle net GND: 570,25 720,2100
  region net NetQ3_4: 1935,1500 1880,1500 1880,1420 1935,1420
  rectangle net NetL8_1: 1190,695 1347.94,730.57
  rectangle net NetL5_1: 1190,490 1347.94,525.85
  rectangle net VBST: 1605,515 1710,551.44
  rectangle net VBST: 1608.52,670.64 1715,707
  rectangle net NetQ1_4: 2390,685 2490,725
  rectangle net TI+: 480,265 550,350
  rectangle net LBHB+: 485,760 550,860
  rectangle net NetEC1_15: -210,1180 105,1245
  rectangle net DRLPOS+: 135,1185 270,1245
  rectangle net NetQ9_4: 149,582 282,630
  text ".Layer_Name" at 293.21,-858.5 h60
Signal Layer 2:
  rectangle net Vin: 2310,1165 2530,1215
Signal Layer 3:
  rectangle net NetQ1_4: 2390,685 2490,725
Signal Layer 4:
  rectangle net NetQ3_4: 1880,1455 1935,1500
  rectangle net DRLPOS+: 1225,1500 1300,1565
  rectangle net TI+: 480,265 550,350
  rectangle net TI+: 1475,106.85 1550,190
  rectangle net LBHB+: 1430,865 1515,960
  rectangle net LBHB+: 470,760 550,860
  rectangle net DRLPOS+: 180,1185 270,1245
Bottom Layer:
  rectangle net GND: -237,1784 -7,1845
  rectangle net GND: -241,1581 -6,1647
  rectangle net GND: -241,1178 3,1248
  rectangle net GND: -241,779 -22,848
  rectangle net GND: -241,378 57,447
  rectangle net Vin: 2732.29,1870 2873,1954.11
  rectangle net MCU_3V3D: 2715,25 2865,150
  rectangle net 5V: 3150,1280 3400,1335
  rectangle net 5V: 2820,1337.6 2910,1575
  rectangle net NetL20_1: 2835,1185 2910,1325
  region net GND: 720,2100 570,2100 570,25 720,25
  rectangle net VBST: 1665,500 1915,550
  rectangle net VBST: 1667.2,664.47 1922.37,705
  rectangle net GND: 1725,745 1915,840
  text ".Layer_Name" at 293.21,-858.5 h60

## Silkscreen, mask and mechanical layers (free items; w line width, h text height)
Top Overlay:
  text ".Layer_Name" at 293.21,-858.5 h60
Bottom Overlay:
  region: 3710,510 3710,810 3610,810 3610,510
  text "'.PRJ_Number'.PCB_Rev-" at 3701,1773 h108.27 r90
  text ".Layer_Name" at 293.21,-858.5 h60
Top Paste:
  text ".Layer_Name" at 293.21,-858.5 h60
Bottom Paste:
  text ".Layer_Name" at 293.21,-858.5 h60
Top Solder:
  text ".Layer_Name" at 293.21,-858.5 h60
  text ".Layer_Name" at 293.21,-858.5 h60
Bottom Solder:
  text ".Layer_Name" at 293.21,-858.5 h60
Drill Guide:
  text ".Layer_Name" at 293.21,-858.5 h60
M1 Board Outline:
  lines w10: -300.79,144.88 -300.79,1981.1 ; -245.67,2012.99 -23.62,2012.99 ; -3.94,2140 3745,2140 3745,-40 0,-40
  text ".Layer_Name" at 293.21,-858.5 h60
M2 Board Dimensions:
  rectangle: -283.79,-275.01 -158.79,-150.01
  rectangle: -158.79,-400.01 216.21,-275.01
  lines w7: -283.79,-275.01 716.21,-275.01 ; -158.79,-400.01 -158.79,-150.01 ; -33.79,-400.01 -33.79,-150.01 ; 216.21,-400.01 216.21,-150.01 ; 466.21,-400.01 466.21,-150.01 ; -283.79,-400.01 716.21,-400.01 716.21,-150.01 -283.79,-150.01 -283.79,-400.01
  text ".Layer_Name" at 293.21,-858.5 h60
M3 3D STEP Top:
  text ".Layer_Name" at 293.21,-858.5 h60
M4 3D STEP Bottom:
  text ".Layer_Name" at 293.21,-858.5 h60
M5 Assembly Top:
  lines w10: -575.79,-930.17 6024.21,-930.17 ; -575.79,-726.84 6026.21,-726.84 ; -575.79,-523.51 -575.79,-1133.51 3429.21,-1133.51 6026.21,-1133.51 6026.21,-523.51 -575.29,-523.51 -575.29,-1133.51 1000.21,-1133.51 ; 1889.21,-1133.51 1889.21,-523.51 ; 3156.21,-726.84 3156.21,-523.51 ; 3996.21,-726.84 3996.21,-523.51 ; 4618.21,-1140.01 4618.21,-937.17
  text "COMPONENTS MARKED 'DNP' SHOULD NOT BE POPULATED." at 869.71,-318.51 h60
  text "ASSEMBLY VARIANT:" at 869.21,-434.01 h60
  text ".VariantName" at 1905.21,-434.01 h60
  text "PCB VIEWED FROM TOP SIDE" at -512.29,-655.67 h60
  text "BOARD #:" at 1964.21,-655.67 h60
  text ".PRJ_Number" at 2509.71,-655.67 h60
  text "REV:" at 3354.21,-655.67 h60
  text ".PCB_Rev" at 3645.71,-655.67 h60
  text "SVN REV:" at 4192.21,-655.67 h60
  text ".VersionControl_RevNumber" at 4698.21,-655.67 h60
  text "TID #:" at 1964.21,-859.01 h60
  text ".TID" at 2509.71,-859.01 h60
  text "PLOT NAME =" at -512.29,-1064.34 h60
  text ".plot_File_Name" at 293.21,-1064.34 h60
  text "GENERATED    :" at 1966.21,-1064.34 h60
  text ".Print_Date" at 2835.71,-1064.34 h60
  text ".Print_Time" at 3564.71,-1064.34 h60
  text "TEXAS INSTRUMENTS" at 4829.21,-1064.34 h60
M6 Assembly Bottom:
  lines w10: -576.29,-727.34 6025.71,-727.34 ; -574.29,-930.67 6025.71,-930.67 ; 831.71,-1140.51 831.71,-937.67 ; 1453.71,-727.34 1453.71,-524.01 ; 2293.71,-727.34 2293.71,-524.01 ; 3560.71,-1134.01 3560.71,-524.01 ; 4449.71,-1134.01 6025.21,-1134.01 6025.21,-524.01 -576.29,-524.01 -576.29,-1134.01 2020.71,-1134.01 6025.71,-1134.01 6025.71,-524.01
  text "COMPONENTS MARKED 'DNP' SHOULD NOT BE POPULATED." at 5818.21,-318.01 h60
  text ".VariantName" at 4774.21,-434.01 h60
  text "ASSEMBLY VARIANT:" at 5813.21,-434.01 h60
  text ".VersionControl_RevNumber" at 751.71,-656.17 h60
  text "SVN REV:" at 1257.71,-656.17 h60
  text ".PCB_Rev" at 1804.21,-656.17 h60
  text "REV:" at 2095.71,-656.17 h60
  text ".PRJ_Number" at 2940.21,-656.17 h60
  text "BOARD #:" at 3485.71,-656.17 h60
  text "PCB VIEWED FROM BOTTOM SIDE" at 5962.21,-656.17 h60
  text ".TID" at 2940.21,-859.51 h60
  text "TID #:" at 3485.71,-859.51 h60
  text "TEXAS INSTRUMENTS" at 620.71,-1064.84 h60
  text ".Print_Time" at 1885.21,-1064.84 h60
  text ".Print_Date" at 2614.21,-1064.84 h60
  text "GENERATED    :" at 3483.71,-1064.84 h60
  text ".plot_File_Name" at 5156.71,-1064.84 h60
  text "PLOT NAME =" at 5962.21,-1064.84 h60
M9 Title Sheet:
  drawing of 57 lines, arcs and shapes, not listed
  text "1" at 456.05,8036.49 h70
  text "2" at 2951.71,8036.49 h70
  text "3" at 5441.06,8036.49 h70
  text "4" at 7947.72,8036.49 h70
  text "5" at 10446.71,8036.49 h70
  text "6" at 12951.71,8036.49 h70
  text "A" at -700.29,6893.49 h70
  text "A" at 14099.71,6893.49 h70
  text "B" at -700.29,4513.49 h70
  text "B" at 14099.71,4513.49 h70
  text "C" at -700.29,2138.49 h70
  text "C" at 14099.71,2138.49 h70
  text "PROJECT TITLE:" at 11059.71,277.49 h45
  text ".PRJ_Title" at 11109.71,144.17 h70
  text "DESIGNED FOR:" at 11059.71,-23.51 h45
  text ".PRJ_Customer" at 11109.71,-163.51 h70
  text "D" at -700.29,-231.51 h70
  text "D" at 14099.71,-231.51 h70
  text "FILE NAME:" at 11059.71,-323.51 h45
  text ".PCB_File_Name_No_Path" at 11109.71,-443.51 h70
  text "Texas Instruments (TI) and/or its licensors do not warrant the accuracy or completeness of this specification" at 6090.21,-605.35 h45
  text "ENGINEER:" at 11059.71,-613.51 h45
  text "LAYOUT BY:" at 12564.71,-613.51 h45
  text "or any information contained therein. TI and/or its licensors do not warrant that this design will meet" at 6045.23,-718.01 h45
  text ".PRJ_Engineer" at 11109.71,-768.5 h70
  text ".PCB_Layout" at 12615.21,-768.5 h70
  text "the specifications, will be suitable for your application or fit for any particular purpose, or will operate in" at 6045.23,-830.68 h45
  text ".Layer_Name" at 293.21,-858.5 h60
  text "ALTIUM DESIGNER VERSION:" at 12564.71,-923.51 h45
  text "an implementation. TI and/or its licensors do not warrant that the design is production worthy. You should" at 6045.23,-943.34 h45
  text "completely validate and test your design implementation to confirm the system functionality for your application." at 6090.21,-1056.01 h45
  text ".print_Scale" at 11109.71,-1056.83 h70
  text ".Application_BuildNumber" at 12615.21,-1056.83 h70
  text "1" at 456.05,-1263.51 h70
  text "2" at 2951.71,-1263.51 h70
  text "3" at 5441.06,-1263.51 h70
  text "4" at 7947.72,-1263.51 h70
  text "5" at 10446.71,-1263.51 h70
  text "6" at 12951.71,-1263.51 h70
M10 Fab Notes:
  drawing of 189 lines, arcs and shapes, not listed
  text "DESIGN INFORMATION" at 12098.23,6356.17 h60
  text "MIN. TRACK WIDTH:" at 11453.67,6224.04 h60
  text "7" at 12549.91,6224.04 h60
  text "MIL" at 12704.67,6224.04 h60
  text "MIL" at 12789,6102 h60
  text "MIN. CLEARANCE:" at 11453.67,6099.91 h60
  text "7.874" at 12489.91,6099.92 h60
  text "MIN. VIA PAD SIZE:" at 11453.67,5975.79 h60
  text "16" at 12519.92,5975.79 h60
  text "MIL" at 12704.67,5975.79 h60
  text "0.05mm (2MIL)" at 12148.67,5845.89 h60
  text "MINIMUM ANNULAR RING" at 11124.44,5837.67 h60
  text "EXTERNAL" at 12856.67,5837.67 h60
  text "PER" at 11324.44,5727.54 h60
  text "IPC-D-275 CLASS 2 LEVEL C" at 11544.44,5727.54 h60
  text "MIL, HOLES" at 13032.67,5627.06 h60
  text "+/-" at 12640.21,5618.48 h60
  text "+/-" at 13494.21,5618.48 h60
  text "REGISTRATION TOLERANCES:" at 11124.44,5617.41 h60
  text "METAL" at 12324.21,5617.41 h60
  text "5" at 12900.41,5617.41 h60
  text "3" at 13733.41,5617.41 h60
  text "MIL" at 13849.67,5617.41 h60
  text "HOLE SIZE TOLERANCE (UNLESS OTHERWISE SPECIFIED):" at 11124.44,5519.1 h60
  text "+/-" at 13494.21,5516.22 h60
  text "3" at 13733.41,5515.16 h60
  text "MIL" at 13849.67,5515.16 h60
  text "MATERIAL:" at 11049.67,5377.51 h60
  text "FR-4 High Tg" at 12036.12,5248.99 h60
  text "X" at 11891.68,5241 h60
  text "FR-408" at 11470.67,5236.48 h60
  text "OTHER" at 12958.67,5236.48 h60
  text "62 MIL (1.6mm) +/-10%" at 11790.77,5093.45 h60
  text "X" at 11670.68,5091 h60
  text "THICKNESS:" at 11124.44,5085.23 h60
  text "OTHER" at 13075.67,5085.23 h60
  text "TOLERANCE:" at 11124.44,4946.91 h60
  text "X" at 11972.68,4946.91 h60
  text "ANSI IPC-6012 TYPE 3 CLASS 2" at 12150.69,4946.91 h60
  text "OTHER +/-" at 12150.67,4802.73 h60
  text "BOW & TWIST:" at 11124.44,4657.54 h60
  text "X" at 11972.68,4657.54 h60
  text "ANSI IPC-6012 TYPE 3 CLASS 2" at 12150.69,4657.54 h60
  text "OTHER +/-" at 12150.67,4510.84 h60
  text "DRILLING:" at 11049.67,4380.22 h60
  text "NC_DRILL FILES" at 12810.67,4275.03 h60
  text "REFERENCE:" at 11124.44,4271.1 h60
  text "X" at 11781.68,4271 h60
  text "AS SHOWN" at 11959.67,4271.1 h60
  text "X" at 12682.68,4271.1 h60
  text "OTHER" at 13108.67,4128.84 h60
  text "PTH COPPER THICKNESS:" at 11124.12,4125.31 h60
  text "20-30 um" at 12391.35,4125.31 h60
  text "X" at 13005,4124 h60
  text "BOARD FINISH:" at 11049.67,3977.72 h60
  text "SILKSCREEN:" at 11204.89,3867.59 h60
  text "X" at 12162.68,3867.59 h60
  text "TOP" at 12279.67,3867.59 h60
  text "X" at 12672.68,3867.59 h60
  text "BOTTOM" at 12790.67,3867.59 h60
  text "SILKSCREEN COLOR:" at 11204.89,3712.4 h60
  text "X" at 12161.68,3712.4 h60
  text "WHITE" at 12279.67,3712.4 h60
  text "OTHER" at 12790.67,3712.4 h60
  text "X" at 12292.68,3568.95 h60
  text "GREEN" at 12410.67,3568.95 h60
  text "OTHER" at 13028.67,3568.95 h60
  text "SOLDER RESIST COLOR:" at 11204.89,3562.09 h60
  text "X" at 12292.68,3414.7 h60
  text "MATTE" at 12410.67,3414.7 h60
  text "SEMI-GLOSS" at 13028.21,3414.06 h60
  text "IMMERSION GOLD (ENIG)" at 12110.67,3241.93 h60
  text "ENEPIG" at 13448.21,3234.71 h60
  text "SURFACE FINISH:" at 11049.67,3233.71 h60
  text "X" at 11932.68,3233.71 h60
  text "IMM. TIN/SILVER OR EQUIV" at 11379.21,3096.39 h60
  text "OTHER" at 12810.67,3092.46 h60
  text "ARRAY/PANEL:" at 11049.67,2937.08 h60
  text "CUT AND TRIM PER M1 BOARD OUTLINE" at 12110.67,2928.86 h60
  text "N.C. ROUTE" at 12110.67,2792.89 h60
  text "X" at 12798.68,2792.89 h60
  text "V. SCORE" at 12976.67,2792.89 h60
  text "CERTIFICATION:" at 11049.67,2663.76 h60
  text "MATERIALS AND WORKMANSHIP FOR ALL PCBS" at 11774.67,2663.76 h60
  text "TO MEET OR EXCEED THE REQUIREMENTS OF:" at 11774.67,2569.7 h60
  text "X" at 11412.18,2441.07 h60
  text "ANSI IPC-A-600F CLASS ->" at 11540.18,2441.07 h60
  text "X" at 13188.18,2441.07 h60
  text "2" at 13298.18,2441.07 h60
  text "1" at 12983.18,2439.58 h60
  text "3" at 13652.18,2439.58 h60
  text "X" at 12224.18,2293.39 h60
  text "RoHS" at 12352.18,2293.39 h60
  text "OTHER" at 12996.58,2293.39 h60
  text "PER ORDER" at 13393.63,2293.39 h60
  text "ALL BOARDS MUST MEET OR EXCEED UL94-V0 REQUIREMENTS." at 11077.21,2139.56 h60
  text "PCB MUST BEAR THE UL94V-0 UL REGISTERED MATERIAL ID NUMBER" at 11077.21,2023.5 h60
  text "ADDITIONAL REQUIREMENTS:" at 11049.67,1854.07 h60
  text "MICROSECTION:" at 11124.44,1746.95 h60
  text "YES" at 12030.18,1746.95 h60
  text "REQUIRED" at 12891.67,1602.61 h60
  text "BARE BOARD ELEC. TEST:" at 11124.44,1599.76 h60
  text "NONE" at 12430.18,1599.76 h60
  text "X" at 12773.68,1599.76 h60
  text "PER ORDER" at 13483.67,1599.76 h60
  text "XX MIL VIAS REQUIRE NON-CONDUCTIVE FILL AND PLANARIZE" at 11292.59,1394.81 h59
  text "XX MIL VIAS REQUIRE CONDUCTIVE FILL AND PLANARIZE" at 11300.59,1290.83 h60
  text "OUTER XX MIL TRACES REQUIRE 50 OHM SINGLE-ENDED IMPEDANCE" at 11299.61,1127.45 h58
  text "LAYER 2 & 3 (INNER LAYERS) XX MIL WIDE, XX MIL SPACE / TRACES REQUIRE 100 OHM DIFFERENTIAL IMPEDANCE" at 11291.61,891.74 h60
  text ".Layer_Name" at 293.21,-858.5 h60
M11 Gerber Information:
  lines w10: -575.79,-930.17 6024.21,-930.17 ; -575.79,-726.84 6026.21,-726.84 ; -575.79,-523.51 -575.79,-1133.51 3429.21,-1133.51 6026.21,-1133.51 6026.21,-523.51 -575.29,-523.51 -575.29,-1133.51 1000.21,-1133.51 ; 1889.21,-1133.51 1889.21,-523.51 ; 3156.21,-726.84 3156.21,-523.51 ; 3996.21,-726.84 3996.21,-523.51 ; 4618.21,-1140.01 4618.21,-937.17
  text "ALL ARTWORK VIEWED FROM TOP SIDE" at -512.29,-655.67 h60
  text "BOARD #:" at 1964.21,-655.67 h60
  text ".PRJ_Number" at 2509.71,-655.67 h60
  text "REV:" at 3354.21,-655.67 h60
  text ".PCB_Rev" at 3645.71,-655.67 h60
  text "SVN REV:" at 4192.21,-655.67 h60
  text ".VersionControl_RevNumber" at 4698.21,-655.67 h60
  text "LAYER NAME =" at -512.29,-858.5 h60
  text "TID #:" at 1964.21,-859.01 h60
  text ".TID" at 2509.71,-859.01 h60
  text "PLOT NAME =" at -512.29,-1064.34 h60
  text ".plot_File_Name" at 293.21,-1064.34 h60
  text "GENERATED    :" at 1966.21,-1064.34 h60
  text ".Print_Date" at 2835.71,-1064.34 h60
  text ".Print_Time" at 3564.71,-1064.34 h60
  text "TEXAS INSTRUMENTS" at 4829.21,-1064.34 h60
M12 Stackup:
  drawing of 715 lines, arcs and shapes, not listed
  text "Layer" at 4926.3,7732.49 h60
  text "Name" at 5336.21,7732.49 h60
  text "Material" at 6275.95,7732.49 h60
  text "Thickness" at 7135.72,7732.49 h60
  text "Constant" at 7785.56,7732.49 h60
  text "Board Layer Stack" at 8355.42,7732.49 h60
  text "Board Layer Stack" at 9475.1,7732.49 h60
  text "1" at 4926.3,7612.49 h60
  text "Top Overlay" at 5336.21,7612.49 h60
  text "2" at 4926.3,7492.49 h60
  text "Top Solder" at 5336.21,7492.49 h60
  text "Solder Resist" at 6275.95,7492.49 h60
  text "0.40mil" at 7135.72,7492.49 h60
  text "3.5" at 7785.56,7492.49 h60
  text "3" at 4926.3,7372.49 h60
  text "Top Layer" at 5336.21,7372.49 h60
  text "Copper" at 6275.95,7372.49 h60
  text "1.42mil" at 7135.72,7372.49 h60
  text "4" at 4926.3,7252.49 h60
  text "Dielectric 1" at 5336.21,7252.49 h60
  text "FR-4" at 6275.95,7252.49 h60
  text "12.00mil" at 7135.72,7252.49 h60
  text "4.2" at 7785.56,7252.49 h60
  text "5" at 4926.3,7132.49 h60
  text "Signal Layer 1" at 5336.21,7132.49 h60
  text "Copper" at 6275.95,7132.49 h60
  text "1.42mil" at 7135.72,7132.49 h60
  text "6" at 4926.3,7012.49 h60
  text "Dielectric 2" at 5336.21,7012.49 h60
  text "FR-4" at 6275.95,7012.49 h60
  text "8.50mil" at 7135.72,7012.49 h60
  text "4.2" at 7785.56,7012.49 h60
  text "7" at 4926.3,6892.49 h60
  text "Signal Layer 2" at 5336.21,6892.49 h60
  text "Copper" at 6275.95,6892.49 h60
  text "1.40mil" at 7135.72,6892.49 h60
  text "8" at 4926.3,6772.49 h60
  text "Dielectric 3" at 5336.21,6772.49 h60
  text "FR-4" at 6275.95,6772.49 h60
  text "12.00mil" at 7135.72,6772.49 h60
  text "4.2" at 7785.56,6772.49 h60
  text "9" at 4926.3,6652.49 h60
  text "Signal Layer 3" at 5336.21,6652.49 h60
  text "Copper" at 6275.95,6652.49 h60
  text "1.42mil" at 7135.72,6652.49 h60
  text "10" at 4926.3,6532.49 h60
  text "Dielectric 4" at 5336.21,6532.49 h60
  text "FR-4" at 6275.95,6532.49 h60
  text "8.50mil" at 7135.72,6532.49 h60
  text "4.2" at 7785.56,6532.49 h60
  text "11" at 4926.3,6412.49 h60
  text "Signal Layer 4" at 5336.21,6412.49 h60
  text "Copper" at 6275.95,6412.49 h60
  text "1.42mil" at 7135.72,6412.49 h60
  text "12" at 4926.3,6292.49 h60
  text "Dielectric 5" at 5336.21,6292.49 h60
  text "12.00mil" at 7135.72,6292.49 h60
  text "4.2" at 7785.56,6292.49 h60
  text "13" at 4926.3,6172.49 h60
  text "Bottom Layer" at 5336.21,6172.49 h60
  text "Copper" at 6275.95,6172.49 h60
  text "1.42mil" at 7135.72,6172.49 h60
  text "14" at 4926.3,6052.49 h60
  text "Bottom Solder" at 5336.21,6052.49 h60
  text "Solder Resist" at 6275.95,6052.49 h60
  text "0.40mil" at 7135.72,6052.49 h60
  text "3.5" at 7785.56,6052.49 h60
  text "15" at 4926.3,5932.49 h60
  text "Bottom Overlay" at 5336.21,5932.49 h60
  text ".Layer_Name" at 293.21,-858.5 h60
M13 Component Bodies Top:
  text ".Layer_Name" at 293.21,-858.5 h60
M14 Component Bodies Bottom:
  text ".Layer_Name" at 293.21,-858.5 h60
M15 Courtyards Top:
  text ".Layer_Name" at 293.21,-858.5 h60
M16 Courtyards Bottom:
  text ".Layer_Name" at 293.21,-858.5 h60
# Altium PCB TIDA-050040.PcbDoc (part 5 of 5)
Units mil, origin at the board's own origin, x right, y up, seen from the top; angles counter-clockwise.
Board outline 4045.79 x 2180 mil, 6 copper layers (Top Layer, Signal Layer 1, Signal Layer 2, Signal Layer 3, Signal Layer 4, Bottom Layer), stack 61.485 mil thick; 343 components, 188 nets, 986 pads, 710 vias.

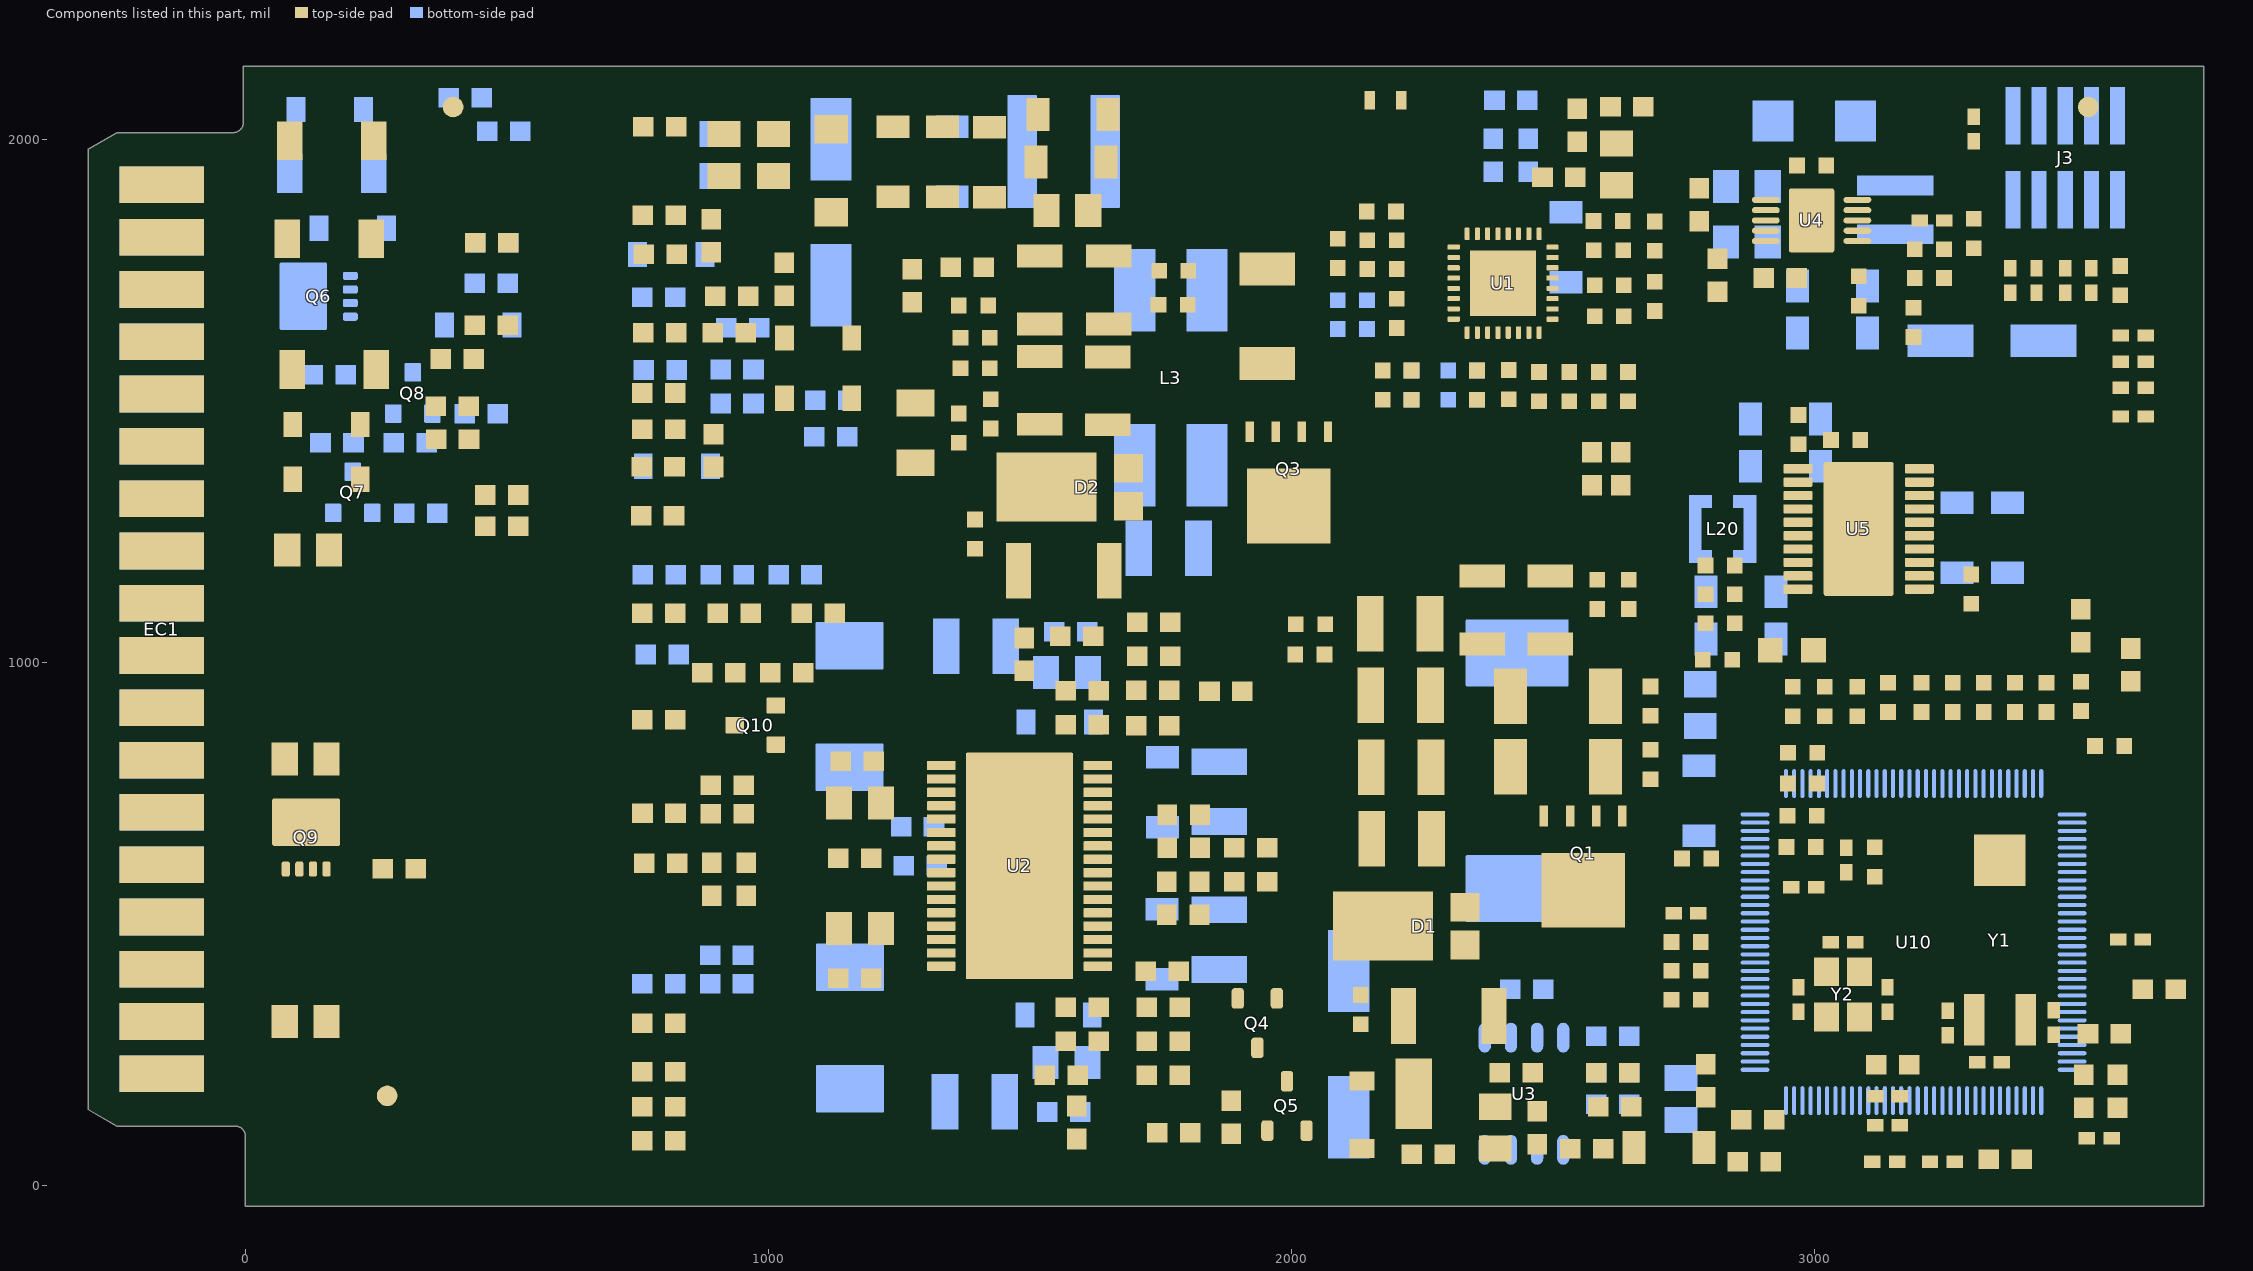
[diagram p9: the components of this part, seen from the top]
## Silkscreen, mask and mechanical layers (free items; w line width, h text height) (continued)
Drill Drawing:
  lines w10: 6263.95,4738.95 6291.58,4752.77 6319.21,4738.95 6305.39,4766.58 6319.21,4794.21 6291.58,4780.39 6263.95,4794.21 6277.77,4766.58 6263.95,4738.95 ; 6263.95,4918.53 6319.21,4918.53 6291.58,4863.27 6263.95,4918.53 ; 6263.95,5001.41 6277.77,5001.41 6291.58,4987.59 6305.39,5001.41 6319.21,5001.41 6305.39,5015.22 6319.21,5029.03 6305.39,5029.03 6291.58,5042.85 6277.77,5029.03 6263.95,5029.03 6277.77,5015.22 6263.95,5001.41 ; 6263.95,5125.73 6277.77,5125.73 6277.77,5111.91 6305.39,5111.91 6305.39,5125.73 6319.21,5125.73 6319.21,5153.35 6305.39,5153.35 6305.39,5167.17 6277.77,5167.17 6277.77,5153.35 6263.95,5153.35 6263.95,5125.73 ; 6263.95,5236.23 6263.95,5250.05 6277.77,5263.86 6263.95,5277.67 6263.95,5291.49 6277.77,5291.49 6291.58,5277.67 6305.39,5291.49 6319.21,5291.49 6319.21,5277.67 6305.39,5263.86 6319.21,5250.05 6319.21,5236.23 6305.39,5236.23 6291.58,5250.05 6277.77,5236.23 6263.95,5236.23
  lines w12: 6213.86,4701.66 9445.35,4701.66 ; 6213.86,5323.26 9445.35,5323.26 ; 6551.72,4577.34 6551.72,5447.58 ; 6883.72,4577.34 6883.72,5447.58 ; 7520.29,4577.34 7520.29,5447.58 ; 7779.43,4577.34 7779.43,5447.58 ; 8154.59,4577.34 8154.59,5447.58 ; 8878.92,4577.34 8878.92,5447.58 ; 6213.86,4577.34 9445.35,4577.34 9445.35,5447.58 6213.86,5447.58 6213.86,4577.34
  text "Symbol" at 6288.45,5360.55 h72
  text "Quantity" at 6589.02,5360.55 h72
  text "Finished Hole Size" at 6921.02,5360.55 h72
  text "Plated" at 7557.58,5360.55 h72
  text "Hole Type" at 7816.72,5360.55 h72
  text "Drill Layer Pair" at 8191.88,5360.55 h72
  text "Hole Tolerance" at 8916.21,5360.55 h72
  text "75" at 6589.02,5236.23 h60
  text "7.87mil (0.200mm)" at 6921.02,5236.23 h60
  text "PTH" at 7557.58,5236.23 h60
  text "Round" at 7816.72,5236.23 h60
  text "Top Layer - Bottom Layer" at 8191.88,5236.23 h60
  text "1" at 6589.02,5111.91 h60
  text "8.00mil (0.203mm)" at 6921.02,5111.91 h60
  text "PTH" at 7557.58,5111.91 h60
  text "Round" at 7816.72,5111.91 h60
  text "Top Layer - Bottom Layer" at 8191.88,5111.91 h60
  text "+16.00mil" at 8916.21,5111.91 h60
  text "317" at 6589.02,4987.59 h60
  text "8.00mil (0.203mm)" at 6921.02,4987.59 h60
  text "PTH" at 7557.58,4987.59 h60
  text "Round" at 7816.72,4987.59 h60
  text "Top Layer - Bottom Layer" at 8191.88,4987.59 h60
  text "299" at 6589.02,4863.27 h60
  text "10.00mil (0.254mm)" at 6921.02,4863.27 h60
  text "PTH" at 7557.58,4863.27 h60
  text "Round" at 7816.72,4863.27 h60
  text "Top Layer - Bottom Layer" at 8191.88,4863.27 h60
  text "18" at 6589.02,4738.95 h60
  text "28.00mil (0.711mm)" at 6921.02,4738.95 h60
  text "PTH" at 7557.58,4738.95 h60
  text "Round" at 7816.72,4738.95 h60
  text "Top Layer - Bottom Layer" at 8191.88,4738.95 h60
  text "710 Total" at 6589.02,4614.63 h60
  text ".Layer_Name" at 293.21,-858.5 h60
Mechanical 17:
  lines w10: 21,0 21,2126
  text ".Layer_Name" at 293.21,-858.5 h60
Mechanical 18:
  text ".Layer_Name" at 293.21,-858.5 h60
Mechanical 19:
  text ".Layer_Name" at 293.21,-858.5 h60

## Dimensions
-283.79,-400.01 to 716.21,-400.01 on M2 Board Dimensions
3745,-40 to 0,-40 on M2 Board Dimensions
3745,2140 to 3745,-40 on M2 Board Dimensions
